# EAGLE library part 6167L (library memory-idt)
MEMORY

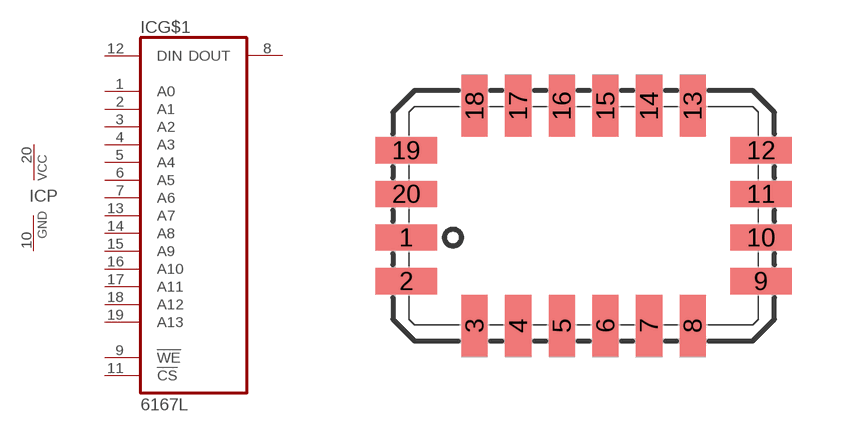
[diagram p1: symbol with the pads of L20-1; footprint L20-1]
Designator prefix IC; gates G$1=6167 P=VCCGND

## 6167L (OC_FARNELL: unknown; OC_NEWARK: unknown)  [L20-1]
1  G$1:A0  in
2  G$1:A1  in
3  G$1:A2  in
4  G$1:A3  in
5  G$1:A4  in
6  G$1:A5  in
7  G$1:A6  in
8  G$1:DOUT  out
9  G$1:!WE  in
10  P:GND  pwr
11  G$1:!CS  in
12  G$1:DIN  in
13  G$1:A7  in
14  G$1:A8  in
15  G$1:A9  in
16  G$1:A10  in
17  G$1:A11  in
18  G$1:A12  in
19  G$1:A13  in
20  P:VCC  pwr

## Footprint L20-1 (pad centres in mm)
PLASTIC LEADED CHIP CARRIER rectangle
smd 1.8 x 0.76: 1 -4.53,-0.635; 2 -4.53,-1.905; 9 5.8,-1.905; 10 5.8,-0.635; 11 5.8,0.635; 12 5.8,1.905; 19 -4.53,1.905; 20 -4.53,0.635
smd 0.76 x 1.8: 3 -2.54,-3.2; 4 -1.27,-3.2; 5 0,-3.2; 6 1.27,-3.2; 7 2.54,-3.2; 8 3.81,-3.2; 13 3.81,3.2; 14 2.54,3.2; 15 1.27,3.2; 16 0,3.2; 17 -1.27,3.2; 18 -2.54,3.2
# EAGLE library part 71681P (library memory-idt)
MEMORY

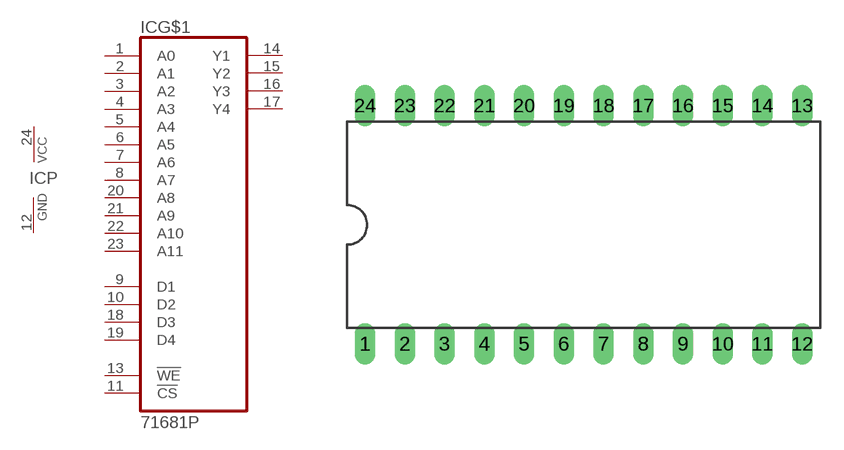
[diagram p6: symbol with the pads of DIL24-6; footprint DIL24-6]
Designator prefix IC; gates G$1=71681 P=VCCGND

## 71681P (OC_FARNELL: unknown; OC_NEWARK: unknown)  [DIL24-6]
1  G$1:A0  in
2  G$1:A1  in
3  G$1:A2  in
4  G$1:A3  in
5  G$1:A4  in
6  G$1:A5  in
7  G$1:A6  in
8  G$1:A7  in
9  G$1:D1  in
10  G$1:D2  in
11  G$1:!CS  in
12  P:GND  pwr
13  G$1:!WE  in
14  G$1:Y1  out
15  G$1:Y2  out
16  G$1:Y3  out
17  G$1:Y4  out
18  G$1:D3  in
19  G$1:D4  in
20  G$1:A8  in
21  G$1:A9  in
22  G$1:A10  in
23  G$1:A11  in
24  P:VCC  pwr

## Footprint DIL24-6 (pad centres in mm)
Dual In Line Package 0.6 inch
drill 0.813 long: 1 -13.97,-7.62; 2 -11.43,-7.62; 3 -8.89,-7.62; 4 -6.35,-7.62; 5 -3.81,-7.62; 6 -1.27,-7.62; 7 1.27,-7.62; 8 3.81,-7.62; 9 6.35,-7.62; 10 8.89,-7.62; 11 11.43,-7.62; 12 13.97,-7.62; 13 13.97,7.62; 14 11.43,7.62; 15 8.89,7.62; 16 6.35,7.62; 17 3.81,7.62; 18 1.27,7.62; 19 -1.27,7.62; 20 -3.81,7.62; 21 -6.35,7.62; 22 -8.89,7.62; 23 -11.43,7.62; 24 -13.97,7.62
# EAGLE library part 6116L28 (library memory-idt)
MEMORY

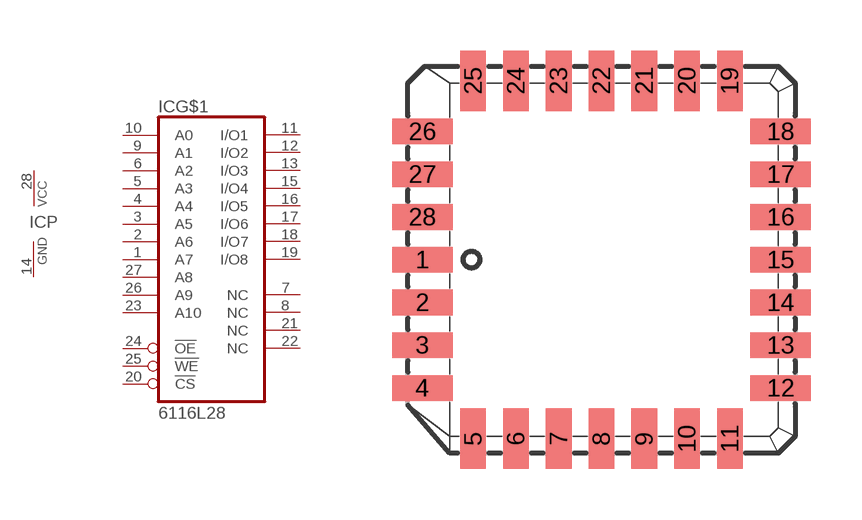
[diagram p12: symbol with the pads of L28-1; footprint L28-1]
Designator prefix IC; gates G$1=6116L28 P=VCCGND

## 6116L28 (OC_FARNELL: unknown; OC_NEWARK: unknown)  [L28-1]
1  G$1:A7  in
2  G$1:A6  in
3  G$1:A5  in
4  G$1:A4  in
5  G$1:A3  in
6  G$1:A2  in
7  G$1:NC  nc
8  G$1:NC  nc
9  G$1:A1  in
10  G$1:A0  in
11  G$1:I/O1
12  G$1:I/O2
13  G$1:I/O3
14  P:GND  pwr
15  G$1:I/O4
16  G$1:I/O5
17  G$1:I/O6
18  G$1:I/O7
19  G$1:I/O8
20  G$1:!CS  in
21  G$1:NC  nc
22  G$1:NC  nc
23  G$1:A10  in
24  G$1:!OE  in
25  G$1:!WE  in
26  G$1:A9  in
27  G$1:A8  in
28  P:VCC  pwr

## Footprint L28-1 (pad centres in mm)
PLASTIC LEADED CHIP CARRIER square
smd 1.8 x 0.76: 1 -5.32,0; 2 -5.32,-1.27; 3 -5.32,-2.54; 4 -5.32,-3.81; 12 5.32,-3.81; 13 5.32,-2.54; 14 5.32,-1.27; 15 5.32,0; 16 5.32,1.27; 17 5.32,2.54; 18 5.32,3.81; 26 -5.32,3.81; 27 -5.32,2.54; 28 -5.32,1.27
smd 0.76 x 1.8: 5 -3.81,-5.32; 6 -2.54,-5.32; 7 -1.27,-5.32; 8 0,-5.32; 9 1.27,-5.32; 10 2.54,-5.32; 11 3.81,-5.32; 19 3.81,5.32; 20 2.54,5.32; 21 1.27,5.32; 22 0,5.32; 23 -1.27,5.32; 24 -2.54,5.32; 25 -3.81,5.32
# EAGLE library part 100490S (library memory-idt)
MEMORY

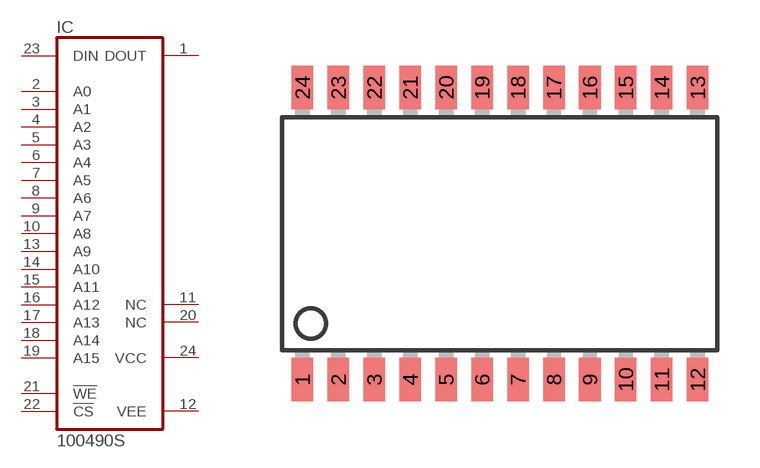
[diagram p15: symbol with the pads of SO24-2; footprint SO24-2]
Designator prefix IC

## 100490S (OC_FARNELL: unknown; OC_NEWARK: unknown)  [SO24-2]
1  DOUT  out
2  A0  in
3  A1  in
4  A2  in
5  A3  in
6  A4  in
7  A5  in
8  A6  in
9  A7  in
10  A8  in
11  NC  nc
12  VEE  pwr
13  A9  in
14  A10  in
15  A11  in
16  A12  in
17  A13  in
18  A14  in
19  A15  in
20  NC  nc
21  !WE  in
22  !CS  in
23  DIN  in
24  VCC  pwr

## Footprint SO24-2 (pad centres in mm)
Small Outline Package
smd 0.762 x 1.524: 1 -6.985,-5.156; 2 -5.715,-5.156; 3 -4.445,-5.156; 4 -3.175,-5.156; 5 -1.905,-5.156; 6 -0.635,-5.156; 7 0.635,-5.156; 8 1.905,-5.156; 9 3.175,-5.156; 10 4.445,-5.156; 11 5.715,-5.156; 12 6.985,-5.156; 13 6.985,5.156; 14 5.715,5.156; 15 4.445,5.156; 16 3.175,5.156; 17 1.905,5.156; 18 0.635,5.156; 19 -0.635,5.156; 20 -1.905,5.156; 21 -3.175,5.156; 22 -4.445,5.156; 23 -5.715,5.156; 24 -6.985,5.156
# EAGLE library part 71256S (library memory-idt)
MEMORY

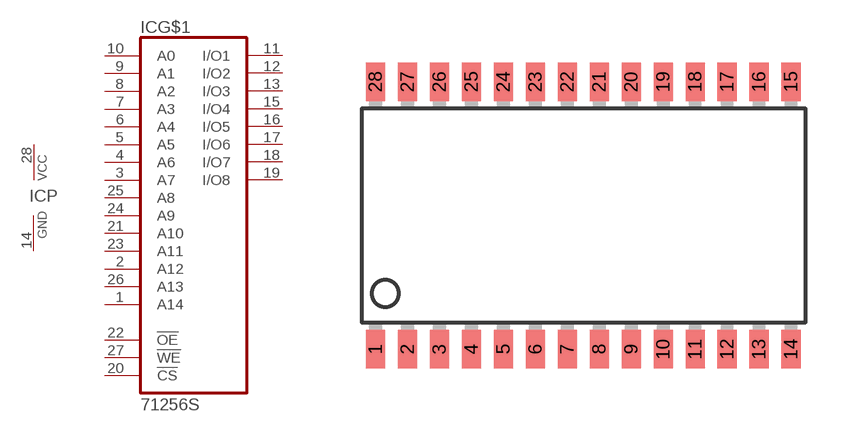
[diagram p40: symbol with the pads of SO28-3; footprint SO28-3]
Designator prefix IC; gates G$1=71256 P=VCCGND

## 71256S (MPN: IDT71256SA20YG; OC_FARNELL: 1218010; OC_NEWARK: 34M6449)  [SO28-3]
1  G$1:A14  in
2  G$1:A12  in
3  G$1:A7  in
4  G$1:A6  in
5  G$1:A5  in
6  G$1:A4  in
7  G$1:A3  in
8  G$1:A2  in
9  G$1:A1  in
10  G$1:A0  in
11  G$1:I/O1
12  G$1:I/O2
13  G$1:I/O3
14  P:GND  pwr
15  G$1:I/O4
16  G$1:I/O5
17  G$1:I/O6
18  G$1:I/O7
19  G$1:I/O8
20  G$1:!CS  in
21  G$1:A10  in
22  G$1:!OE  in
23  G$1:A11  in
24  G$1:A9  in
25  G$1:A8  in
26  G$1:A13  in
27  G$1:!WE  in
28  P:VCC  pwr

## Footprint SO28-3 (pad centres in mm)
Small Outline Package
smd 0.762 x 1.524: 1 -8.255,-5.315; 2 -6.985,-5.315; 3 -5.715,-5.315; 4 -4.445,-5.315; 5 -3.175,-5.315; 6 -1.905,-5.315; 7 -0.635,-5.315; 8 0.635,-5.315; 9 1.905,-5.315; 10 3.175,-5.315; 11 4.445,-5.315; 12 5.715,-5.315; 13 6.985,-5.315; 14 8.255,-5.315; 15 8.255,5.315; 16 6.985,5.315; 17 5.715,5.315; 18 4.445,5.315; 19 3.175,5.315; 20 1.905,5.315; 21 0.635,5.315; 22 -0.635,5.315; 23 -1.905,5.315; 24 -3.175,5.315; 25 -4.445,5.315; 26 -5.715,5.315; 27 -6.985,5.315; 28 -8.255,5.315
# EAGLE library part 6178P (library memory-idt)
MEMORY

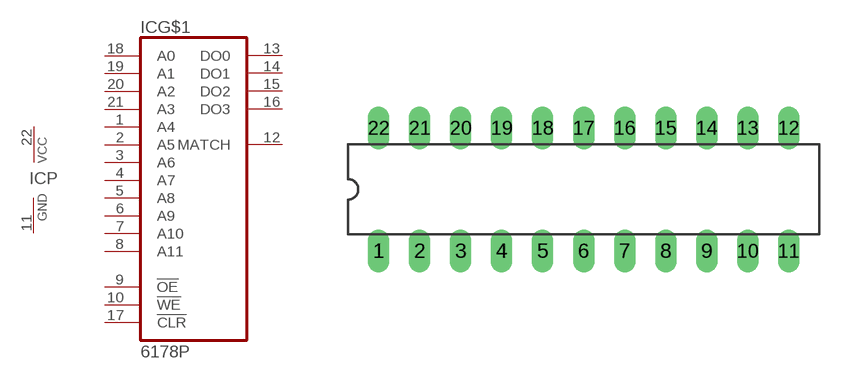
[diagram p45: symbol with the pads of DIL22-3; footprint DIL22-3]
Designator prefix IC; gates G$1=6178 P=VCCGND

## 6178P (OC_FARNELL: unknown; OC_NEWARK: unknown)  [DIL22-3]
1  G$1:A4  in
2  G$1:A5  in
3  G$1:A6  in
4  G$1:A7  in
5  G$1:A8  in
6  G$1:A9  in
7  G$1:A10  in
8  G$1:A11  in
9  G$1:!OE  in
10  G$1:!WE  in
11  P:GND  pwr
12  G$1:MATCH  out
13  G$1:DO0
14  G$1:DO1
15  G$1:DO2
16  G$1:DO3
17  G$1:!CLR  in
18  G$1:A0  in
19  G$1:A1  in
20  G$1:A2  in
21  G$1:A3  in
22  P:VCC  pwr

## Footprint DIL22-3 (pad centres in mm)
Dual In Line Package 0.3 inch
drill 0.813 long: 1 -12.7,-3.81; 2 -10.16,-3.81; 3 -7.62,-3.81; 4 -5.08,-3.81; 5 -2.54,-3.81; 6 0,-3.81; 7 2.54,-3.81; 8 5.08,-3.81; 9 7.62,-3.81; 10 10.16,-3.81; 11 12.7,-3.81; 12 12.7,3.81; 13 10.16,3.81; 14 7.62,3.81; 15 5.08,3.81; 16 2.54,3.81; 17 0,3.81; 18 -2.54,3.81; 19 -5.08,3.81; 20 -7.62,3.81; 21 -10.16,3.81; 22 -12.7,3.81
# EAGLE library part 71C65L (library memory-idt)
MEMORY

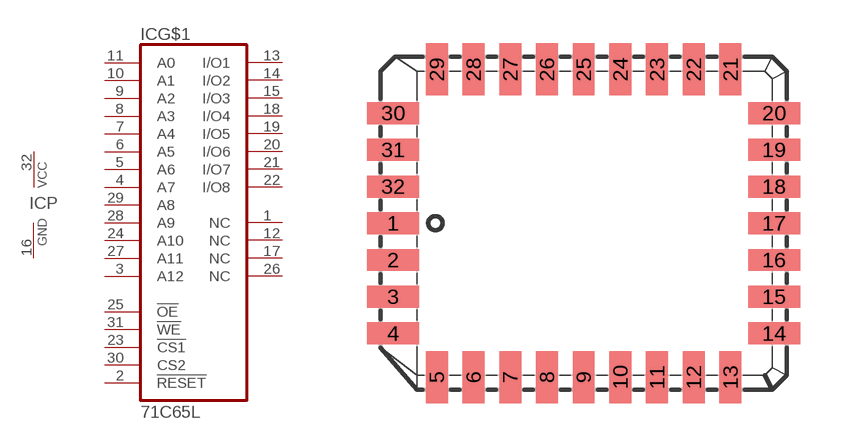
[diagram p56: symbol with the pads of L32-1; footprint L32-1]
Designator prefix IC; gates G$1=71C65L P=VCCGND

## 71C65L (OC_FARNELL: unknown; OC_NEWARK: unknown)  [L32-1]
1  G$1:NC  nc
2  G$1:!RESET  in
3  G$1:A12  in
4  G$1:A7  in
5  G$1:A6  in
6  G$1:A5  in
7  G$1:A4  in
8  G$1:A3  in
9  G$1:A2  in
10  G$1:A1  in
11  G$1:A0  in
12  G$1:NC  nc
13  G$1:I/O1
14  G$1:I/O2
15  G$1:I/O3
16  P:GND  pwr
17  G$1:NC  nc
18  G$1:I/O4
19  G$1:I/O5
20  G$1:I/O6
21  G$1:I/O7
22  G$1:I/O8
23  G$1:!CS1  in
24  G$1:A10  in
25  G$1:!OE  in
26  G$1:NC  nc
27  G$1:A11  in
28  G$1:A9  in
29  G$1:A8  in
30  G$1:CS2  in
31  G$1:!WE  in
32  P:VCC  pwr

## Footprint L32-1 (pad centres in mm)
PLASTIC LEADED CHIP CARRIER rectangle
smd 1.8 x 0.76: 1 -6.59,0; 2 -6.59,-1.27; 3 -6.59,-2.54; 4 -6.59,-3.81; 14 6.59,-3.81; 15 6.59,-2.54; 16 6.59,-1.27; 17 6.59,0; 18 6.59,1.27; 19 6.59,2.54; 20 6.59,3.81; 30 -6.59,3.81; 31 -6.59,2.54; 32 -6.59,1.27
smd 0.76 x 1.8: 5 -5.08,-5.32; 6 -3.81,-5.32; 7 -2.54,-5.32; 8 -1.27,-5.32; 9 0,-5.32; 10 1.27,-5.32; 11 2.54,-5.32; 12 3.81,-5.32; 13 5.08,-5.32; 21 5.08,5.32; 22 3.81,5.32; 23 2.54,5.32; 24 1.27,5.32; 25 0,5.32; 26 -1.27,5.32; 27 -2.54,5.32; 28 -3.81,5.32; 29 -5.08,5.32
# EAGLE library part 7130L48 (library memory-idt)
MEMORY

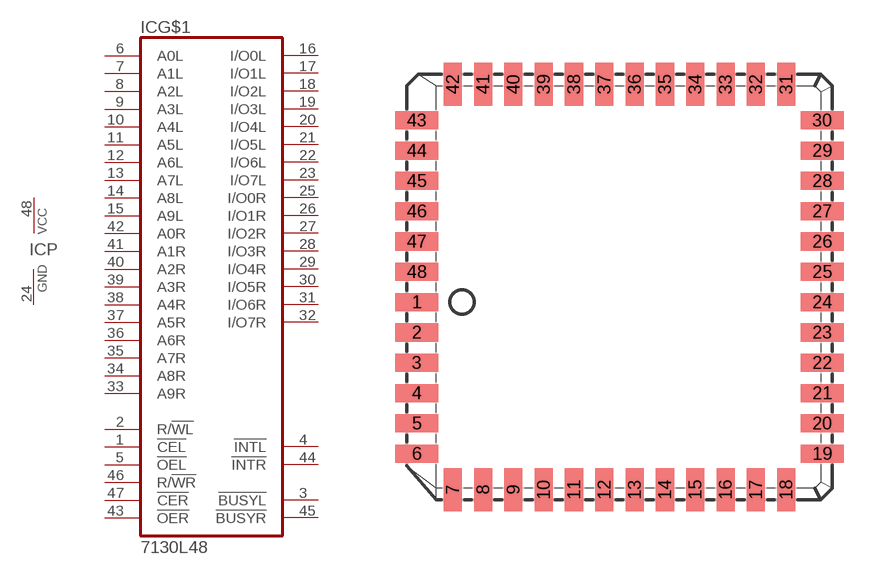
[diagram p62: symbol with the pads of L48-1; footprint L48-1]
Designator prefix IC; gates G$1=7130 P=VCCGND

## 7130L48 (OC_FARNELL: unknown; OC_NEWARK: unknown)  [L48-1]
1  G$1:!CEL  in
2  G$1:R/!WL  in
3  G$1:!BUSYL
4  G$1:!INTL  out
5  G$1:!OEL  in
6  G$1:A0L  in
7  G$1:A1L  in
8  G$1:A2L  in
9  G$1:A3L  in
10  G$1:A4L  in
11  G$1:A5L  in
12  G$1:A6L  in
13  G$1:A7L  in
14  G$1:A8L  in
15  G$1:A9L  in
16  G$1:I/O0L
17  G$1:I/O1L
18  G$1:I/O2L
19  G$1:I/O3L
20  G$1:I/O4L
21  G$1:I/O5L
22  G$1:I/O6L
23  G$1:I/O7L
24  P:GND  pwr
25  G$1:I/O0R
26  G$1:I/O1R
27  G$1:I/O2R
28  G$1:I/O3R
29  G$1:I/O4R
30  G$1:I/O5R
31  G$1:I/O6R
32  G$1:I/O7R
33  G$1:A9R  in
34  G$1:A8R  in
35  G$1:A7R  in
36  G$1:A6R  in
37  G$1:A5R  in
38  G$1:A4R  in
39  G$1:A3R  in
40  G$1:A2R  in
41  G$1:A1R  in
42  G$1:A0R  in
43  G$1:!OER  in
44  G$1:!INTR  out
45  G$1:!BUSYR
46  G$1:R/!WR  in
47  G$1:!CER  in
48  P:VCC  pwr

## Footprint L48-1 (pad centres in mm)
PLASTIC LEADED CHIP CARRIER square
smd 1.8 x 0.76: 1 -7.86,0; 2 -7.86,-1.27; 3 -7.86,-2.54; 4 -7.86,-3.81; 5 -7.86,-5.08; 6 -7.86,-6.35; 19 9.13,-6.35; 20 9.13,-5.08; 21 9.13,-3.81; 22 9.13,-2.54; 23 9.13,-1.27; 24 9.13,0; 25 9.13,1.27; 26 9.13,2.54; 27 9.13,3.81; 28 9.13,5.08; 29 9.13,6.35; 30 9.13,7.62; 43 -7.86,7.62; 44 -7.86,6.35; 45 -7.86,5.08; 46 -7.86,3.81; 47 -7.86,2.54; 48 -7.86,1.27
smd 0.76 x 1.8: 7 -6.35,-7.86; 8 -5.08,-7.86; 9 -3.81,-7.86; 10 -2.54,-7.86; 11 -1.27,-7.86; 12 0,-7.86; 13 1.27,-7.86; 14 2.54,-7.86; 15 3.81,-7.86; 16 5.08,-7.86; 17 6.35,-7.86; 18 7.62,-7.86; 31 7.62,9.13; 32 6.35,9.13; 33 5.08,9.13; 34 3.81,9.13; 35 2.54,9.13; 36 1.27,9.13; 37 0,9.13; 38 -1.27,9.13; 39 -2.54,9.13; 40 -3.81,9.13; 41 -5.08,9.13; 42 -6.35,9.13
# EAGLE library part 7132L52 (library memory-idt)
MEMORY

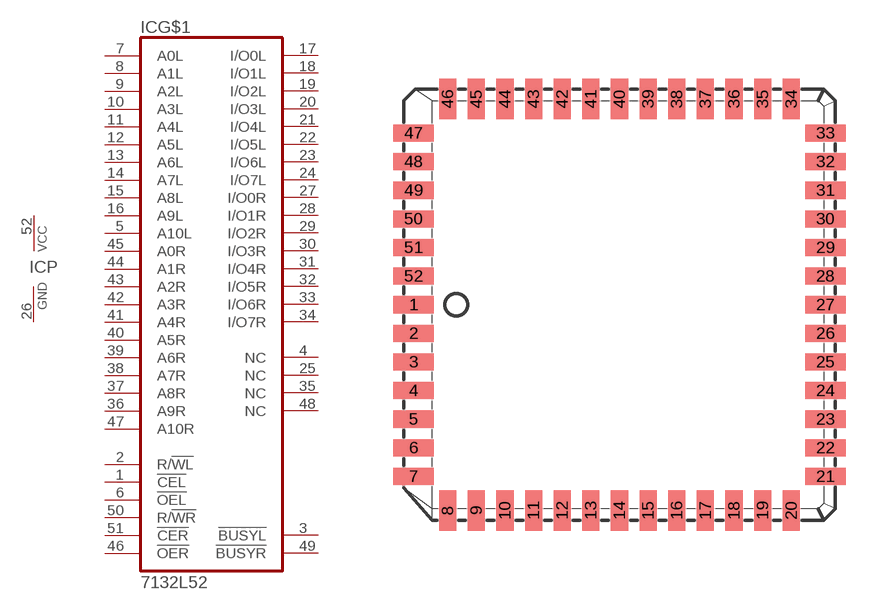
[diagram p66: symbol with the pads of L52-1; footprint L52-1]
Designator prefix IC; gates G$1=7132L P=VCCGND

## 7132L52 (MPN: IDT7132LA20JG; OC_FARNELL: 1688283; OC_NEWARK: 52R2132)  [L52-1]
1  G$1:!CEL  in
2  G$1:R/!WL  in
3  G$1:!BUSYL
4  G$1:NC  nc
5  G$1:A10L  in
6  G$1:!OEL  in
7  G$1:A0L  in
8  G$1:A1L  in
9  G$1:A2L  in
10  G$1:A3L  in
11  G$1:A4L  in
12  G$1:A5L  in
13  G$1:A6L  in
14  G$1:A7L  in
15  G$1:A8L  in
16  G$1:A9L  in
17  G$1:I/O0L
18  G$1:I/O1L
19  G$1:I/O2L
20  G$1:I/O3L
21  G$1:I/O4L
22  G$1:I/O5L
23  G$1:I/O6L
24  G$1:I/O7L
25  G$1:NC  nc
26  P:GND  pwr
27  G$1:I/O0R
28  G$1:I/O1R
29  G$1:I/O2R
30  G$1:I/O3R
31  G$1:I/O4R
32  G$1:I/O5R
33  G$1:I/O6R
34  G$1:I/O7R
35  G$1:NC  nc
36  G$1:A9R  in
37  G$1:A8R  in
38  G$1:A7R  in
39  G$1:A6R  in
40  G$1:A5R  in
41  G$1:A4R  in
42  G$1:A3R  in
43  G$1:A2R  in
44  G$1:A1R  in
45  G$1:A0R  in
46  G$1:!OER  in
47  G$1:A10R  in
48  G$1:NC  nc
49  G$1:!BUSYR
50  G$1:R/!WR  in
51  G$1:!CER  in
52  P:VCC  pwr

## Footprint L52-1 (pad centres in mm)
PLASTIC LEADED CHIP CARRIER square
smd 1.8 x 0.76: 1 -9.13,0; 2 -9.13,-1.27; 3 -9.13,-2.54; 4 -9.13,-3.81; 5 -9.13,-5.08; 6 -9.13,-6.35; 7 -9.13,-7.62; 21 9.13,-7.62; 22 9.13,-6.35; 23 9.13,-5.08; 24 9.13,-3.81; 25 9.13,-2.54; 26 9.13,-1.27; 27 9.13,0; 28 9.13,1.27; 29 9.13,2.54; 30 9.13,3.81; 31 9.13,5.08; 32 9.13,6.35; 33 9.13,7.62; 47 -9.13,7.62; 48 -9.13,6.35; 49 -9.13,5.08; 50 -9.13,3.81; 51 -9.13,2.54; 52 -9.13,1.27
smd 0.76 x 1.8: 8 -7.62,-9.13; 9 -6.35,-9.13; 10 -5.08,-9.13; 11 -3.81,-9.13; 12 -2.54,-9.13; 13 -1.27,-9.13; 14 0,-9.13; 15 1.27,-9.13; 16 2.54,-9.13; 17 3.81,-9.13; 18 5.08,-9.13; 19 6.35,-9.13; 20 7.62,-9.13; 34 7.62,9.13; 35 6.35,9.13; 36 5.08,9.13; 37 3.81,9.13; 38 2.54,9.13; 39 1.27,9.13; 40 0,9.13; 41 -1.27,9.13; 42 -2.54,9.13; 43 -3.81,9.13; 44 -5.08,9.13; 45 -6.35,9.13; 46 -7.62,9.13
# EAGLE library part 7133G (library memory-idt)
MEMORY

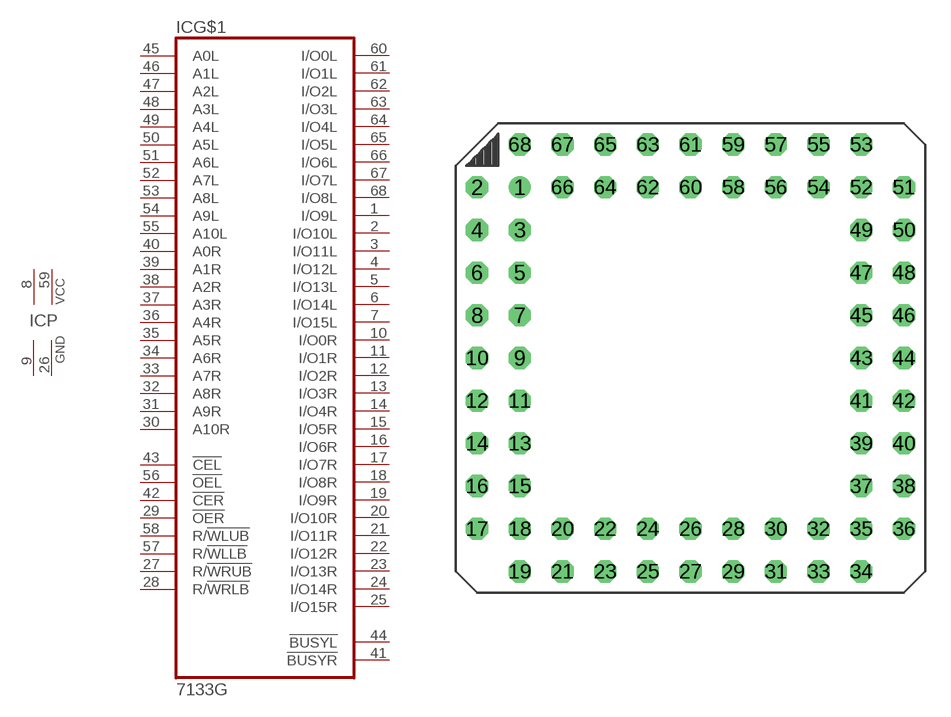
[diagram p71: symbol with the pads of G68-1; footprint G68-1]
Designator prefix IC; gates G$1=7133 P=2VCC2GND

## 7133G (OC_FARNELL: unknown; OC_NEWARK: unknown)  [G68-1]
1  G$1:I/O9L
2  G$1:I/O10L
3  G$1:I/O11L
4  G$1:I/O12L
5  G$1:I/O13L
6  G$1:I/O14L
7  G$1:I/O15L
8  P:VCC  pwr
9  P:GND  pwr
10  G$1:I/O0R
11  G$1:I/O1R
12  G$1:I/O2R
13  G$1:I/O3R
14  G$1:I/O4R
15  G$1:I/O5R
16  G$1:I/O6R
17  G$1:I/O7R
18  G$1:I/O8R
19  G$1:I/O9R
20  G$1:I/O10R
21  G$1:I/O11R
22  G$1:I/O12R
23  G$1:I/O13R
24  G$1:I/O14R
25  G$1:I/O15R
26  P:GND  pwr
27  G$1:R/!WRUB  in
28  G$1:R/!WRLB  in
29  G$1:!OER  in
30  G$1:A10R  in
31  G$1:A9R  in
32  G$1:A8R  in
33  G$1:A7R  in
34  G$1:A6R  in
35  G$1:A5R  in
36  G$1:A4R  in
37  G$1:A3R  in
38  G$1:A2R  in
39  G$1:A1R  in
40  G$1:A0R  in
41  G$1:!BUSYR  out
42  G$1:!CER  in
43  G$1:!CEL  in
44  G$1:!BUSYL  out
45  G$1:A0L  in
46  G$1:A1L  in
47  G$1:A2L  in
48  G$1:A3L  in
49  G$1:A4L  in
50  G$1:A5L  in
51  G$1:A6L  in
52  G$1:A7L  in
53  G$1:A8L  in
54  G$1:A9L  in
55  G$1:A10L  in
56  G$1:!OEL  in
57  G$1:R/!WLLB  in
58  G$1:R/!WLUB  in
59  P:VCC  pwr
60  G$1:I/O0L
61  G$1:I/O1L
62  G$1:I/O2L
63  G$1:I/O3L
64  G$1:I/O4L
65  G$1:I/O5L
66  G$1:I/O6L
67  G$1:I/O7L
68  G$1:I/O8L

## Footprint G68-1 (pad centres in mm)
Grid Array
drill 0.813 round: 1 -10.16,10.16
drill 0.813 octagon: 2 -12.7,10.16; 3 -10.16,7.62; 4 -12.7,7.62; 5 -10.16,5.08; 6 -12.7,5.08; 7 -10.16,2.54; 8 -12.7,2.54; 9 -10.16,0; 10 -12.7,0; 11 -10.16,-2.54; 12 -12.7,-2.54; 13 -10.16,-5.08; 14 -12.7,-5.08; 15 -10.16,-7.62; 16 -12.7,-7.62; 17 -12.7,-10.16; 18 -10.16,-10.16; 19 -10.16,-12.7; 20 -7.62,-10.16; 21 -7.62,-12.7; 22 -5.08,-10.16; 23 -5.08,-12.7; 24 -2.54,-10.16; 25 -2.54,-12.7; 26 0,-10.16; 27 0,-12.7; 28 2.54,-10.16; 29 2.54,-12.7; 30 5.08,-10.16; 31 5.08,-12.7; 32 7.62,-10.16; 33 7.62,-12.7; 34 10.16,-12.7; 35 10.16,-10.16; 36 12.7,-10.16; 37 10.16,-7.62; 38 12.7,-7.62; 39 10.16,-5.08; 40 12.7,-5.08; 41 10.16,-2.54; 42 12.7,-2.54; 43 10.16,0; 44 12.7,0; 45 10.16,2.54; 46 12.7,2.54; 47 10.16,5.08; 48 12.7,5.08; 49 10.16,7.62; 50 12.7,7.62; 51 12.7,10.16; 52 10.16,10.16; 53 10.16,12.7; 54 7.62,10.16; 55 7.62,12.7; 56 5.08,10.16; 57 5.08,12.7; 58 2.54,10.16; 59 2.54,12.7; 60 0,10.16; 61 0,12.7; 62 -2.54,10.16; 63 -2.54,12.7; 64 -5.08,10.16; 65 -5.08,12.7; 66 -7.62,10.16; 67 -7.62,12.7; 68 -10.16,12.7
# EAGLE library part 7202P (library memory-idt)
MEMORY

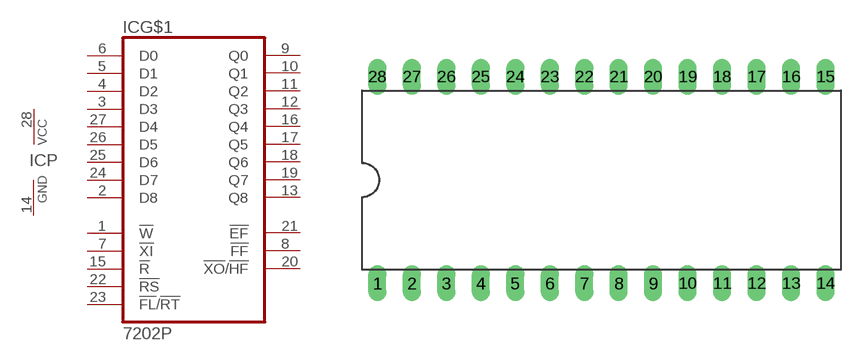
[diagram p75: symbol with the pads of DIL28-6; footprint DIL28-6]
Designator prefix IC; gates G$1=7202 P=VCCGND

## 7202P (OC_FARNELL: unknown; OC_NEWARK: unknown)  [DIL28-6]
1  G$1:!W  in
2  G$1:D8  in
3  G$1:D3  in
4  G$1:D2  in
5  G$1:D1  in
6  G$1:D0  in
7  G$1:!XI  in
8  G$1:!FF  out
9  G$1:Q0  out
10  G$1:Q1  out
11  G$1:Q2  out
12  G$1:Q3  out
13  G$1:Q8  out
14  P:GND  pwr
15  G$1:!R  in
16  G$1:Q4  out
17  G$1:Q5  out
18  G$1:Q6  out
19  G$1:Q7  out
20  G$1:!XO!/!HF  out
21  G$1:!EF  out
22  G$1:!RS  in
23  G$1:!FL!/!RT  in
24  G$1:D7  in
25  G$1:D6  in
26  G$1:D5  in
27  G$1:D4  in
28  P:VCC  pwr

## Footprint DIL28-6 (pad centres in mm)
Dual In Line Package 0.6 inch
drill 0.813 long: 1 -16.51,-7.62; 2 -13.97,-7.62; 3 -11.43,-7.62; 4 -8.89,-7.62; 5 -6.35,-7.62; 6 -3.81,-7.62; 7 -1.27,-7.62; 8 1.27,-7.62; 9 3.81,-7.62; 10 6.35,-7.62; 11 8.89,-7.62; 12 11.43,-7.62; 13 13.97,-7.62; 14 16.51,-7.62; 15 16.51,7.62; 16 13.97,7.62; 17 11.43,7.62; 18 8.89,7.62; 19 6.35,7.62; 20 3.81,7.62; 21 1.27,7.62; 22 -1.27,7.62; 23 -3.81,7.62; 24 -6.35,7.62; 25 -8.89,7.62; 26 -11.43,7.62; 27 -13.97,7.62; 28 -16.51,7.62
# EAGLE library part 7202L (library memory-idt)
MEMORY

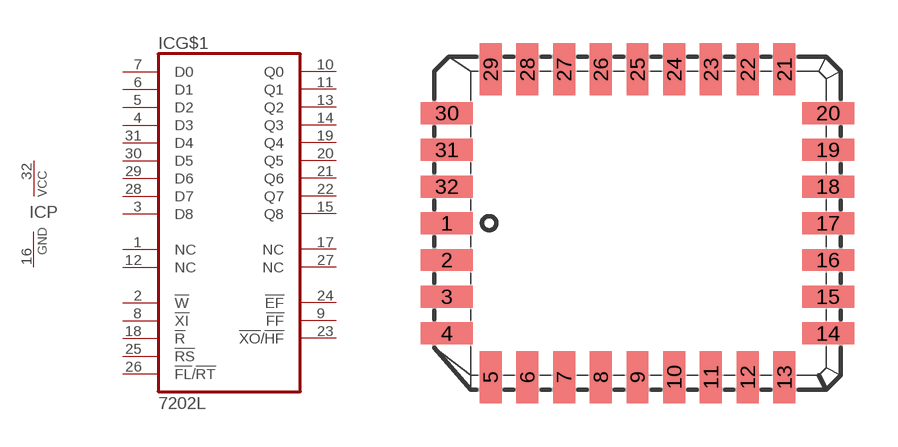
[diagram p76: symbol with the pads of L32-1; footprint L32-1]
Designator prefix IC; gates G$1=7202L P=VCCGND

## 7202L (MPN: IDT7202LA35JG; OC_FARNELL: 1218006; OC_NEWARK: 24M2901)  [L32-1]
1  G$1:NC  nc
2  G$1:!W  in
3  G$1:D8  in
4  G$1:D3  in
5  G$1:D2  in
6  G$1:D1  in
7  G$1:D0  in
8  G$1:!XI  in
9  G$1:!FF  out
10  G$1:Q0  out
11  G$1:Q1  out
12  G$1:NC  nc
13  G$1:Q2  out
14  G$1:Q3  out
15  G$1:Q8  out
16  P:GND  pwr
17  G$1:NC  nc
18  G$1:!R  in
19  G$1:Q4  out
20  G$1:Q5  out
21  G$1:Q6  out
22  G$1:Q7  out
23  G$1:!XO!/!HF  out
24  G$1:!EF  out
25  G$1:!RS  in
26  G$1:!FL!/!RT  in
27  G$1:NC  nc
28  G$1:D7  in
29  G$1:D6  in
30  G$1:D5  in
31  G$1:D4  in
32  P:VCC  pwr

## Footprint L32-1 (pad centres in mm)
PLASTIC LEADED CHIP CARRIER rectangle
smd 1.8 x 0.76: 1 -6.59,0; 2 -6.59,-1.27; 3 -6.59,-2.54; 4 -6.59,-3.81; 14 6.59,-3.81; 15 6.59,-2.54; 16 6.59,-1.27; 17 6.59,0; 18 6.59,1.27; 19 6.59,2.54; 20 6.59,3.81; 30 -6.59,3.81; 31 -6.59,2.54; 32 -6.59,1.27
smd 0.76 x 1.8: 5 -5.08,-5.32; 6 -3.81,-5.32; 7 -2.54,-5.32; 8 -1.27,-5.32; 9 0,-5.32; 10 1.27,-5.32; 11 2.54,-5.32; 12 3.81,-5.32; 13 5.08,-5.32; 21 5.08,5.32; 22 3.81,5.32; 23 2.54,5.32; 24 1.27,5.32; 25 0,5.32; 26 -1.27,5.32; 27 -2.54,5.32; 28 -3.81,5.32; 29 -5.08,5.32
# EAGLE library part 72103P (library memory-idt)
MEMORY

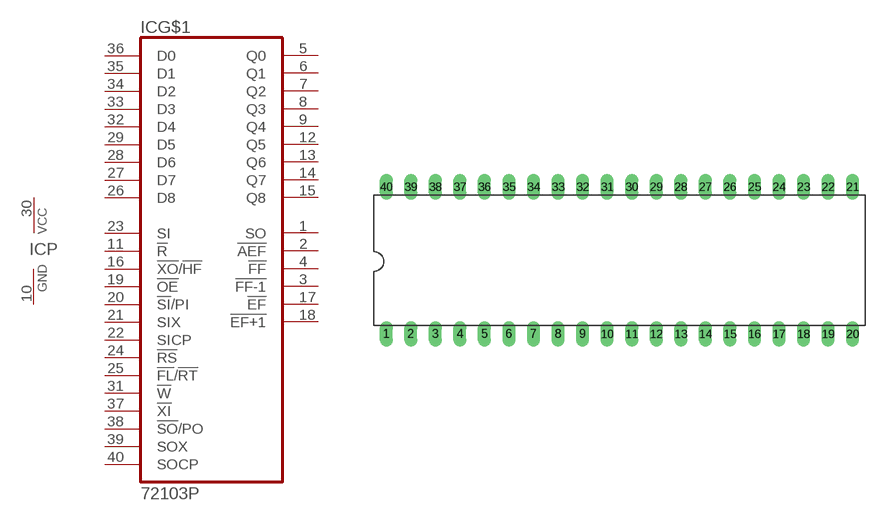
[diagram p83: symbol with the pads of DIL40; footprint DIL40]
Designator prefix IC; gates G$1=72103 P=VCCGND

## 72103P (OC_FARNELL: unknown; OC_NEWARK: unknown)  [DIL40]
1  G$1:SO  out
2  G$1:!AEF  out
3  G$1:!FF-1  out
4  G$1:!FF  out
5  G$1:Q0  out
6  G$1:Q1  out
7  G$1:Q2  out
8  G$1:Q3  out
9  G$1:Q4  out
10  P:GND  pwr
11  G$1:!R  in
12  G$1:Q5  out
13  G$1:Q6  out
14  G$1:Q7  out
15  G$1:Q8  out
16  G$1:!XO!/!HF  in
17  G$1:!EF  out
18  G$1:!EF+1  out
19  G$1:!OE  in
20  G$1:!SI!/PI  in
21  G$1:SIX  in
22  G$1:SICP  in
23  G$1:SI  in
24  G$1:!RS  in
25  G$1:!FL!/!RT  in
26  G$1:D8  in
27  G$1:D7  in
28  G$1:D6  in
29  G$1:D5  in
30  P:VCC  pwr
31  G$1:!W  in
32  G$1:D4  in
33  G$1:D3  in
34  G$1:D2  in
35  G$1:D1  in
36  G$1:D0  in
37  G$1:!XI  in
38  G$1:!SO!/PO  in
39  G$1:SOX  in
40  G$1:SOCP  in

## Footprint DIL40 (pad centres in mm)
Dual In Line Package
drill 0.813 long: 1 -24.13,-7.62; 2 -21.59,-7.62; 3 -19.05,-7.62; 4 -16.51,-7.62; 5 -13.97,-7.62; 6 -11.43,-7.62; 7 -8.89,-7.62; 8 -6.35,-7.62; 9 -3.81,-7.62; 10 -1.27,-7.62; 11 1.27,-7.62; 12 3.81,-7.62; 13 6.35,-7.62; 14 8.89,-7.62; 15 11.43,-7.62; 16 13.97,-7.62; 17 16.51,-7.62; 18 19.05,-7.62; 19 21.59,-7.62; 20 24.13,-7.62; 21 24.13,7.62; 22 21.59,7.62; 23 19.05,7.62; 24 16.51,7.62; 25 13.97,7.62; 26 11.43,7.62; 27 8.89,7.62; 28 6.35,7.62; 29 3.81,7.62; 30 1.27,7.62; 31 -1.27,7.62; 32 -3.81,7.62; 33 -6.35,7.62; 34 -8.89,7.62; 35 -11.43,7.62; 36 -13.97,7.62; 37 -16.51,7.62; 38 -19.05,7.62; 39 -21.59,7.62; 40 -24.13,7.62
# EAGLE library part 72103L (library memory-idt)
MEMORY

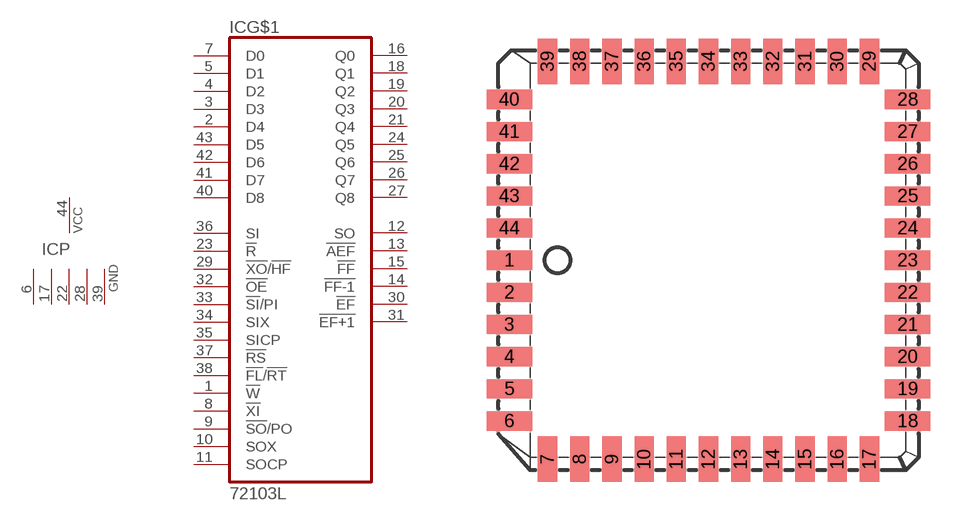
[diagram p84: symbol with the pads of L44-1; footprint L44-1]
Designator prefix IC; gates G$1=72103 P=1VCC5GND

## 72103L (OC_FARNELL: unknown; OC_NEWARK: unknown)  [L44-1]
1  G$1:!W  in
2  G$1:D4  in
3  G$1:D3  in
4  G$1:D2  in
5  G$1:D1  in
6  P:GND  pwr
7  G$1:D0  in
8  G$1:!XI  in
9  G$1:!SO!/PO  in
10  G$1:SOX  in
11  G$1:SOCP  in
12  G$1:SO  out
13  G$1:!AEF  out
14  G$1:!FF-1  out
15  G$1:!FF  out
16  G$1:Q0  out
17  P:GND  pwr
18  G$1:Q1  out
19  G$1:Q2  out
20  G$1:Q3  out
21  G$1:Q4  out
22  P:GND  pwr
23  G$1:!R  in
24  G$1:Q5  out
25  G$1:Q6  out
26  G$1:Q7  out
27  G$1:Q8  out
28  P:GND  pwr
29  G$1:!XO!/!HF  in
30  G$1:!EF  out
31  G$1:!EF+1  out
32  G$1:!OE  in
33  G$1:!SI!/PI  in
34  G$1:SIX  in
35  G$1:SICP  in
36  G$1:SI  in
37  G$1:!RS  in
38  G$1:!FL!/!RT  in
39  P:GND  pwr
40  G$1:D8  in
41  G$1:D7  in
42  G$1:D6  in
43  G$1:D5  in
44  P:VCC  pwr

## Footprint L44-1 (pad centres in mm)
PLASTIC LEADED CHIP CARRIER square
smd 1.8 x 0.76: 1 -7.86,0; 2 -7.86,-1.27; 3 -7.86,-2.54; 4 -7.86,-3.81; 5 -7.86,-5.08; 6 -7.86,-6.35; 18 7.86,-6.35; 19 7.86,-5.08; 20 7.86,-3.81; 21 7.86,-2.54; 22 7.86,-1.27; 23 7.86,0; 24 7.86,1.27; 25 7.86,2.54; 26 7.86,3.81; 27 7.86,5.08; 28 7.86,6.35; 40 -7.86,6.35; 41 -7.86,5.08; 42 -7.86,3.81; 43 -7.86,2.54; 44 -7.86,1.27
smd 0.76 x 1.8: 7 -6.35,-7.86; 8 -5.08,-7.86; 9 -3.81,-7.86; 10 -2.54,-7.86; 11 -1.27,-7.86; 12 0,-7.86; 13 1.27,-7.86; 14 2.54,-7.86; 15 3.81,-7.86; 16 5.08,-7.86; 17 6.35,-7.86; 29 6.35,7.86; 30 5.08,7.86; 31 3.81,7.86; 32 2.54,7.86; 33 1.27,7.86; 34 0,7.86; 35 -1.27,7.86; 36 -2.54,7.86; 37 -3.81,7.86; 38 -5.08,7.86; 39 -6.35,7.86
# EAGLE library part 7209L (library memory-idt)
MEMORY

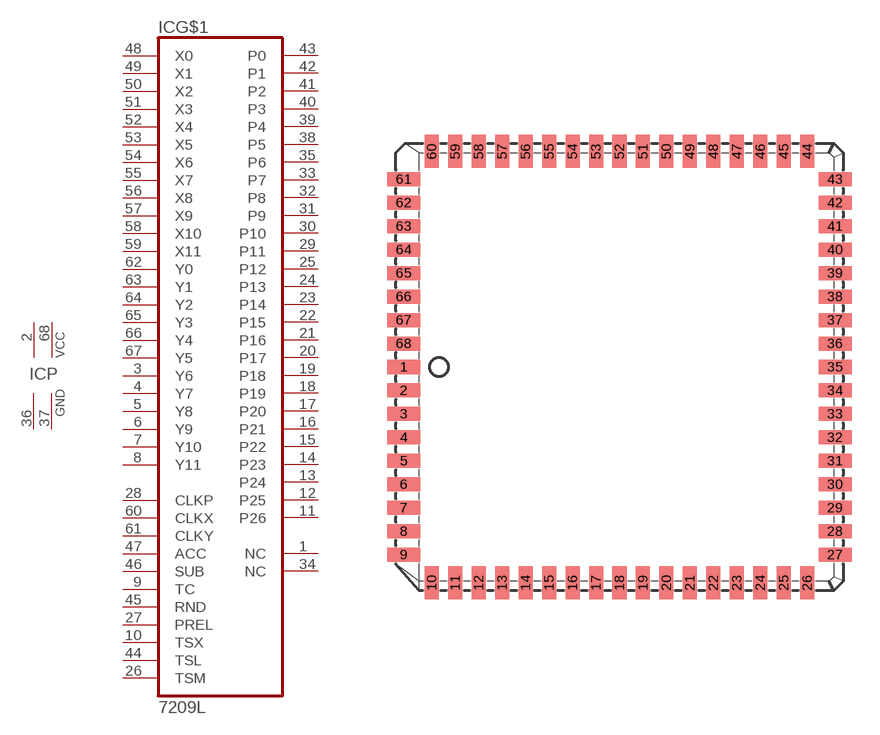
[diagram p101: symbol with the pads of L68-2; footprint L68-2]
Designator prefix IC; gates G$1=7209L P=2VCC2GND

## 7209L (OC_FARNELL: unknown; OC_NEWARK: unknown)  [L68-2]
1  G$1:NC  nc
2  P:VCC  pwr
3  G$1:Y6  in
4  G$1:Y7  in
5  G$1:Y8  in
6  G$1:Y9  in
7  G$1:Y10  in
8  G$1:Y11  in
9  G$1:TC  in
10  G$1:TSX  in
11  G$1:P26  out
12  G$1:P25  out
13  G$1:P24  out
14  G$1:P23  out
15  G$1:P22  out
16  G$1:P21  out
17  G$1:P20  out
18  G$1:P19  out
19  G$1:P18  out
20  G$1:P17  out
21  G$1:P16  out
22  G$1:P15  out
23  G$1:P14  out
24  G$1:P13  out
25  G$1:P12  out
26  G$1:TSM  in
27  G$1:PREL  in
28  G$1:CLKP  in
29  G$1:P11  out
30  G$1:P10  out
31  G$1:P9  out
32  G$1:P8  out
33  G$1:P7  out
34  G$1:NC  nc
35  G$1:P6  out
36  P:GND  pwr
37  P:GND  pwr
38  G$1:P5  out
39  G$1:P4  out
40  G$1:P3  out
41  G$1:P2  out
42  G$1:P1  out
43  G$1:P0  out
44  G$1:TSL  in
45  G$1:RND  in
46  G$1:SUB  in
47  G$1:ACC  in
48  G$1:X0  in
49  G$1:X1  in
50  G$1:X2  in
51  G$1:X3  in
52  G$1:X4  in
53  G$1:X5  in
54  G$1:X6  in
55  G$1:X7  in
56  G$1:X8  in
57  G$1:X9  in
58  G$1:X10  in
59  G$1:X11  in
60  G$1:CLKX  in
61  G$1:CLKY  in
62  G$1:Y0  in
63  G$1:Y1  in
64  G$1:Y2  in
65  G$1:Y3  in
66  G$1:Y4  in
67  G$1:Y5  in
68  P:VCC  pwr

## Footprint L68-2 (pad centres in mm)
PLASTIC LEADED CHIP CARRIER square
smd 1.8 x 0.76: 1 -11.67,0; 2 -11.67,-1.27; 3 -11.67,-2.54; 4 -11.67,-3.81; 5 -11.67,-5.08; 6 -11.67,-6.35; 7 -11.67,-7.62; 8 -11.67,-8.89; 9 -11.67,-10.16; 27 11.67,-10.16; 28 11.67,-8.89; 29 11.67,-7.62; 30 11.67,-6.35; 31 11.67,-5.08; 32 11.67,-3.81; 33 11.67,-2.54; 34 11.67,-1.27; 35 11.67,0; 36 11.67,1.27; 37 11.67,2.54; 38 11.67,3.81; 39 11.67,5.08; 40 11.67,6.35; 41 11.67,7.62; 42 11.67,8.89; 43 11.67,10.16; 61 -11.67,10.16; 62 -11.67,8.89; 63 -11.67,7.62; 64 -11.67,6.35; 65 -11.67,5.08; 66 -11.67,3.81; 67 -11.67,2.54; 68 -11.67,1.27
smd 0.76 x 1.8: 10 -10.16,-11.67; 11 -8.89,-11.67; 12 -7.62,-11.67; 13 -6.35,-11.67; 14 -5.08,-11.67; 15 -3.81,-11.67; 16 -2.54,-11.67; 17 -1.27,-11.67; 18 0,-11.67; 19 1.27,-11.67; 20 2.54,-11.67; 21 3.81,-11.67; 22 5.08,-11.67; 23 6.35,-11.67; 24 7.62,-11.67; 25 8.89,-11.67; 26 10.16,-11.67; 44 10.16,11.67; 45 8.89,11.67; 46 7.62,11.67; 47 6.35,11.67; 48 5.08,11.67; 49 3.81,11.67; 50 2.54,11.67; 51 1.27,11.67; 52 0,11.67; 53 -1.27,11.67; 54 -2.54,11.67; 55 -3.81,11.67; 56 -5.08,11.67; 57 -6.35,11.67; 58 -7.62,11.67; 59 -8.89,11.67; 60 -10.16,11.67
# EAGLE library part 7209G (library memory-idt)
MEMORY

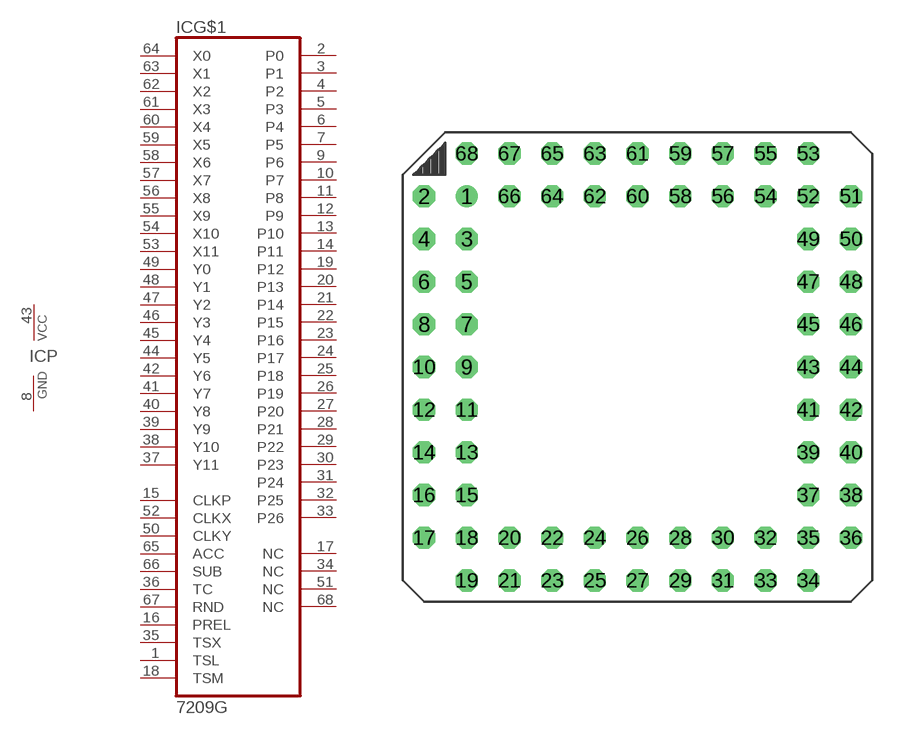
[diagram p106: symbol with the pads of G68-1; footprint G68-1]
Designator prefix IC; gates G$1=7209G P=VCCGND

## 7209G (OC_FARNELL: unknown; OC_NEWARK: unknown)  [G68-1]
1  G$1:TSL  in
2  G$1:P0  out
3  G$1:P1  out
4  G$1:P2  out
5  G$1:P3  out
6  G$1:P4  out
7  G$1:P5  out
8  P:GND  pwr
9  G$1:P6  out
10  G$1:P7  out
11  G$1:P8  out
12  G$1:P9  out
13  G$1:P10  out
14  G$1:P11  out
15  G$1:CLKP  in
16  G$1:PREL  in
17  G$1:NC  nc
18  G$1:TSM  in
19  G$1:P12  out
20  G$1:P13  out
21  G$1:P14  out
22  G$1:P15  out
23  G$1:P16  out
24  G$1:P17  out
25  G$1:P18  out
26  G$1:P19  out
27  G$1:P20  out
28  G$1:P21  out
29  G$1:P22  out
30  G$1:P23  out
31  G$1:P24  out
32  G$1:P25  out
33  G$1:P26  out
34  G$1:NC  nc
35  G$1:TSX  in
36  G$1:TC  in
37  G$1:Y11  in
38  G$1:Y10  in
39  G$1:Y9  in
40  G$1:Y8  in
41  G$1:Y7  in
42  G$1:Y6  in
43  P:VCC  pwr
44  G$1:Y5  in
45  G$1:Y4  in
46  G$1:Y3  in
47  G$1:Y2  in
48  G$1:Y1  in
49  G$1:Y0  in
50  G$1:CLKY  in
51  G$1:NC  nc
52  G$1:CLKX  in
53  G$1:X11  in
54  G$1:X10  in
55  G$1:X9  in
56  G$1:X8  in
57  G$1:X7  in
58  G$1:X6  in
59  G$1:X5  in
60  G$1:X4  in
61  G$1:X3  in
62  G$1:X2  in
63  G$1:X1  in
64  G$1:X0  in
65  G$1:ACC  in
66  G$1:SUB  in
67  G$1:RND  in
68  G$1:NC  nc

## Footprint G68-1 (pad centres in mm)
Grid Array
drill 0.813 round: 1 -10.16,10.16
drill 0.813 octagon: 2 -12.7,10.16; 3 -10.16,7.62; 4 -12.7,7.62; 5 -10.16,5.08; 6 -12.7,5.08; 7 -10.16,2.54; 8 -12.7,2.54; 9 -10.16,0; 10 -12.7,0; 11 -10.16,-2.54; 12 -12.7,-2.54; 13 -10.16,-5.08; 14 -12.7,-5.08; 15 -10.16,-7.62; 16 -12.7,-7.62; 17 -12.7,-10.16; 18 -10.16,-10.16; 19 -10.16,-12.7; 20 -7.62,-10.16; 21 -7.62,-12.7; 22 -5.08,-10.16; 23 -5.08,-12.7; 24 -2.54,-10.16; 25 -2.54,-12.7; 26 0,-10.16; 27 0,-12.7; 28 2.54,-10.16; 29 2.54,-12.7; 30 5.08,-10.16; 31 5.08,-12.7; 32 7.62,-10.16; 33 7.62,-12.7; 34 10.16,-12.7; 35 10.16,-10.16; 36 12.7,-10.16; 37 10.16,-7.62; 38 12.7,-7.62; 39 10.16,-5.08; 40 12.7,-5.08; 41 10.16,-2.54; 42 12.7,-2.54; 43 10.16,0; 44 12.7,0; 45 10.16,2.54; 46 12.7,2.54; 47 10.16,5.08; 48 12.7,5.08; 49 10.16,7.62; 50 12.7,7.62; 51 12.7,10.16; 52 10.16,10.16; 53 10.16,12.7; 54 7.62,10.16; 55 7.62,12.7; 56 5.08,10.16; 57 5.08,12.7; 58 2.54,10.16; 59 2.54,12.7; 60 0,10.16; 61 0,12.7; 62 -2.54,10.16; 63 -2.54,12.7; 64 -5.08,10.16; 65 -5.08,12.7; 66 -7.62,10.16; 67 -7.62,12.7; 68 -10.16,12.7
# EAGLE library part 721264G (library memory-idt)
MEMORY

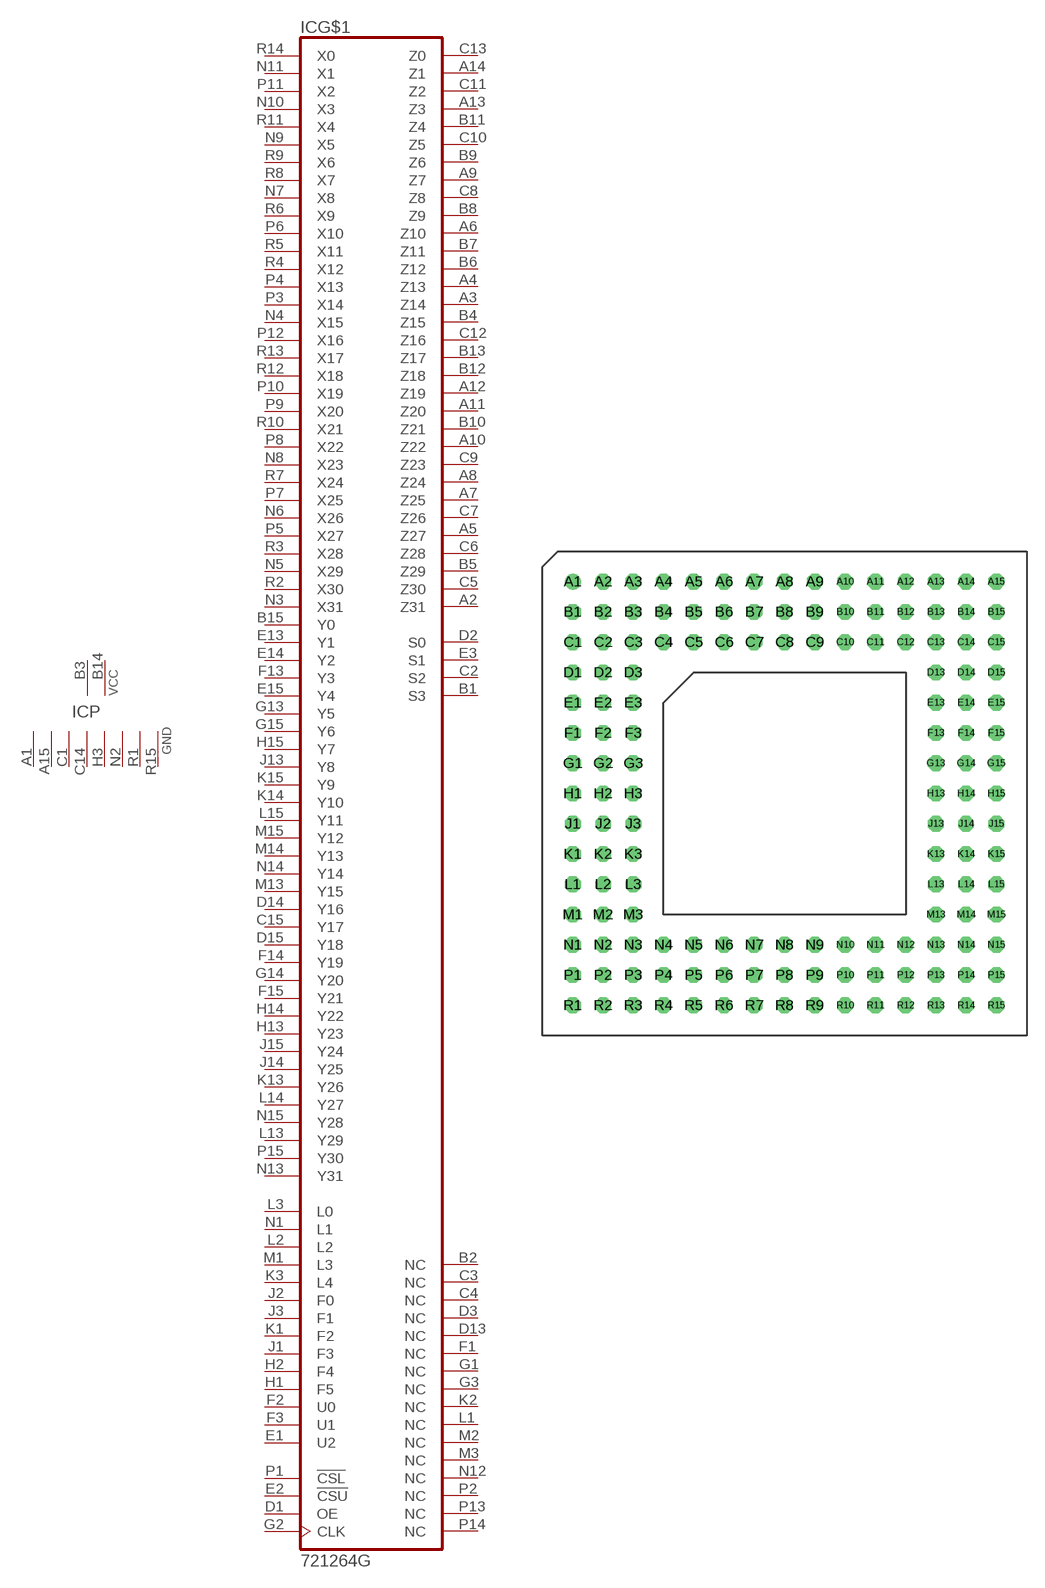
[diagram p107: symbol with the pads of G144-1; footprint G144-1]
Designator prefix IC; gates G$1=721264 P=2VCC8GND

## 721264G (OC_FARNELL: unknown; OC_NEWARK: unknown)  [G144-1]
A1  P:GND  pwr
A2  G$1:Z31  out
A3  G$1:Z14  out
A4  G$1:Z13  out
A5  G$1:Z27  out
A6  G$1:Z10  out
A7  G$1:Z25  out
A8  G$1:Z24  out
A9  G$1:Z7  out
A10  G$1:Z22  out
A11  G$1:Z20  out
A12  G$1:Z19  out
A13  G$1:Z3  out
A14  G$1:Z1  out
A15  P:GND  pwr
B1  G$1:S3  out
B2  G$1:NC  nc
B3  P:VCC  pwr
B4  G$1:Z15  out
B5  G$1:Z29  out
B6  G$1:Z12  out
B7  G$1:Z11  out
B8  G$1:Z9  out
B9  G$1:Z6  out
B10  G$1:Z21  out
B11  G$1:Z4  out
B12  G$1:Z18  out
B13  G$1:Z17  out
B14  P:VCC  pwr
B15  G$1:Y0  in
C1  P:GND  pwr
C2  G$1:S2  out
C3  G$1:NC  nc
C4  G$1:NC  nc
C5  G$1:Z30  out
C6  G$1:Z28  out
C7  G$1:Z26  out
C8  G$1:Z8  out
C9  G$1:Z23  out
C10  G$1:Z5  out
C11  G$1:Z2  out
C12  G$1:Z16  out
C13  G$1:Z0  out
C14  P:GND  pwr
C15  G$1:Y17  in
D1  G$1:OE  in
D2  G$1:S0  out
D3  G$1:NC  nc
D13  G$1:NC  nc
D14  G$1:Y16  in
D15  G$1:Y18  in
E1  G$1:U2  in
E2  G$1:!CSU  in
E3  G$1:S1  out
E13  G$1:Y1  in
E14  G$1:Y2  in
E15  G$1:Y4  in
F1  G$1:NC  nc
F2  G$1:U0  in
F3  G$1:U1  in
F13  G$1:Y3  in
F14  G$1:Y19  in
F15  G$1:Y21  in
G1  G$1:NC  nc
G2  G$1:CLK  in
G3  G$1:NC  nc
G13  G$1:Y5  in
G14  G$1:Y20  in
G15  G$1:Y6  in
H1  G$1:F5  in
H2  G$1:F4  in
H3  P:GND  pwr
H13  G$1:Y23  in
H14  G$1:Y22  in
H15  G$1:Y7  in
J1  G$1:F3  in
J2  G$1:F0  in
J3  G$1:F1  in
J13  G$1:Y8  in
J14  G$1:Y25  in
J15  G$1:Y24  in
K1  G$1:F2  in
K2  G$1:NC  nc
K3  G$1:L4  in
K13  G$1:Y26  in
K14  G$1:Y10  in
K15  G$1:Y9  in
L1  G$1:NC  nc
L2  G$1:L2  in
L3  G$1:L0  in
L13  G$1:Y29  in
L14  G$1:Y27  in
L15  G$1:Y11  in
M1  G$1:L3  in
M2  G$1:NC  nc
M3  G$1:NC  nc
M13  G$1:Y15  in
M14  G$1:Y13  in
M15  G$1:Y12  in
N1  G$1:L1  in
N2  P:GND  pwr
N3  G$1:X31  in
N4  G$1:X15  in
N5  G$1:X29  in
N6  G$1:X26  in
N7  G$1:X8  in
N8  G$1:X23  in
N9  G$1:X5  in
N10  G$1:X3  in
N11  G$1:X1  in
N12  G$1:NC  nc
N13  G$1:Y31  in
N14  G$1:Y14  in
N15  G$1:Y28  in
P1  G$1:!CSL  in
P2  G$1:NC  nc
P3  G$1:X14  in
P4  G$1:X13  in
P5  G$1:X27  in
P6  G$1:X10  in
P7  G$1:X25  in
P8  G$1:X22  in
P9  G$1:X20  in
P10  G$1:X19  in
P11  G$1:X2  in
P12  G$1:X16  in
P13  G$1:NC  nc
P14  G$1:NC  nc
P15  G$1:Y30  in
R1  P:GND  pwr
R2  G$1:X30  in
R3  G$1:X28  in
R4  G$1:X12  in
R5  G$1:X11  in
R6  G$1:X9  in
R7  G$1:X24  in
R8  G$1:X7  in
R9  G$1:X6  in
R10  G$1:X21  in
R11  G$1:X4  in
R12  G$1:X18  in
R13  G$1:X17  in
R14  G$1:X0  in
R15  P:GND  pwr

## Footprint G144-1 (pad centres in mm)
Grid Array
drill 0.813 round: A1 -17.78,17.78
drill 0.813 octagon: A2 -15.24,17.78; A3 -12.7,17.78; A4 -10.16,17.78; A5 -7.62,17.78; A6 -5.08,17.78; A7 -2.54,17.78; A8 0,17.78; A9 2.54,17.78; A10 5.08,17.78; A11 7.62,17.78; A12 10.16,17.78; A13 12.7,17.78; A14 15.24,17.78; A15 17.78,17.78; B1 -17.78,15.24; B2 -15.24,15.24; B3 -12.7,15.24; B4 -10.16,15.24; B5 -7.62,15.24; B6 -5.08,15.24; B7 -2.54,15.24; B8 0,15.24; B9 2.54,15.24; B10 5.08,15.24; B11 7.62,15.24; B12 10.16,15.24; B13 12.7,15.24; B14 15.24,15.24; B15 17.78,15.24; C1 -17.78,12.7; C2 -15.24,12.7; C3 -12.7,12.7; C4 -10.16,12.7; C5 -7.62,12.7; C6 -5.08,12.7; C7 -2.54,12.7; C8 0,12.7; C9 2.54,12.7; C10 5.08,12.7; C11 7.62,12.7; C12 10.16,12.7; C13 12.7,12.7; C14 15.24,12.7; C15 17.78,12.7; D1 -17.78,10.16; D2 -15.24,10.16; D3 -12.7,10.16; D13 12.7,10.16; D14 15.24,10.16; D15 17.78,10.16; E1 -17.78,7.62; E2 -15.24,7.62; E3 -12.7,7.62; E13 12.7,7.62; E14 15.24,7.62; E15 17.78,7.62; F1 -17.78,5.08; F2 -15.24,5.08; F3 -12.7,5.08; F13 12.7,5.08; F14 15.24,5.08; F15 17.78,5.08; G1 -17.78,2.54; G2 -15.24,2.54; G3 -12.7,2.54; G13 12.7,2.54; G14 15.24,2.54; G15 17.78,2.54; H1 -17.78,0; H2 -15.24,0; H3 -12.7,0; H13 12.7,0; H14 15.24,0; H15 17.78,0; J1 -17.78,-2.54; J2 -15.24,-2.54; J3 -12.7,-2.54; J13 12.7,-2.54; J14 15.24,-2.54; J15 17.78,-2.54; K1 -17.78,-5.08; K2 -15.24,-5.08; K3 -12.7,-5.08; K13 12.7,-5.08; K14 15.24,-5.08; K15 17.78,-5.08; L1 -17.78,-7.62; L2 -15.24,-7.62; L3 -12.7,-7.62; L13 12.7,-7.62; L14 15.24,-7.62; L15 17.78,-7.62; M1 -17.78,-10.16; M2 -15.24,-10.16; M3 -12.7,-10.16; M13 12.7,-10.16; M14 15.24,-10.16; M15 17.78,-10.16; N1 -17.78,-12.7; N2 -15.24,-12.7; N3 -12.7,-12.7; N4 -10.16,-12.7; N5 -7.62,-12.7; N6 -5.08,-12.7; N7 -2.54,-12.7; N8 0,-12.7; N9 2.54,-12.7; N10 5.08,-12.7; N11 7.62,-12.7; N12 10.16,-12.7; N13 12.7,-12.7; N14 15.24,-12.7; N15 17.78,-12.7; P1 -17.78,-15.24; P2 -15.24,-15.24; P3 -12.7,-15.24; P4 -10.16,-15.24; P5 -7.62,-15.24; P6 -5.08,-15.24; P7 -2.54,-15.24; P8 0,-15.24; P9 2.54,-15.24; P10 5.08,-15.24; P11 7.62,-15.24; P12 10.16,-15.24; P13 12.7,-15.24; P14 15.24,-15.24; P15 17.78,-15.24; R1 -17.78,-17.78; R2 -15.24,-17.78; R3 -12.7,-17.78; R4 -10.16,-17.78; R5 -7.62,-17.78; R6 -5.08,-17.78; R7 -2.54,-17.78; R8 0,-17.78; R9 2.54,-17.78; R10 5.08,-17.78; R11 7.62,-17.78; R12 10.16,-17.78; R13 12.7,-17.78; R14 15.24,-17.78; R15 17.78,-17.78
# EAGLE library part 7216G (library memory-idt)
MEMORY

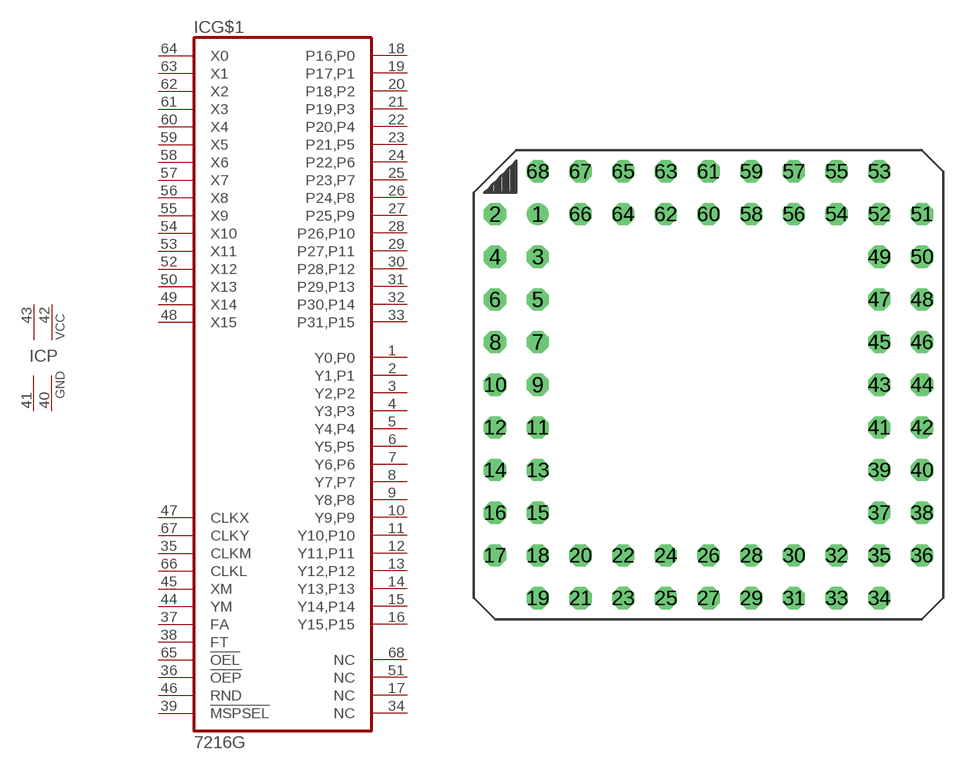
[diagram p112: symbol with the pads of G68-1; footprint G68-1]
Designator prefix IC; gates G$1=7216-68G P=2VCC2GND

## 7216G (OC_FARNELL: unknown; OC_NEWARK: unknown)  [G68-1]
1  G$1:Y0,P0
2  G$1:Y1,P1
3  G$1:Y2,P2
4  G$1:Y3,P3
5  G$1:Y4,P4
6  G$1:Y5,P5
7  G$1:Y6,P6
8  G$1:Y7,P7
9  G$1:Y8,P8
10  G$1:Y9,P9
11  G$1:Y10,P10
12  G$1:Y11,P11
13  G$1:Y12,P12
14  G$1:Y13,P13
15  G$1:Y14,P14
16  G$1:Y15,P15
17  G$1:NC  nc
18  G$1:P16,P0  out
19  G$1:P17,P1  out
20  G$1:P18,P2  out
21  G$1:P19,P3  out
22  G$1:P20,P4  out
23  G$1:P21,P5  out
24  G$1:P22,P6  out
25  G$1:P23,P7  out
26  G$1:P24,P8  out
27  G$1:P25,P9  out
28  G$1:P26,P10  out
29  G$1:P27,P11  out
30  G$1:P28,P12  out
31  G$1:P29,P13  out
32  G$1:P30,P14  out
33  G$1:P31,P15  out
34  G$1:NC  nc
35  G$1:CLKM  in
36  G$1:!OEP  in
37  G$1:FA  in
38  G$1:FT  in
39  G$1:!MSPSEL  in
40  P:GND  pwr
41  P:GND  pwr
42  P:VCC  pwr
43  P:VCC  pwr
44  G$1:YM  in
45  G$1:XM  in
46  G$1:RND  in
47  G$1:CLKX  in
48  G$1:X15  in
49  G$1:X14  in
50  G$1:X13  in
51  G$1:NC  nc
52  G$1:X12  in
53  G$1:X11  in
54  G$1:X10  in
55  G$1:X9  in
56  G$1:X8  in
57  G$1:X7  in
58  G$1:X6  in
59  G$1:X5  in
60  G$1:X4  in
61  G$1:X3  in
62  G$1:X2  in
63  G$1:X1  in
64  G$1:X0  in
65  G$1:!OEL  in
66  G$1:CLKL  in
67  G$1:CLKY  in
68  G$1:NC  nc

## Footprint G68-1 (pad centres in mm)
Grid Array
drill 0.813 round: 1 -10.16,10.16
drill 0.813 octagon: 2 -12.7,10.16; 3 -10.16,7.62; 4 -12.7,7.62; 5 -10.16,5.08; 6 -12.7,5.08; 7 -10.16,2.54; 8 -12.7,2.54; 9 -10.16,0; 10 -12.7,0; 11 -10.16,-2.54; 12 -12.7,-2.54; 13 -10.16,-5.08; 14 -12.7,-5.08; 15 -10.16,-7.62; 16 -12.7,-7.62; 17 -12.7,-10.16; 18 -10.16,-10.16; 19 -10.16,-12.7; 20 -7.62,-10.16; 21 -7.62,-12.7; 22 -5.08,-10.16; 23 -5.08,-12.7; 24 -2.54,-10.16; 25 -2.54,-12.7; 26 0,-10.16; 27 0,-12.7; 28 2.54,-10.16; 29 2.54,-12.7; 30 5.08,-10.16; 31 5.08,-12.7; 32 7.62,-10.16; 33 7.62,-12.7; 34 10.16,-12.7; 35 10.16,-10.16; 36 12.7,-10.16; 37 10.16,-7.62; 38 12.7,-7.62; 39 10.16,-5.08; 40 12.7,-5.08; 41 10.16,-2.54; 42 12.7,-2.54; 43 10.16,0; 44 12.7,0; 45 10.16,2.54; 46 12.7,2.54; 47 10.16,5.08; 48 12.7,5.08; 49 10.16,7.62; 50 12.7,7.62; 51 12.7,10.16; 52 10.16,10.16; 53 10.16,12.7; 54 7.62,10.16; 55 7.62,12.7; 56 5.08,10.16; 57 5.08,12.7; 58 2.54,10.16; 59 2.54,12.7; 60 0,10.16; 61 0,12.7; 62 -2.54,10.16; 63 -2.54,12.7; 64 -5.08,10.16; 65 -5.08,12.7; 66 -7.62,10.16; 67 -7.62,12.7; 68 -10.16,12.7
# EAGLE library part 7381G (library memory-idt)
MEMORY

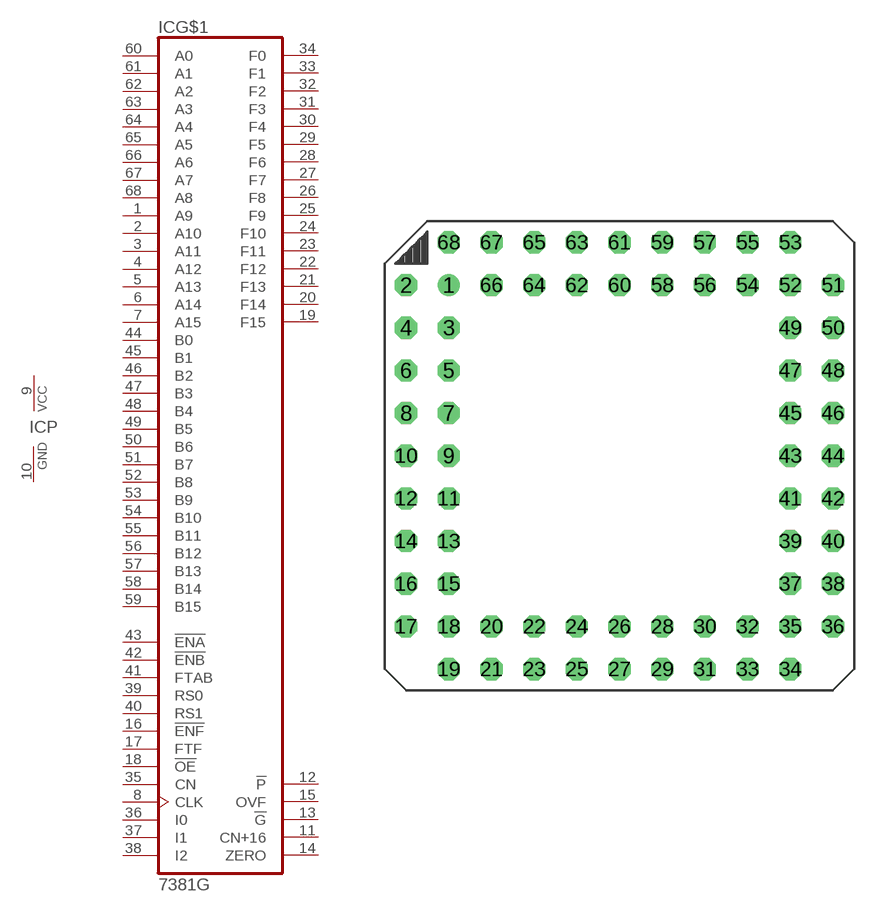
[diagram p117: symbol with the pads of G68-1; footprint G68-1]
Designator prefix IC; gates G$1=7381 P=VCCGND

## 7381G (OC_FARNELL: unknown; OC_NEWARK: unknown)  [G68-1]
1  G$1:A9  in
2  G$1:A10  in
3  G$1:A11  in
4  G$1:A12  in
5  G$1:A13  in
6  G$1:A14  in
7  G$1:A15  in
8  G$1:CLK  in
9  P:VCC  pwr
10  P:GND  pwr
11  G$1:CN+16  out
12  G$1:!P  out
13  G$1:!G  out
14  G$1:ZERO  out
15  G$1:OVF  out
16  G$1:!ENF  in
17  G$1:FTF  in
18  G$1:!OE  in
19  G$1:F15  out
20  G$1:F14  out
21  G$1:F13  out
22  G$1:F12  out
23  G$1:F11  out
24  G$1:F10  out
25  G$1:F9  out
26  G$1:F8  out
27  G$1:F7  out
28  G$1:F6  out
29  G$1:F5  out
30  G$1:F4  out
31  G$1:F3  out
32  G$1:F2  out
33  G$1:F1  out
34  G$1:F0  out
35  G$1:CN  in
36  G$1:I0  in
37  G$1:I1  in
38  G$1:I2  in
39  G$1:RS0  in
40  G$1:RS1  in
41  G$1:FTAB  in
42  G$1:!ENB  in
43  G$1:!ENA  in
44  G$1:B0  in
45  G$1:B1  in
46  G$1:B2  in
47  G$1:B3  in
48  G$1:B4  in
49  G$1:B5  in
50  G$1:B6  in
51  G$1:B7  in
52  G$1:B8  in
53  G$1:B9  in
54  G$1:B10  in
55  G$1:B11  in
56  G$1:B12  in
57  G$1:B13  in
58  G$1:B14  in
59  G$1:B15  in
60  G$1:A0  in
61  G$1:A1  in
62  G$1:A2  in
63  G$1:A3  in
64  G$1:A4  in
65  G$1:A5  in
66  G$1:A6  in
67  G$1:A7  in
68  G$1:A8  in

## Footprint G68-1 (pad centres in mm)
Grid Array
drill 0.813 round: 1 -10.16,10.16
drill 0.813 octagon: 2 -12.7,10.16; 3 -10.16,7.62; 4 -12.7,7.62; 5 -10.16,5.08; 6 -12.7,5.08; 7 -10.16,2.54; 8 -12.7,2.54; 9 -10.16,0; 10 -12.7,0; 11 -10.16,-2.54; 12 -12.7,-2.54; 13 -10.16,-5.08; 14 -12.7,-5.08; 15 -10.16,-7.62; 16 -12.7,-7.62; 17 -12.7,-10.16; 18 -10.16,-10.16; 19 -10.16,-12.7; 20 -7.62,-10.16; 21 -7.62,-12.7; 22 -5.08,-10.16; 23 -5.08,-12.7; 24 -2.54,-10.16; 25 -2.54,-12.7; 26 0,-10.16; 27 0,-12.7; 28 2.54,-10.16; 29 2.54,-12.7; 30 5.08,-10.16; 31 5.08,-12.7; 32 7.62,-10.16; 33 7.62,-12.7; 34 10.16,-12.7; 35 10.16,-10.16; 36 12.7,-10.16; 37 10.16,-7.62; 38 12.7,-7.62; 39 10.16,-5.08; 40 12.7,-5.08; 41 10.16,-2.54; 42 12.7,-2.54; 43 10.16,0; 44 12.7,0; 45 10.16,2.54; 46 12.7,2.54; 47 10.16,5.08; 48 12.7,5.08; 49 10.16,7.62; 50 12.7,7.62; 51 12.7,10.16; 52 10.16,10.16; 53 10.16,12.7; 54 7.62,10.16; 55 7.62,12.7; 56 5.08,10.16; 57 5.08,12.7; 58 2.54,10.16; 59 2.54,12.7; 60 0,10.16; 61 0,12.7; 62 -2.54,10.16; 63 -2.54,12.7; 64 -5.08,10.16; 65 -5.08,12.7; 66 -7.62,10.16; 67 -7.62,12.7; 68 -10.16,12.7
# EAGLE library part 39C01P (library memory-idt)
MEMORY

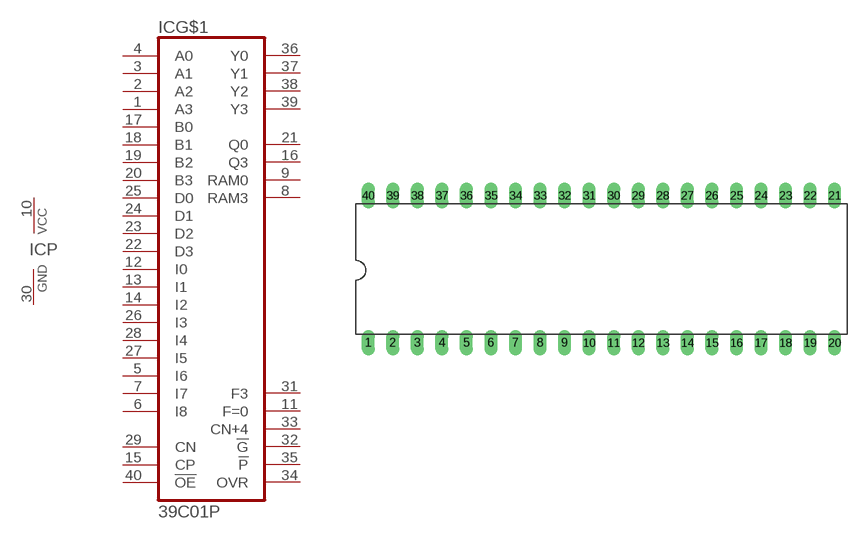
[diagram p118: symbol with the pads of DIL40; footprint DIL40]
Designator prefix IC; gates G$1=39C01 P=VCCGND

## 39C01P (OC_FARNELL: unknown; OC_NEWARK: unknown)  [DIL40]
1  G$1:A3  in
2  G$1:A2  in
3  G$1:A1  in
4  G$1:A0  in
5  G$1:I6  in
6  G$1:I8  in
7  G$1:I7  in
8  G$1:RAM3
9  G$1:RAM0
10  P:VCC  pwr
11  G$1:F=0  out
12  G$1:I0  in
13  G$1:I1  in
14  G$1:I2  in
15  G$1:CP  in
16  G$1:Q3
17  G$1:B0  in
18  G$1:B1  in
19  G$1:B2  in
20  G$1:B3  in
21  G$1:Q0
22  G$1:D3  in
23  G$1:D2  in
24  G$1:D1  in
25  G$1:D0  in
26  G$1:I3  in
27  G$1:I5  in
28  G$1:I4  in
29  G$1:CN  in
30  P:GND  pwr
31  G$1:F3  out
32  G$1:!G  out
33  G$1:CN+4  out
34  G$1:OVR  out
35  G$1:!P  out
36  G$1:Y0  out
37  G$1:Y1  out
38  G$1:Y2  out
39  G$1:Y3  out
40  G$1:!OE  in

## Footprint DIL40 (pad centres in mm)
Dual In Line Package
drill 0.813 long: 1 -24.13,-7.62; 2 -21.59,-7.62; 3 -19.05,-7.62; 4 -16.51,-7.62; 5 -13.97,-7.62; 6 -11.43,-7.62; 7 -8.89,-7.62; 8 -6.35,-7.62; 9 -3.81,-7.62; 10 -1.27,-7.62; 11 1.27,-7.62; 12 3.81,-7.62; 13 6.35,-7.62; 14 8.89,-7.62; 15 11.43,-7.62; 16 13.97,-7.62; 17 16.51,-7.62; 18 19.05,-7.62; 19 21.59,-7.62; 20 24.13,-7.62; 21 24.13,7.62; 22 21.59,7.62; 23 19.05,7.62; 24 16.51,7.62; 25 13.97,7.62; 26 11.43,7.62; 27 8.89,7.62; 28 6.35,7.62; 29 3.81,7.62; 30 1.27,7.62; 31 -1.27,7.62; 32 -3.81,7.62; 33 -6.35,7.62; 34 -8.89,7.62; 35 -11.43,7.62; 36 -13.97,7.62; 37 -16.51,7.62; 38 -19.05,7.62; 39 -21.59,7.62; 40 -24.13,7.62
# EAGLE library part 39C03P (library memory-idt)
MEMORY

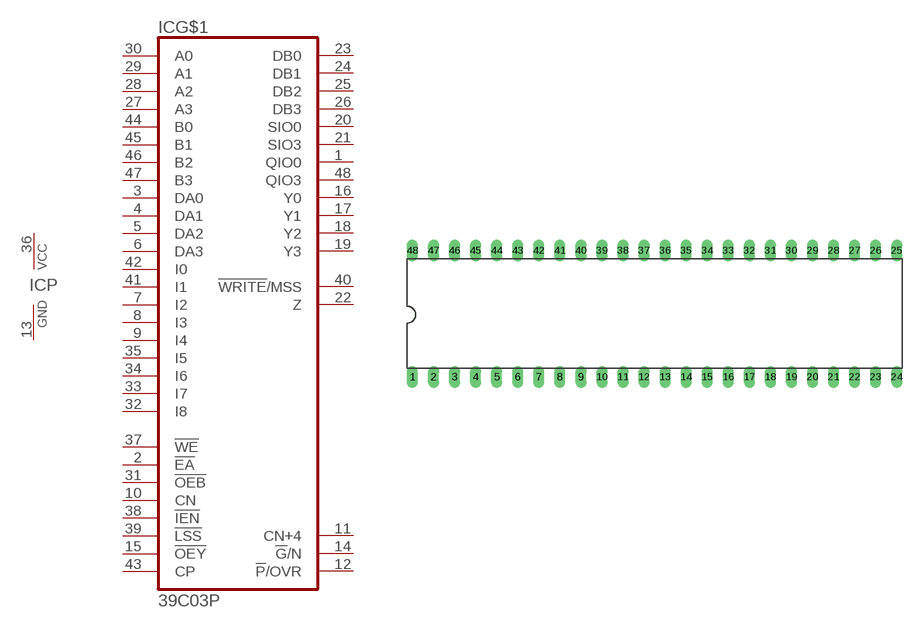
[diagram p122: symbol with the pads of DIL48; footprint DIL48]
Designator prefix IC; gates G$1=39C03 P=VCCGND

## 39C03P (OC_FARNELL: unknown; OC_NEWARK: unknown)  [DIL48]
1  G$1:QIO0
2  G$1:!EA  in
3  G$1:DA0  in
4  G$1:DA1  in
5  G$1:DA2  in
6  G$1:DA3  in
7  G$1:I2  in
8  G$1:I3  in
9  G$1:I4  in
10  G$1:CN  in
11  G$1:CN+4  out
12  G$1:!P!/OVR  out
13  P:GND  pwr
14  G$1:!G!/N  out
15  G$1:!OEY  in
16  G$1:Y0
17  G$1:Y1
18  G$1:Y2
19  G$1:Y3
20  G$1:SIO0
21  G$1:SIO3
22  G$1:Z
23  G$1:DB0
24  G$1:DB1
25  G$1:DB2
26  G$1:DB3
27  G$1:A3  in
28  G$1:A2  in
29  G$1:A1  in
30  G$1:A0  in
31  G$1:!OEB  in
32  G$1:I8  in
33  G$1:I7  in
34  G$1:I6  in
35  G$1:I5  in
36  P:VCC  pwr
37  G$1:!WE  in
38  G$1:!IEN  in
39  G$1:!LSS  in
40  G$1:!WRITE!/MSS
41  G$1:I1  in
42  G$1:I0  in
43  G$1:CP  in
44  G$1:B0  in
45  G$1:B1  in
46  G$1:B2  in
47  G$1:B3  in
48  G$1:QIO3

## Footprint DIL48 (pad centres in mm)
Dual In Line Package
drill 0.813 long: 1 -29.21,-7.62; 2 -26.67,-7.62; 3 -24.13,-7.62; 4 -21.59,-7.62; 5 -19.05,-7.62; 6 -16.51,-7.62; 7 -13.97,-7.62; 8 -11.43,-7.62; 9 -8.89,-7.62; 10 -6.35,-7.62; 11 -3.81,-7.62; 12 -1.27,-7.62; 13 1.27,-7.62; 14 3.81,-7.62; 15 6.35,-7.62; 16 8.89,-7.62; 17 11.43,-7.62; 18 13.97,-7.62; 19 16.51,-7.62; 20 19.05,-7.62; 21 21.59,-7.62; 22 24.13,-7.62; 23 26.67,-7.62; 24 29.21,-7.62; 25 29.21,7.62; 26 26.67,7.62; 27 24.13,7.62; 28 21.59,7.62; 29 19.05,7.62; 30 16.51,7.62; 31 13.97,7.62; 32 11.43,7.62; 33 8.89,7.62; 34 6.35,7.62; 35 3.81,7.62; 36 1.27,7.62; 37 -1.27,7.62; 38 -3.81,7.62; 39 -6.35,7.62; 40 -8.89,7.62; 41 -11.43,7.62; 42 -13.97,7.62; 43 -16.51,7.62; 44 -19.05,7.62; 45 -21.59,7.62; 46 -24.13,7.62; 47 -26.67,7.62; 48 -29.21,7.62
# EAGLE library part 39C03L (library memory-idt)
MEMORY

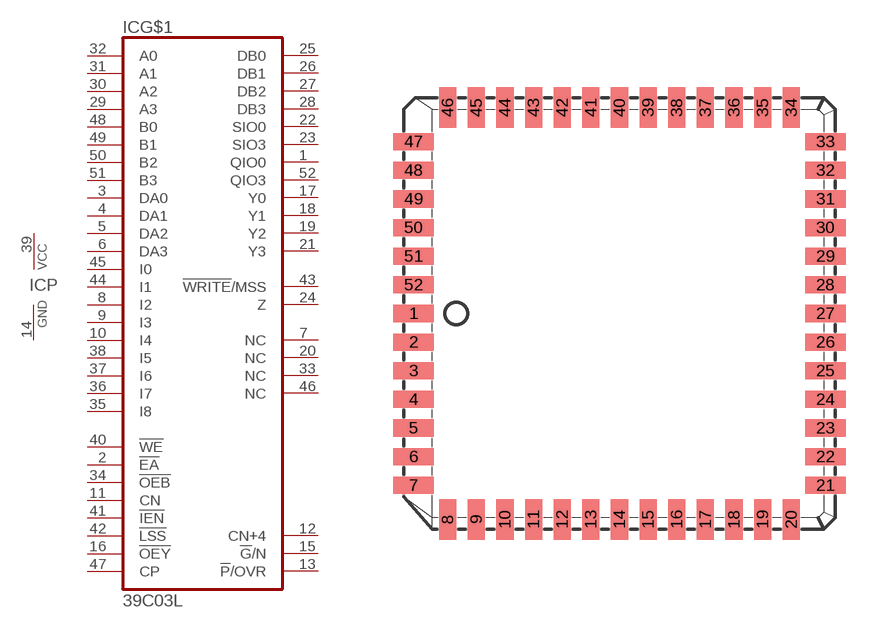
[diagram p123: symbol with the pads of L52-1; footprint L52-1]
Designator prefix IC; gates G$1=39C03L P=VCCGND

## 39C03L (OC_FARNELL: unknown; OC_NEWARK: unknown)  [L52-1]
1  G$1:QIO0
2  G$1:!EA  in
3  G$1:DA0  in
4  G$1:DA1  in
5  G$1:DA2  in
6  G$1:DA3  in
7  G$1:NC  nc
8  G$1:I2  in
9  G$1:I3  in
10  G$1:I4  in
11  G$1:CN  in
12  G$1:CN+4  out
13  G$1:!P!/OVR  out
14  P:GND  pwr
15  G$1:!G!/N  out
16  G$1:!OEY  in
17  G$1:Y0
18  G$1:Y1
19  G$1:Y2
20  G$1:NC  nc
21  G$1:Y3
22  G$1:SIO0
23  G$1:SIO3
24  G$1:Z
25  G$1:DB0
26  G$1:DB1
27  G$1:DB2
28  G$1:DB3
29  G$1:A3  in
30  G$1:A2  in
31  G$1:A1  in
32  G$1:A0  in
33  G$1:NC  nc
34  G$1:!OEB  in
35  G$1:I8  in
36  G$1:I7  in
37  G$1:I6  in
38  G$1:I5  in
39  P:VCC  pwr
40  G$1:!WE  in
41  G$1:!IEN  in
42  G$1:!LSS  in
43  G$1:!WRITE!/MSS
44  G$1:I1  in
45  G$1:I0  in
46  G$1:NC  nc
47  G$1:CP  in
48  G$1:B0  in
49  G$1:B1  in
50  G$1:B2  in
51  G$1:B3  in
52  G$1:QIO3

## Footprint L52-1 (pad centres in mm)
PLASTIC LEADED CHIP CARRIER square
smd 1.8 x 0.76: 1 -9.13,0; 2 -9.13,-1.27; 3 -9.13,-2.54; 4 -9.13,-3.81; 5 -9.13,-5.08; 6 -9.13,-6.35; 7 -9.13,-7.62; 21 9.13,-7.62; 22 9.13,-6.35; 23 9.13,-5.08; 24 9.13,-3.81; 25 9.13,-2.54; 26 9.13,-1.27; 27 9.13,0; 28 9.13,1.27; 29 9.13,2.54; 30 9.13,3.81; 31 9.13,5.08; 32 9.13,6.35; 33 9.13,7.62; 47 -9.13,7.62; 48 -9.13,6.35; 49 -9.13,5.08; 50 -9.13,3.81; 51 -9.13,2.54; 52 -9.13,1.27
smd 0.76 x 1.8: 8 -7.62,-9.13; 9 -6.35,-9.13; 10 -5.08,-9.13; 11 -3.81,-9.13; 12 -2.54,-9.13; 13 -1.27,-9.13; 14 0,-9.13; 15 1.27,-9.13; 16 2.54,-9.13; 17 3.81,-9.13; 18 5.08,-9.13; 19 6.35,-9.13; 20 7.62,-9.13; 34 7.62,9.13; 35 6.35,9.13; 36 5.08,9.13; 37 3.81,9.13; 38 2.54,9.13; 39 1.27,9.13; 40 0,9.13; 41 -1.27,9.13; 42 -2.54,9.13; 43 -3.81,9.13; 44 -5.08,9.13; 45 -6.35,9.13; 46 -7.62,9.13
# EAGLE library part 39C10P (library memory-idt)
MEMORY

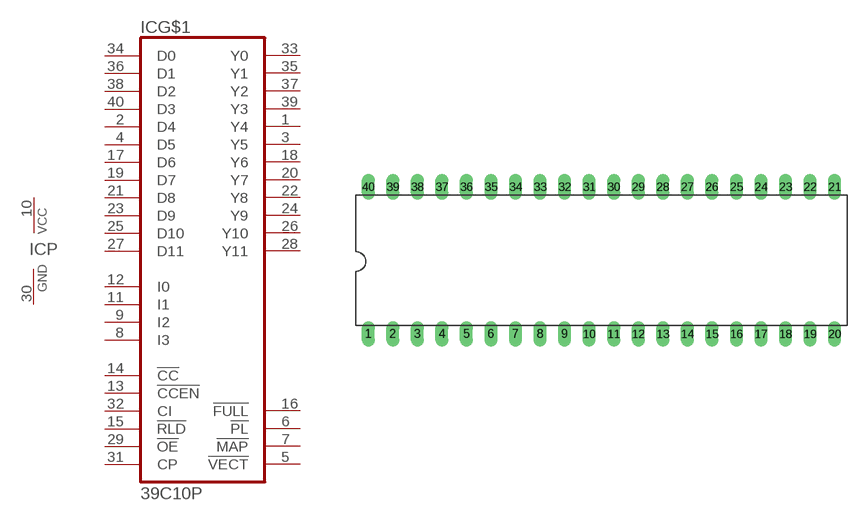
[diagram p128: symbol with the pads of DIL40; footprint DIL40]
Designator prefix IC; gates G$1=39C10P P=VCCGND

## 39C10P (OC_FARNELL: unknown; OC_NEWARK: unknown)  [DIL40]
1  G$1:Y4  out
2  G$1:D4  in
3  G$1:Y5  out
4  G$1:D5  in
5  G$1:!VECT  out
6  G$1:!PL  out
7  G$1:!MAP  out
8  G$1:I3  in
9  G$1:I2  in
10  P:VCC  pwr
11  G$1:I1  in
12  G$1:I0  in
13  G$1:!CCEN  in
14  G$1:!CC  in
15  G$1:!RLD  in
16  G$1:!FULL  out
17  G$1:D6  in
18  G$1:Y6  out
19  G$1:D7  in
20  G$1:Y7  out
21  G$1:D8  in
22  G$1:Y8  out
23  G$1:D9  in
24  G$1:Y9  out
25  G$1:D10  in
26  G$1:Y10  out
27  G$1:D11  in
28  G$1:Y11  out
29  G$1:!OE  in
30  P:GND  pwr
31  G$1:CP  in
32  G$1:CI  in
33  G$1:Y0  out
34  G$1:D0  in
35  G$1:Y1  out
36  G$1:D1  in
37  G$1:Y2  out
38  G$1:D2  in
39  G$1:Y3  out
40  G$1:D3  in

## Footprint DIL40 (pad centres in mm)
Dual In Line Package
drill 0.813 long: 1 -24.13,-7.62; 2 -21.59,-7.62; 3 -19.05,-7.62; 4 -16.51,-7.62; 5 -13.97,-7.62; 6 -11.43,-7.62; 7 -8.89,-7.62; 8 -6.35,-7.62; 9 -3.81,-7.62; 10 -1.27,-7.62; 11 1.27,-7.62; 12 3.81,-7.62; 13 6.35,-7.62; 14 8.89,-7.62; 15 11.43,-7.62; 16 13.97,-7.62; 17 16.51,-7.62; 18 19.05,-7.62; 19 21.59,-7.62; 20 24.13,-7.62; 21 24.13,7.62; 22 21.59,7.62; 23 19.05,7.62; 24 16.51,7.62; 25 13.97,7.62; 26 11.43,7.62; 27 8.89,7.62; 28 6.35,7.62; 29 3.81,7.62; 30 1.27,7.62; 31 -1.27,7.62; 32 -3.81,7.62; 33 -6.35,7.62; 34 -8.89,7.62; 35 -11.43,7.62; 36 -13.97,7.62; 37 -16.51,7.62; 38 -19.05,7.62; 39 -21.59,7.62; 40 -24.13,7.62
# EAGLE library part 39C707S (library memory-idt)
MEMORY

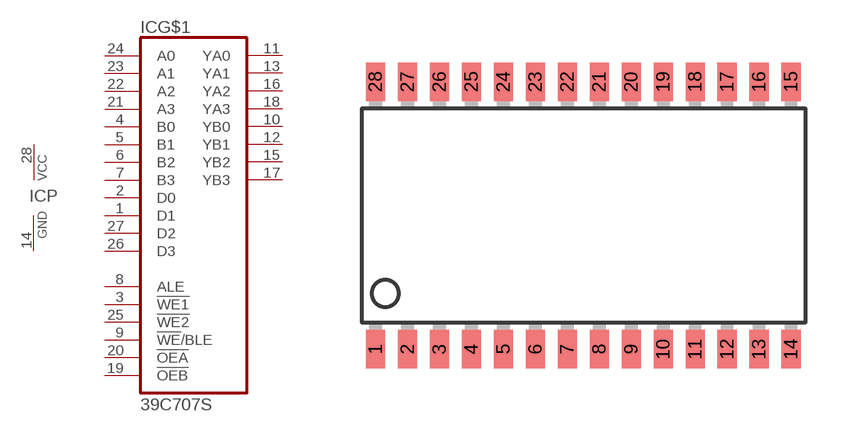
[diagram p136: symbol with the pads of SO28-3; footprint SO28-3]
Designator prefix IC; gates G$1=39C707 P=VCCGND

## 39C707S (OC_FARNELL: unknown; OC_NEWARK: unknown)  [SO28-3]
1  G$1:D1  in
2  G$1:D0  in
3  G$1:!WE1  in
4  G$1:B0  in
5  G$1:B1  in
6  G$1:B2  in
7  G$1:B3  in
8  G$1:ALE  in
9  G$1:!WE!/BLE  in
10  G$1:YB0  out
11  G$1:YA0  out
12  G$1:YB1  out
13  G$1:YA1  out
14  P:GND  pwr
15  G$1:YB2  out
16  G$1:YA2  out
17  G$1:YB3  out
18  G$1:YA3  out
19  G$1:!OEB  in
20  G$1:!OEA  in
21  G$1:A3  in
22  G$1:A2  in
23  G$1:A1  in
24  G$1:A0  in
25  G$1:!WE2  in
26  G$1:D3  in
27  G$1:D2  in
28  P:VCC  pwr

## Footprint SO28-3 (pad centres in mm)
Small Outline Package
smd 0.762 x 1.524: 1 -8.255,-5.315; 2 -6.985,-5.315; 3 -5.715,-5.315; 4 -4.445,-5.315; 5 -3.175,-5.315; 6 -1.905,-5.315; 7 -0.635,-5.315; 8 0.635,-5.315; 9 1.905,-5.315; 10 3.175,-5.315; 11 4.445,-5.315; 12 5.715,-5.315; 13 6.985,-5.315; 14 8.255,-5.315; 15 8.255,5.315; 16 6.985,5.315; 17 5.715,5.315; 18 4.445,5.315; 19 3.175,5.315; 20 1.905,5.315; 21 0.635,5.315; 22 -0.635,5.315; 23 -1.905,5.315; 24 -3.175,5.315; 25 -4.445,5.315; 26 -5.715,5.315; 27 -6.985,5.315; 28 -8.255,5.315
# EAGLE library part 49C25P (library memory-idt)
MEMORY

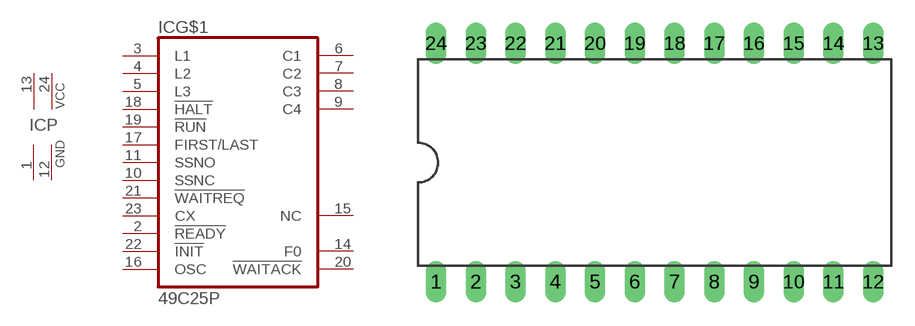
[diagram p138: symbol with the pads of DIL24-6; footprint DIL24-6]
Designator prefix IC; gates G$1=49C25 P=2VCC2GND

## 49C25P (OC_FARNELL: unknown; OC_NEWARK: unknown)  [DIL24-6]
1  P:GND  pwr
2  G$1:!READY  in
3  G$1:L1  in
4  G$1:L2  in
5  G$1:L3  in
6  G$1:C1  out
7  G$1:C2  out
8  G$1:C3  out
9  G$1:C4  out
10  G$1:SSNC  in
11  G$1:SSNO  in
12  P:GND  pwr
13  P:VCC  pwr
14  G$1:F0  out
15  G$1:NC  nc
16  G$1:OSC  in
17  G$1:FIRST/LAST  in
18  G$1:!HALT  in
19  G$1:!RUN  in
20  G$1:!WAITACK  out
21  G$1:!WAITREQ  in
22  G$1:!INIT  in
23  G$1:CX  in
24  P:VCC  pwr

## Footprint DIL24-6 (pad centres in mm)
Dual In Line Package 0.6 inch
drill 0.813 long: 1 -13.97,-7.62; 2 -11.43,-7.62; 3 -8.89,-7.62; 4 -6.35,-7.62; 5 -3.81,-7.62; 6 -1.27,-7.62; 7 1.27,-7.62; 8 3.81,-7.62; 9 6.35,-7.62; 10 8.89,-7.62; 11 11.43,-7.62; 12 13.97,-7.62; 13 13.97,7.62; 14 11.43,7.62; 15 8.89,7.62; 16 6.35,7.62; 17 3.81,7.62; 18 1.27,7.62; 19 -1.27,7.62; 20 -3.81,7.62; 21 -6.35,7.62; 22 -8.89,7.62; 23 -11.43,7.62; 24 -13.97,7.62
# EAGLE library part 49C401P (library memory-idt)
MEMORY

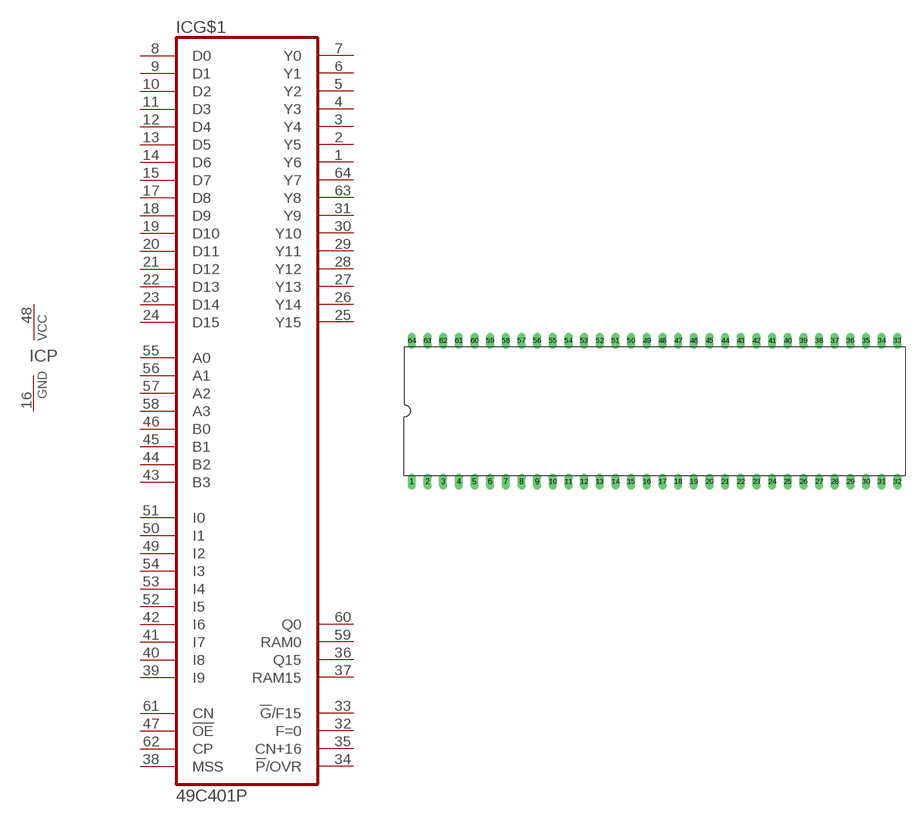
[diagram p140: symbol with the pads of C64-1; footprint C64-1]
Designator prefix IC; gates G$1=49C401 P=VCCGND

## 49C401P (OC_FARNELL: unknown; OC_NEWARK: unknown)  [C64-1]
1  G$1:Y6  out
2  G$1:Y5  out
3  G$1:Y4  out
4  G$1:Y3  out
5  G$1:Y2  out
6  G$1:Y1  out
7  G$1:Y0  out
8  G$1:D0  in
9  G$1:D1  in
10  G$1:D2  in
11  G$1:D3  in
12  G$1:D4  in
13  G$1:D5  in
14  G$1:D6  in
15  G$1:D7  in
16  P:GND  pwr
17  G$1:D8  in
18  G$1:D9  in
19  G$1:D10  in
20  G$1:D11  in
21  G$1:D12  in
22  G$1:D13  in
23  G$1:D14  in
24  G$1:D15  in
25  G$1:Y15  out
26  G$1:Y14  out
27  G$1:Y13  out
28  G$1:Y12  out
29  G$1:Y11  out
30  G$1:Y10  out
31  G$1:Y9  out
32  G$1:F=0  out
33  G$1:!G!/F15  out
34  G$1:!P!/OVR  out
35  G$1:CN+16  out
36  G$1:Q15
37  G$1:RAM15
38  G$1:MSS  in
39  G$1:I9  in
40  G$1:I8  in
41  G$1:I7  in
42  G$1:I6  in
43  G$1:B3  in
44  G$1:B2  in
45  G$1:B1  in
46  G$1:B0  in
47  G$1:!OE  in
48  P:VCC  pwr
49  G$1:I2  in
50  G$1:I1  in
51  G$1:I0  in
52  G$1:I5  in
53  G$1:I4  in
54  G$1:I3  in
55  G$1:A0  in
56  G$1:A1  in
57  G$1:A2  in
58  G$1:A3  in
59  G$1:RAM0
60  G$1:Q0
61  G$1:CN  in
62  G$1:CP  in
63  G$1:Y8  out
64  G$1:Y7  out

## Footprint C64-1 (pad centres in mm)
Dual In Line
drill 0.813 long: 1 -39.37,-11.43; 2 -36.83,-11.43; 3 -34.29,-11.43; 4 -31.75,-11.43; 5 -29.21,-11.43; 6 -26.67,-11.43; 7 -24.13,-11.43; 8 -21.59,-11.43; 9 -19.05,-11.43; 10 -16.51,-11.43; 11 -13.97,-11.43; 12 -11.43,-11.43; 13 -8.89,-11.43; 14 -6.35,-11.43; 15 -3.81,-11.43; 16 -1.27,-11.43; 17 1.27,-11.43; 18 3.81,-11.43; 19 6.35,-11.43; 20 8.89,-11.43; 21 11.43,-11.43; 22 13.97,-11.43; 23 16.51,-11.43; 24 19.05,-11.43; 25 21.59,-11.43; 26 24.13,-11.43; 27 26.67,-11.43; 28 29.21,-11.43; 29 31.75,-11.43; 30 34.29,-11.43; 31 36.83,-11.43; 32 39.37,-11.43; 33 39.37,11.43; 34 36.83,11.43; 35 34.29,11.43; 36 31.75,11.43; 37 29.21,11.43; 38 26.67,11.43; 39 24.13,11.43; 40 21.59,11.43; 41 19.05,11.43; 42 16.51,11.43; 43 13.97,11.43; 44 11.43,11.43; 45 8.89,11.43; 46 6.35,11.43; 47 3.81,11.43; 48 1.27,11.43; 49 -1.27,11.43; 50 -3.81,11.43; 51 -6.35,11.43; 52 -8.89,11.43; 53 -11.43,11.43; 54 -13.97,11.43; 55 -16.51,11.43; 56 -19.05,11.43; 57 -21.59,11.43; 58 -24.13,11.43; 59 -26.67,11.43; 60 -29.21,11.43; 61 -31.75,11.43; 62 -34.29,11.43; 63 -36.83,11.43; 64 -39.37,11.43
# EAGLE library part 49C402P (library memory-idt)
MEMORY

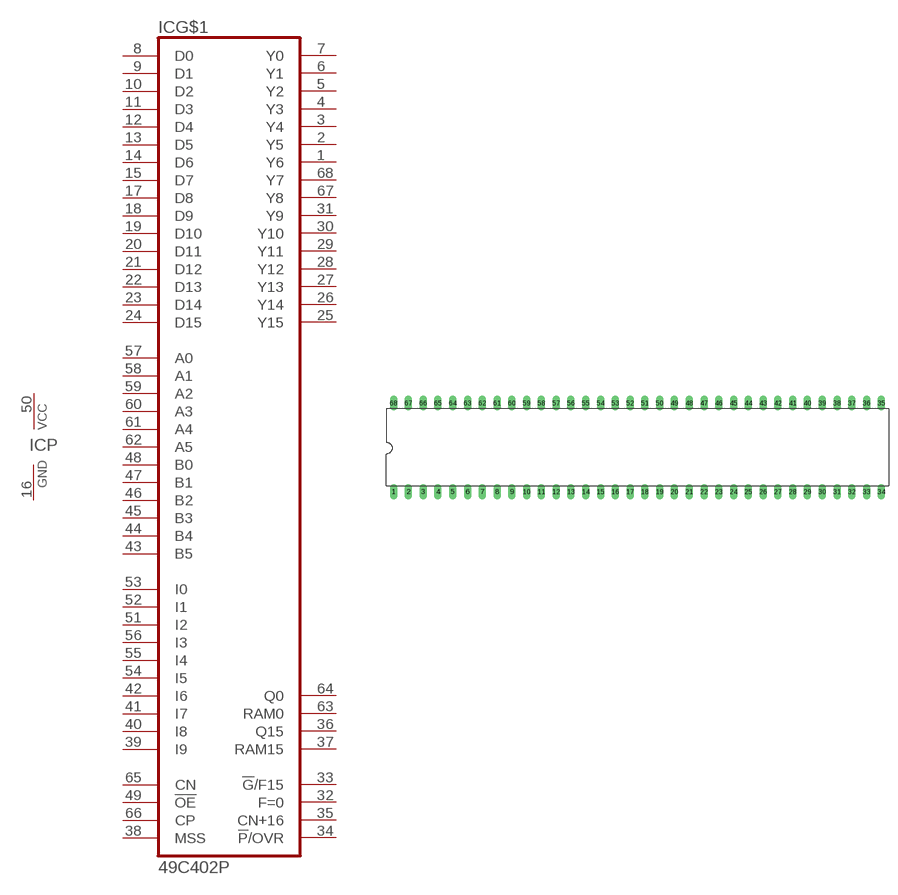
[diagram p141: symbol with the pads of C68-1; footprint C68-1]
Designator prefix IC; gates G$1=49C402 P=VCCGND

## 49C402P (OC_FARNELL: unknown; OC_NEWARK: unknown)  [C68-1]
1  G$1:Y6  out
2  G$1:Y5  out
3  G$1:Y4  out
4  G$1:Y3  out
5  G$1:Y2  out
6  G$1:Y1  out
7  G$1:Y0  out
8  G$1:D0  in
9  G$1:D1  in
10  G$1:D2  in
11  G$1:D3  in
12  G$1:D4  in
13  G$1:D5  in
14  G$1:D6  in
15  G$1:D7  in
16  P:GND  pwr
17  G$1:D8  in
18  G$1:D9  in
19  G$1:D10  in
20  G$1:D11  in
21  G$1:D12  in
22  G$1:D13  in
23  G$1:D14  in
24  G$1:D15  in
25  G$1:Y15  out
26  G$1:Y14  out
27  G$1:Y13  out
28  G$1:Y12  out
29  G$1:Y11  out
30  G$1:Y10  out
31  G$1:Y9  out
32  G$1:F=0  out
33  G$1:!G!/F15  out
34  G$1:!P!/OVR  out
35  G$1:CN+16  out
36  G$1:Q15
37  G$1:RAM15
38  G$1:MSS  in
39  G$1:I9  in
40  G$1:I8  in
41  G$1:I7  in
42  G$1:I6  in
43  G$1:B5  in
44  G$1:B4  in
45  G$1:B3  in
46  G$1:B2  in
47  G$1:B1  in
48  G$1:B0  in
49  G$1:!OE  in
50  P:VCC  pwr
51  G$1:I2  in
52  G$1:I1  in
53  G$1:I0  in
54  G$1:I5  in
55  G$1:I4  in
56  G$1:I3  in
57  G$1:A0  in
58  G$1:A1  in
59  G$1:A2  in
60  G$1:A3  in
61  G$1:A4  in
62  G$1:A5  in
63  G$1:RAM0
64  G$1:Q0
65  G$1:CN  in
66  G$1:CP  in
67  G$1:Y8  out
68  G$1:Y7  out

## Footprint C68-1 (pad centres in mm)
Dual In Line
drill 0.813 long: 1 -41.91,-7.62; 2 -39.37,-7.62; 3 -36.83,-7.62; 4 -34.29,-7.62; 5 -31.75,-7.62; 6 -29.21,-7.62; 7 -26.67,-7.62; 8 -24.13,-7.62; 9 -21.59,-7.62; 10 -19.05,-7.62; 11 -16.51,-7.62; 12 -13.97,-7.62; 13 -11.43,-7.62; 14 -8.89,-7.62; 15 -6.35,-7.62; 16 -3.81,-7.62; 17 -1.27,-7.62; 18 1.27,-7.62; 19 3.81,-7.62; 20 6.35,-7.62; 21 8.89,-7.62; 22 11.43,-7.62; 23 13.97,-7.62; 24 16.51,-7.62; 25 19.05,-7.62; 26 21.59,-7.62; 27 24.13,-7.62; 28 26.67,-7.62; 29 29.21,-7.62; 30 31.75,-7.62; 31 34.29,-7.62; 32 36.83,-7.62; 33 39.37,-7.62; 34 41.91,-7.62; 35 41.91,7.62; 36 39.37,7.62; 37 36.83,7.62; 38 34.29,7.62; 39 31.75,7.62; 40 29.21,7.62; 41 26.67,7.62; 42 24.13,7.62; 43 21.59,7.62; 44 19.05,7.62; 45 16.51,7.62; 46 13.97,7.62; 47 11.43,7.62; 48 8.89,7.62; 49 6.35,7.62; 50 3.81,7.62; 51 1.27,7.62; 52 -1.27,7.62; 53 -3.81,7.62; 54 -6.35,7.62; 55 -8.89,7.62; 56 -11.43,7.62; 57 -13.97,7.62; 58 -16.51,7.62; 59 -19.05,7.62; 60 -21.59,7.62; 61 -24.13,7.62; 62 -26.67,7.62; 63 -29.21,7.62; 64 -31.75,7.62; 65 -34.29,7.62; 66 -36.83,7.62; 67 -39.37,7.62; 68 -41.91,7.62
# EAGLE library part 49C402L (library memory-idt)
MEMORY

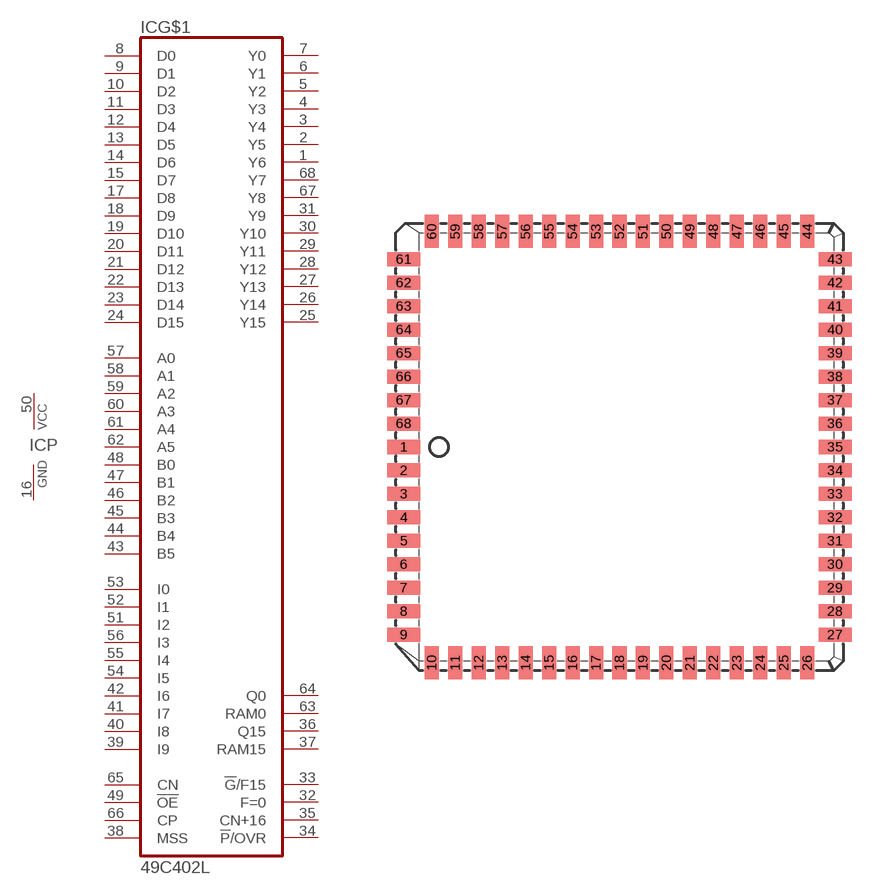
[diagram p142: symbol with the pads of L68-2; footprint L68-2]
Designator prefix IC; gates G$1=49C402 P=VCCGND

## 49C402L (OC_FARNELL: unknown; OC_NEWARK: unknown)  [L68-2]
1  G$1:Y6  out
2  G$1:Y5  out
3  G$1:Y4  out
4  G$1:Y3  out
5  G$1:Y2  out
6  G$1:Y1  out
7  G$1:Y0  out
8  G$1:D0  in
9  G$1:D1  in
10  G$1:D2  in
11  G$1:D3  in
12  G$1:D4  in
13  G$1:D5  in
14  G$1:D6  in
15  G$1:D7  in
16  P:GND  pwr
17  G$1:D8  in
18  G$1:D9  in
19  G$1:D10  in
20  G$1:D11  in
21  G$1:D12  in
22  G$1:D13  in
23  G$1:D14  in
24  G$1:D15  in
25  G$1:Y15  out
26  G$1:Y14  out
27  G$1:Y13  out
28  G$1:Y12  out
29  G$1:Y11  out
30  G$1:Y10  out
31  G$1:Y9  out
32  G$1:F=0  out
33  G$1:!G!/F15  out
34  G$1:!P!/OVR  out
35  G$1:CN+16  out
36  G$1:Q15
37  G$1:RAM15
38  G$1:MSS  in
39  G$1:I9  in
40  G$1:I8  in
41  G$1:I7  in
42  G$1:I6  in
43  G$1:B5  in
44  G$1:B4  in
45  G$1:B3  in
46  G$1:B2  in
47  G$1:B1  in
48  G$1:B0  in
49  G$1:!OE  in
50  P:VCC  pwr
51  G$1:I2  in
52  G$1:I1  in
53  G$1:I0  in
54  G$1:I5  in
55  G$1:I4  in
56  G$1:I3  in
57  G$1:A0  in
58  G$1:A1  in
59  G$1:A2  in
60  G$1:A3  in
61  G$1:A4  in
62  G$1:A5  in
63  G$1:RAM0
64  G$1:Q0
65  G$1:CN  in
66  G$1:CP  in
67  G$1:Y8  out
68  G$1:Y7  out

## Footprint L68-2 (pad centres in mm)
PLASTIC LEADED CHIP CARRIER square
smd 1.8 x 0.76: 1 -11.67,0; 2 -11.67,-1.27; 3 -11.67,-2.54; 4 -11.67,-3.81; 5 -11.67,-5.08; 6 -11.67,-6.35; 7 -11.67,-7.62; 8 -11.67,-8.89; 9 -11.67,-10.16; 27 11.67,-10.16; 28 11.67,-8.89; 29 11.67,-7.62; 30 11.67,-6.35; 31 11.67,-5.08; 32 11.67,-3.81; 33 11.67,-2.54; 34 11.67,-1.27; 35 11.67,0; 36 11.67,1.27; 37 11.67,2.54; 38 11.67,3.81; 39 11.67,5.08; 40 11.67,6.35; 41 11.67,7.62; 42 11.67,8.89; 43 11.67,10.16; 61 -11.67,10.16; 62 -11.67,8.89; 63 -11.67,7.62; 64 -11.67,6.35; 65 -11.67,5.08; 66 -11.67,3.81; 67 -11.67,2.54; 68 -11.67,1.27
smd 0.76 x 1.8: 10 -10.16,-11.67; 11 -8.89,-11.67; 12 -7.62,-11.67; 13 -6.35,-11.67; 14 -5.08,-11.67; 15 -3.81,-11.67; 16 -2.54,-11.67; 17 -1.27,-11.67; 18 0,-11.67; 19 1.27,-11.67; 20 2.54,-11.67; 21 3.81,-11.67; 22 5.08,-11.67; 23 6.35,-11.67; 24 7.62,-11.67; 25 8.89,-11.67; 26 10.16,-11.67; 44 10.16,11.67; 45 8.89,11.67; 46 7.62,11.67; 47 6.35,11.67; 48 5.08,11.67; 49 3.81,11.67; 50 2.54,11.67; 51 1.27,11.67; 52 0,11.67; 53 -1.27,11.67; 54 -2.54,11.67; 55 -3.81,11.67; 56 -5.08,11.67; 57 -6.35,11.67; 58 -7.62,11.67; 59 -8.89,11.67; 60 -10.16,11.67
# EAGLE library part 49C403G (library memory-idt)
MEMORY

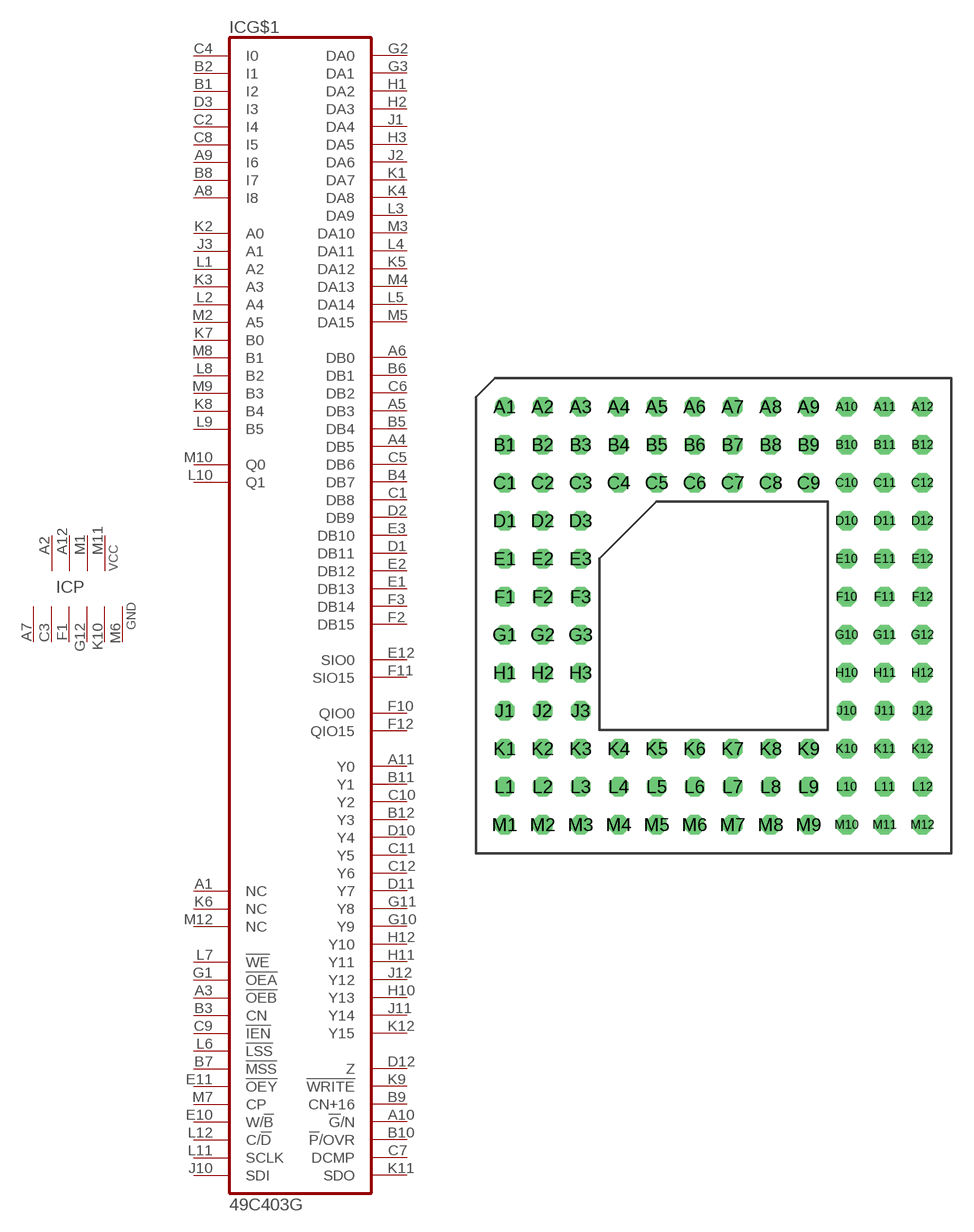
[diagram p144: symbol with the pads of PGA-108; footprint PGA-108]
Designator prefix IC; gates P=4VCC6GND G$1=49C403

## 49C403G (OC_FARNELL: unknown; OC_NEWARK: unknown)  [PGA-108]
A1  G$1:NC  nc
A2  P:VCC  pwr
A3  G$1:!OEB  in
A4  G$1:DB5
A5  G$1:DB3
A6  G$1:DB0
A7  P:GND  pwr
A8  G$1:I8  in
A9  G$1:I6  in
A10  G$1:!G!/N  out
A11  G$1:Y0
A12  P:VCC  pwr
B1  G$1:I2  in
B2  G$1:I1  in
B3  G$1:CN  in
B4  G$1:DB7
B5  G$1:DB4
B6  G$1:DB1
B7  G$1:!MSS  in
B8  G$1:I7  in
B9  G$1:CN+16  out
B10  G$1:!P!/OVR  out
B11  G$1:Y1
B12  G$1:Y3
C1  G$1:DB8
C2  G$1:I4  in
C3  P:GND  pwr
C4  G$1:I0  in
C5  G$1:DB6
C6  G$1:DB2
C7  G$1:DCMP  out
C8  G$1:I5  in
C9  G$1:!IEN  in
C10  G$1:Y2
C11  G$1:Y5
C12  G$1:Y6
D1  G$1:DB11
D2  G$1:DB9
D3  G$1:I3  in
D10  G$1:Y4
D11  G$1:Y7
D12  G$1:Z
E1  G$1:DB13
E2  G$1:DB12
E3  G$1:DB10
E10  G$1:W/!B  in
E11  G$1:!OEY  in
E12  G$1:SIO0
F1  P:GND  pwr
F2  G$1:DB15
F3  G$1:DB14
F10  G$1:QIO0
F11  G$1:SIO15
F12  G$1:QIO15
G1  G$1:!OEA  in
G2  G$1:DA0
G3  G$1:DA1
G10  G$1:Y9
G11  G$1:Y8
G12  P:GND  pwr
H1  G$1:DA2
H2  G$1:DA3
H3  G$1:DA5
H10  G$1:Y13
H11  G$1:Y11
H12  G$1:Y10
J1  G$1:DA4
J2  G$1:DA6
J3  G$1:A1  in
J10  G$1:SDI  in
J11  G$1:Y14
J12  G$1:Y12
K1  G$1:DA7
K2  G$1:A0  in
K3  G$1:A3  in
K4  G$1:DA8
K5  G$1:DA12
K6  G$1:NC  nc
K7  G$1:B0  in
K8  G$1:B4  in
K9  G$1:!WRITE  out
K10  P:GND  pwr
K11  G$1:SDO  out
K12  G$1:Y15
L1  G$1:A2  in
L2  G$1:A4  in
L3  G$1:DA9
L4  G$1:DA11
L5  G$1:DA14
L6  G$1:!LSS  in
L7  G$1:!WE  in
L8  G$1:B2  in
L9  G$1:B5  in
L10  G$1:Q1  in
L11  G$1:SCLK  in
L12  G$1:C/!D  in
M1  P:VCC  pwr
M2  G$1:A5  in
M3  G$1:DA10
M4  G$1:DA13
M5  G$1:DA15
M6  P:GND  pwr
M7  G$1:CP  in
M8  G$1:B1  in
M9  G$1:B3  in
M10  G$1:Q0  in
M11  P:VCC  pwr
M12  G$1:NC  nc

## Footprint PGA-108 (pad centres in mm)
Pin Grid Array
drill 0.813 round: A1 -13.97,13.97
drill 0.813 octagon: A2 -11.43,13.97; A3 -8.89,13.97; A4 -6.35,13.97; A5 -3.81,13.97; A6 -1.27,13.97; A7 1.27,13.97; A8 3.81,13.97; A9 6.35,13.97; A10 8.89,13.97; A11 11.43,13.97; A12 13.97,13.97; B1 -13.97,11.43; B2 -11.43,11.43; B3 -8.89,11.43; B4 -6.35,11.43; B5 -3.81,11.43; B6 -1.27,11.43; B7 1.27,11.43; B8 3.81,11.43; B9 6.35,11.43; B10 8.89,11.43; B11 11.43,11.43; B12 13.97,11.43; C1 -13.97,8.89; C2 -11.43,8.89; C3 -8.89,8.89; C4 -6.35,8.89; C5 -3.81,8.89; C6 -1.27,8.89; C7 1.27,8.89; C8 3.81,8.89; C9 6.35,8.89; C10 8.89,8.89; C11 11.43,8.89; C12 13.97,8.89; D1 -13.97,6.35; D2 -11.43,6.35; D3 -8.89,6.35; D10 8.89,6.35; D11 11.43,6.35; D12 13.97,6.35; E1 -13.97,3.81; E2 -11.43,3.81; E3 -8.89,3.81; E10 8.89,3.81; E11 11.43,3.81; E12 13.97,3.81; F1 -13.97,1.27; F2 -11.43,1.27; F3 -8.89,1.27; F10 8.89,1.27; F11 11.43,1.27; F12 13.97,1.27; G1 -13.97,-1.27; G2 -11.43,-1.27; G3 -8.89,-1.27; G10 8.89,-1.27; G11 11.43,-1.27; G12 13.97,-1.27; H1 -13.97,-3.81; H2 -11.43,-3.81; H3 -8.89,-3.81; H10 8.89,-3.81; H11 11.43,-3.81; H12 13.97,-3.81; J1 -13.97,-6.35; J2 -11.43,-6.35; J3 -8.89,-6.35; J10 8.89,-6.35; J11 11.43,-6.35; J12 13.97,-6.35; K1 -13.97,-8.89; K2 -11.43,-8.89; K3 -8.89,-8.89; K4 -6.35,-8.89; K5 -3.81,-8.89; K6 -1.27,-8.89; K7 1.27,-8.89; K8 3.81,-8.89; K9 6.35,-8.89; K10 8.89,-8.89; K11 11.43,-8.89; K12 13.97,-8.89; L1 -13.97,-11.43; L2 -11.43,-11.43; L3 -8.89,-11.43; L4 -6.35,-11.43; L5 -3.81,-11.43; L6 -1.27,-11.43; L7 1.27,-11.43; L8 3.81,-11.43; L9 6.35,-11.43; L10 8.89,-11.43; L11 11.43,-11.43; L12 13.97,-11.43; M1 -13.97,-13.97; M2 -11.43,-13.97; M3 -8.89,-13.97; M4 -6.35,-13.97; M5 -3.81,-13.97; M6 -1.27,-13.97; M7 1.27,-13.97; M8 3.81,-13.97; M9 6.35,-13.97; M10 8.89,-13.97; M11 11.43,-13.97; M12 13.97,-13.97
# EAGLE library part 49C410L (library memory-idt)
MEMORY

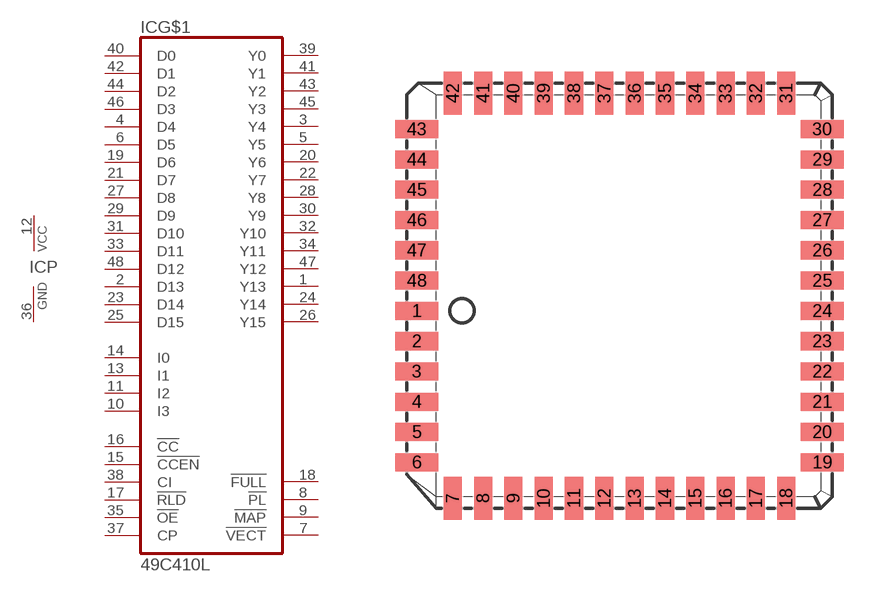
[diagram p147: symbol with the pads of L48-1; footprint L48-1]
Designator prefix IC; gates G$1=49C410 P=VCCGND

## 49C410L (OC_FARNELL: unknown; OC_NEWARK: unknown)  [L48-1]
1  G$1:Y13  out
2  G$1:D13  in
3  G$1:Y4  out
4  G$1:D4  in
5  G$1:Y5  out
6  G$1:D5  in
7  G$1:!VECT  out
8  G$1:!PL  out
9  G$1:!MAP  out
10  G$1:I3  in
11  G$1:I2  in
12  P:VCC  pwr
13  G$1:I1  in
14  G$1:I0  in
15  G$1:!CCEN  in
16  G$1:!CC  in
17  G$1:!RLD  in
18  G$1:!FULL  out
19  G$1:D6  in
20  G$1:Y6  out
21  G$1:D7  in
22  G$1:Y7  out
23  G$1:D14  in
24  G$1:Y14  out
25  G$1:D15  in
26  G$1:Y15  out
27  G$1:D8  in
28  G$1:Y8  out
29  G$1:D9  in
30  G$1:Y9  out
31  G$1:D10  in
32  G$1:Y10  out
33  G$1:D11  in
34  G$1:Y11  out
35  G$1:!OE  in
36  P:GND  pwr
37  G$1:CP  in
38  G$1:CI  in
39  G$1:Y0  out
40  G$1:D0  in
41  G$1:Y1  out
42  G$1:D1  in
43  G$1:Y2  out
44  G$1:D2  in
45  G$1:Y3  out
46  G$1:D3  in
47  G$1:Y12  out
48  G$1:D12  in

## Footprint L48-1 (pad centres in mm)
PLASTIC LEADED CHIP CARRIER square
smd 1.8 x 0.76: 1 -7.86,0; 2 -7.86,-1.27; 3 -7.86,-2.54; 4 -7.86,-3.81; 5 -7.86,-5.08; 6 -7.86,-6.35; 19 9.13,-6.35; 20 9.13,-5.08; 21 9.13,-3.81; 22 9.13,-2.54; 23 9.13,-1.27; 24 9.13,0; 25 9.13,1.27; 26 9.13,2.54; 27 9.13,3.81; 28 9.13,5.08; 29 9.13,6.35; 30 9.13,7.62; 43 -7.86,7.62; 44 -7.86,6.35; 45 -7.86,5.08; 46 -7.86,3.81; 47 -7.86,2.54; 48 -7.86,1.27
smd 0.76 x 1.8: 7 -6.35,-7.86; 8 -5.08,-7.86; 9 -3.81,-7.86; 10 -2.54,-7.86; 11 -1.27,-7.86; 12 0,-7.86; 13 1.27,-7.86; 14 2.54,-7.86; 15 3.81,-7.86; 16 5.08,-7.86; 17 6.35,-7.86; 18 7.62,-7.86; 31 7.62,9.13; 32 6.35,9.13; 33 5.08,9.13; 34 3.81,9.13; 35 2.54,9.13; 36 1.27,9.13; 37 0,9.13; 38 -1.27,9.13; 39 -2.54,9.13; 40 -3.81,9.13; 41 -5.08,9.13; 42 -6.35,9.13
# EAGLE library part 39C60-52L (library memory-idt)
MEMORY

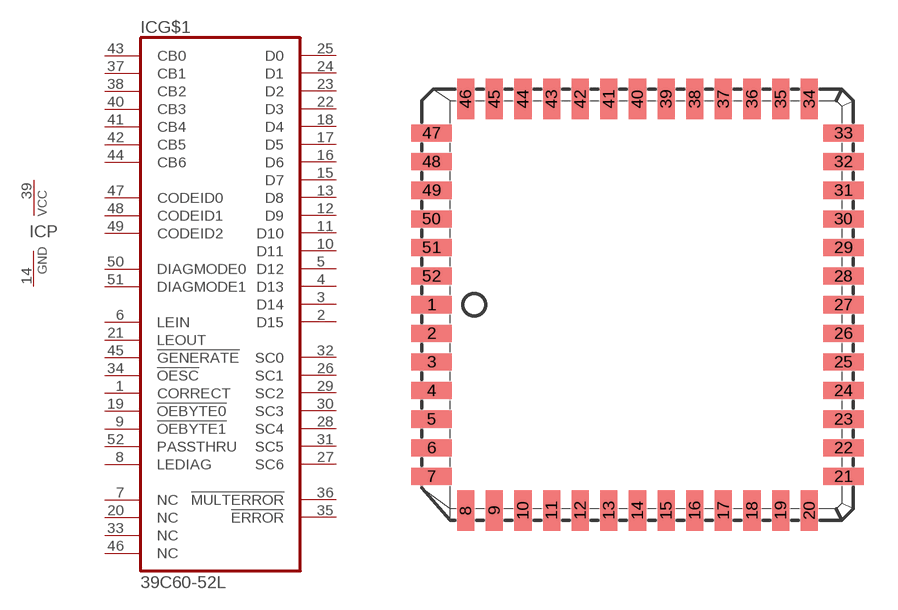
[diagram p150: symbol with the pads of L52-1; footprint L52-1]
Designator prefix IC; gates G$1=39C60-52 P=VCCGND

## 39C60-52L (OC_FARNELL: unknown; OC_NEWARK: unknown)  [L52-1]
1  G$1:CORRECT  in
2  G$1:D15
3  G$1:D14
4  G$1:D13
5  G$1:D12
6  G$1:LEIN  in
7  G$1:NC  nc
8  G$1:LEDIAG  in
9  G$1:!OEBYTE1  in
10  G$1:D11
11  G$1:D10
12  G$1:D9
13  G$1:D8
14  P:GND  pwr
15  G$1:D7
16  G$1:D6
17  G$1:D5
18  G$1:D4
19  G$1:!OEBYTE0  in
20  G$1:NC  nc
21  G$1:LEOUT  in
22  G$1:D3
23  G$1:D2
24  G$1:D1
25  G$1:D0
26  G$1:SC1  out
27  G$1:SC6  out
28  G$1:SC4  out
29  G$1:SC2  out
30  G$1:SC3  out
31  G$1:SC5  out
32  G$1:SC0  out
33  G$1:NC  nc
34  G$1:!OESC  in
35  G$1:!ERROR  out
36  G$1:!MULTERROR  out
37  G$1:CB1  in
38  G$1:CB2  in
39  P:VCC  pwr
40  G$1:CB3  in
41  G$1:CB4  in
42  G$1:CB5  in
43  G$1:CB0  in
44  G$1:CB6  in
45  G$1:!GENERATE  in
46  G$1:NC  nc
47  G$1:CODEID0  in
48  G$1:CODEID1  in
49  G$1:CODEID2  in
50  G$1:DIAGMODE0  in
51  G$1:DIAGMODE1  in
52  G$1:PASSTHRU  in

## Footprint L52-1 (pad centres in mm)
PLASTIC LEADED CHIP CARRIER square
smd 1.8 x 0.76: 1 -9.13,0; 2 -9.13,-1.27; 3 -9.13,-2.54; 4 -9.13,-3.81; 5 -9.13,-5.08; 6 -9.13,-6.35; 7 -9.13,-7.62; 21 9.13,-7.62; 22 9.13,-6.35; 23 9.13,-5.08; 24 9.13,-3.81; 25 9.13,-2.54; 26 9.13,-1.27; 27 9.13,0; 28 9.13,1.27; 29 9.13,2.54; 30 9.13,3.81; 31 9.13,5.08; 32 9.13,6.35; 33 9.13,7.62; 47 -9.13,7.62; 48 -9.13,6.35; 49 -9.13,5.08; 50 -9.13,3.81; 51 -9.13,2.54; 52 -9.13,1.27
smd 0.76 x 1.8: 8 -7.62,-9.13; 9 -6.35,-9.13; 10 -5.08,-9.13; 11 -3.81,-9.13; 12 -2.54,-9.13; 13 -1.27,-9.13; 14 0,-9.13; 15 1.27,-9.13; 16 2.54,-9.13; 17 3.81,-9.13; 18 5.08,-9.13; 19 6.35,-9.13; 20 7.62,-9.13; 34 7.62,9.13; 35 6.35,9.13; 36 5.08,9.13; 37 3.81,9.13; 38 2.54,9.13; 39 1.27,9.13; 40 0,9.13; 41 -1.27,9.13; 42 -2.54,9.13; 43 -3.81,9.13; 44 -5.08,9.13; 45 -6.35,9.13; 46 -7.62,9.13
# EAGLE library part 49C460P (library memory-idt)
MEMORY

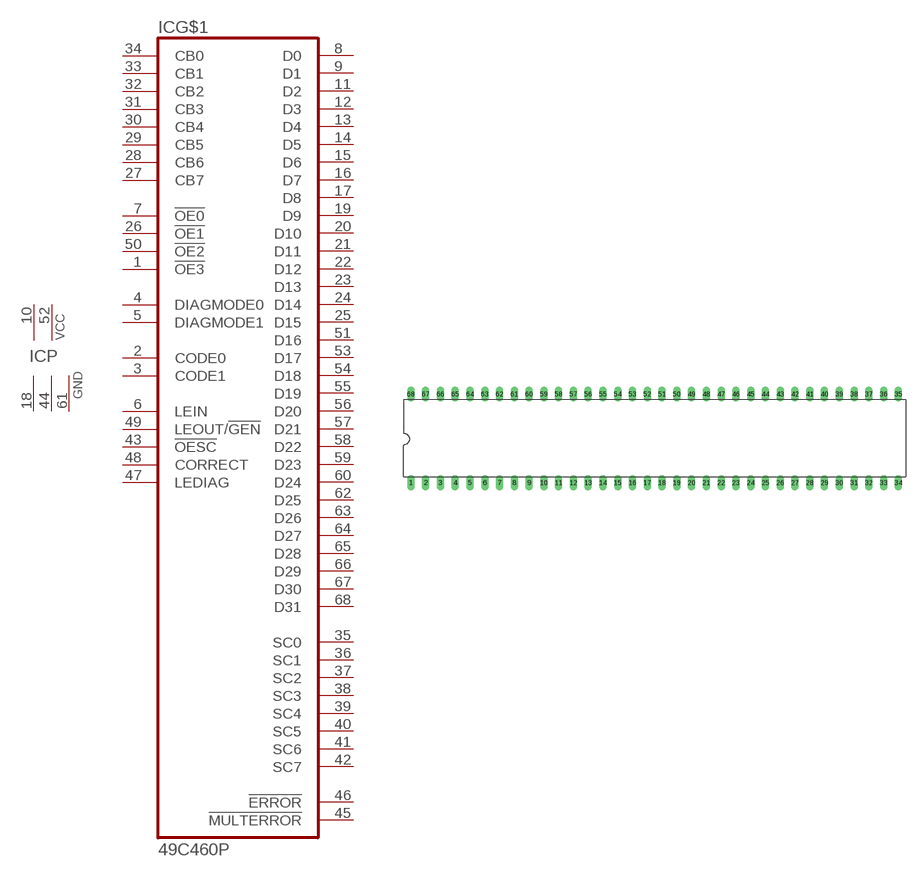
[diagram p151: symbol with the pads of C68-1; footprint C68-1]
Designator prefix IC; gates G$1=49C460 P=2VCC3GND

## 49C460P (OC_FARNELL: unknown; OC_NEWARK: unknown)  [C68-1]
1  G$1:!OE3  in
2  G$1:CODE0  in
3  G$1:CODE1  in
4  G$1:DIAGMODE0  in
5  G$1:DIAGMODE1  in
6  G$1:LEIN  in
7  G$1:!OE0  in
8  G$1:D0
9  G$1:D1
10  P:VCC  pwr
11  G$1:D2
12  G$1:D3
13  G$1:D4
14  G$1:D5
15  G$1:D6
16  G$1:D7
17  G$1:D8
18  P:GND  pwr
19  G$1:D9
20  G$1:D10
21  G$1:D11
22  G$1:D12
23  G$1:D13
24  G$1:D14
25  G$1:D15
26  G$1:!OE1  in
27  G$1:CB7  in
28  G$1:CB6  in
29  G$1:CB5  in
30  G$1:CB4  in
31  G$1:CB3  in
32  G$1:CB2  in
33  G$1:CB1  in
34  G$1:CB0  in
35  G$1:SC0  out
36  G$1:SC1  out
37  G$1:SC2  out
38  G$1:SC3  out
39  G$1:SC4  out
40  G$1:SC5  out
41  G$1:SC6  out
42  G$1:SC7  out
43  G$1:!OESC  in
44  P:GND  pwr
45  G$1:!MULTERROR  out
46  G$1:!ERROR  out
47  G$1:LEDIAG  in
48  G$1:CORRECT  in
49  G$1:LEOUT/!GEN  in
50  G$1:!OE2  in
51  G$1:D16
52  P:VCC  pwr
53  G$1:D17
54  G$1:D18
55  G$1:D19
56  G$1:D20
57  G$1:D21
58  G$1:D22
59  G$1:D23
60  G$1:D24
61  P:GND  pwr
62  G$1:D25
63  G$1:D26
64  G$1:D27
65  G$1:D28
66  G$1:D29
67  G$1:D30
68  G$1:D31

## Footprint C68-1 (pad centres in mm)
Dual In Line
drill 0.813 long: 1 -41.91,-7.62; 2 -39.37,-7.62; 3 -36.83,-7.62; 4 -34.29,-7.62; 5 -31.75,-7.62; 6 -29.21,-7.62; 7 -26.67,-7.62; 8 -24.13,-7.62; 9 -21.59,-7.62; 10 -19.05,-7.62; 11 -16.51,-7.62; 12 -13.97,-7.62; 13 -11.43,-7.62; 14 -8.89,-7.62; 15 -6.35,-7.62; 16 -3.81,-7.62; 17 -1.27,-7.62; 18 1.27,-7.62; 19 3.81,-7.62; 20 6.35,-7.62; 21 8.89,-7.62; 22 11.43,-7.62; 23 13.97,-7.62; 24 16.51,-7.62; 25 19.05,-7.62; 26 21.59,-7.62; 27 24.13,-7.62; 28 26.67,-7.62; 29 29.21,-7.62; 30 31.75,-7.62; 31 34.29,-7.62; 32 36.83,-7.62; 33 39.37,-7.62; 34 41.91,-7.62; 35 41.91,7.62; 36 39.37,7.62; 37 36.83,7.62; 38 34.29,7.62; 39 31.75,7.62; 40 29.21,7.62; 41 26.67,7.62; 42 24.13,7.62; 43 21.59,7.62; 44 19.05,7.62; 45 16.51,7.62; 46 13.97,7.62; 47 11.43,7.62; 48 8.89,7.62; 49 6.35,7.62; 50 3.81,7.62; 51 1.27,7.62; 52 -1.27,7.62; 53 -3.81,7.62; 54 -6.35,7.62; 55 -8.89,7.62; 56 -11.43,7.62; 57 -13.97,7.62; 58 -16.51,7.62; 59 -19.05,7.62; 60 -21.59,7.62; 61 -24.13,7.62; 62 -26.67,7.62; 63 -29.21,7.62; 64 -31.75,7.62; 65 -34.29,7.62; 66 -36.83,7.62; 67 -39.37,7.62; 68 -41.91,7.62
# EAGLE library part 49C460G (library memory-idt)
MEMORY

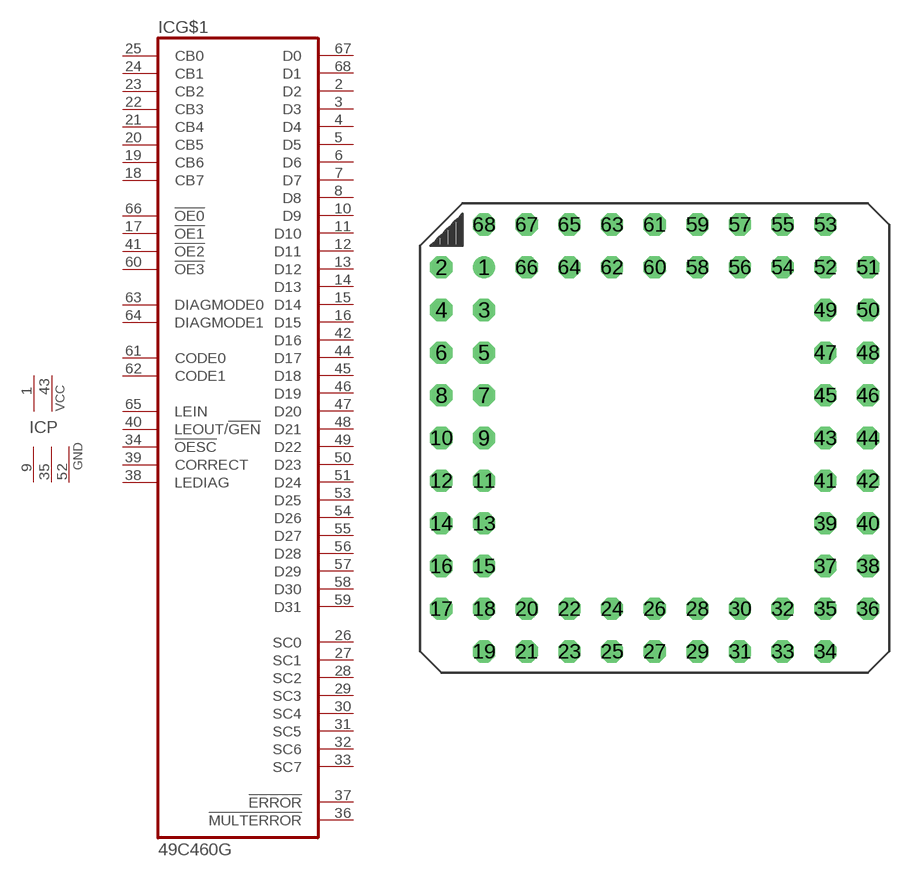
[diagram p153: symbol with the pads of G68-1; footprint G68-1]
Designator prefix IC; gates G$1=49C460 P=2VCC3GND

## 49C460G (OC_FARNELL: unknown; OC_NEWARK: unknown)  [G68-1]
1  P:VCC  pwr
2  G$1:D2
3  G$1:D3
4  G$1:D4
5  G$1:D5
6  G$1:D6
7  G$1:D7
8  G$1:D8
9  P:GND  pwr
10  G$1:D9
11  G$1:D10
12  G$1:D11
13  G$1:D12
14  G$1:D13
15  G$1:D14
16  G$1:D15
17  G$1:!OE1  in
18  G$1:CB7  in
19  G$1:CB6  in
20  G$1:CB5  in
21  G$1:CB4  in
22  G$1:CB3  in
23  G$1:CB2  in
24  G$1:CB1  in
25  G$1:CB0  in
26  G$1:SC0  out
27  G$1:SC1  out
28  G$1:SC2  out
29  G$1:SC3  out
30  G$1:SC4  out
31  G$1:SC5  out
32  G$1:SC6  out
33  G$1:SC7  out
34  G$1:!OESC  in
35  P:GND  pwr
36  G$1:!MULTERROR  out
37  G$1:!ERROR  out
38  G$1:LEDIAG  in
39  G$1:CORRECT  in
40  G$1:LEOUT/!GEN  in
41  G$1:!OE2  in
42  G$1:D16
43  P:VCC  pwr
44  G$1:D17
45  G$1:D18
46  G$1:D19
47  G$1:D20
48  G$1:D21
49  G$1:D22
50  G$1:D23
51  G$1:D24
52  P:GND  pwr
53  G$1:D25
54  G$1:D26
55  G$1:D27
56  G$1:D28
57  G$1:D29
58  G$1:D30
59  G$1:D31
60  G$1:!OE3  in
61  G$1:CODE0  in
62  G$1:CODE1  in
63  G$1:DIAGMODE0  in
64  G$1:DIAGMODE1  in
65  G$1:LEIN  in
66  G$1:!OE0  in
67  G$1:D0
68  G$1:D1

## Footprint G68-1 (pad centres in mm)
Grid Array
drill 0.813 round: 1 -10.16,10.16
drill 0.813 octagon: 2 -12.7,10.16; 3 -10.16,7.62; 4 -12.7,7.62; 5 -10.16,5.08; 6 -12.7,5.08; 7 -10.16,2.54; 8 -12.7,2.54; 9 -10.16,0; 10 -12.7,0; 11 -10.16,-2.54; 12 -12.7,-2.54; 13 -10.16,-5.08; 14 -12.7,-5.08; 15 -10.16,-7.62; 16 -12.7,-7.62; 17 -12.7,-10.16; 18 -10.16,-10.16; 19 -10.16,-12.7; 20 -7.62,-10.16; 21 -7.62,-12.7; 22 -5.08,-10.16; 23 -5.08,-12.7; 24 -2.54,-10.16; 25 -2.54,-12.7; 26 0,-10.16; 27 0,-12.7; 28 2.54,-10.16; 29 2.54,-12.7; 30 5.08,-10.16; 31 5.08,-12.7; 32 7.62,-10.16; 33 7.62,-12.7; 34 10.16,-12.7; 35 10.16,-10.16; 36 12.7,-10.16; 37 10.16,-7.62; 38 12.7,-7.62; 39 10.16,-5.08; 40 12.7,-5.08; 41 10.16,-2.54; 42 12.7,-2.54; 43 10.16,0; 44 12.7,0; 45 10.16,2.54; 46 12.7,2.54; 47 10.16,5.08; 48 12.7,5.08; 49 10.16,7.62; 50 12.7,7.62; 51 12.7,10.16; 52 10.16,10.16; 53 10.16,12.7; 54 7.62,10.16; 55 7.62,12.7; 56 5.08,10.16; 57 5.08,12.7; 58 2.54,10.16; 59 2.54,12.7; 60 0,10.16; 61 0,12.7; 62 -2.54,10.16; 63 -2.54,12.7; 64 -5.08,10.16; 65 -5.08,12.7; 66 -7.62,10.16; 67 -7.62,12.7; 68 -10.16,12.7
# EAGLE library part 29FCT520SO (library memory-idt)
MEMORY

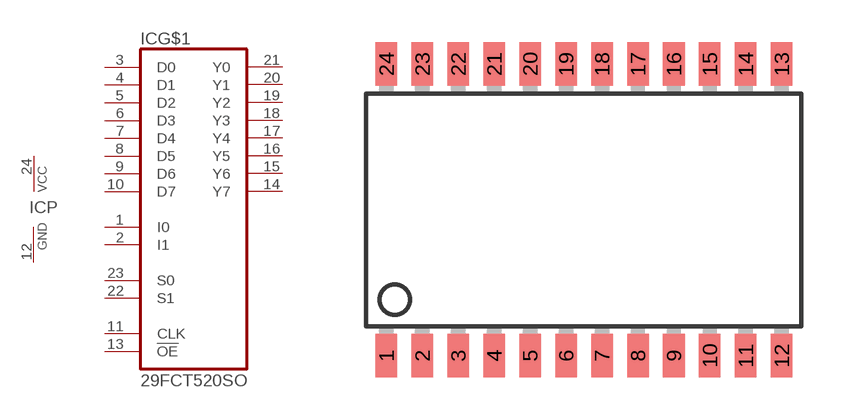
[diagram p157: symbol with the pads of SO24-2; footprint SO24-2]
Designator prefix IC; gates G$1=29FCT520 P=VCCGND

## 29FCT520SO (MPN: CY29FCT520ATSOC; OC_FARNELL: 1407564; OC_NEWARK: 34R7401)  [SO24-2]
1  G$1:I0  in
2  G$1:I1  in
3  G$1:D0  in
4  G$1:D1  in
5  G$1:D2  in
6  G$1:D3  in
7  G$1:D4  in
8  G$1:D5  in
9  G$1:D6  in
10  G$1:D7  in
11  G$1:CLK  in
12  P:GND  pwr
13  G$1:!OE  in
14  G$1:Y7
15  G$1:Y6
16  G$1:Y5
17  G$1:Y4
18  G$1:Y3
19  G$1:Y2
20  G$1:Y1
21  G$1:Y0
22  G$1:S1  in
23  G$1:S0  in
24  P:VCC  pwr

## Footprint SO24-2 (pad centres in mm)
Small Outline Package
smd 0.762 x 1.524: 1 -6.985,-5.156; 2 -5.715,-5.156; 3 -4.445,-5.156; 4 -3.175,-5.156; 5 -1.905,-5.156; 6 -0.635,-5.156; 7 0.635,-5.156; 8 1.905,-5.156; 9 3.175,-5.156; 10 4.445,-5.156; 11 5.715,-5.156; 12 6.985,-5.156; 13 6.985,5.156; 14 5.715,5.156; 15 4.445,5.156; 16 3.175,5.156; 17 1.905,5.156; 18 0.635,5.156; 19 -0.635,5.156; 20 -1.905,5.156; 21 -3.175,5.156; 22 -4.445,5.156; 23 -5.715,5.156; 24 -6.985,5.156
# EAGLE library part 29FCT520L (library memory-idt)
MEMORY

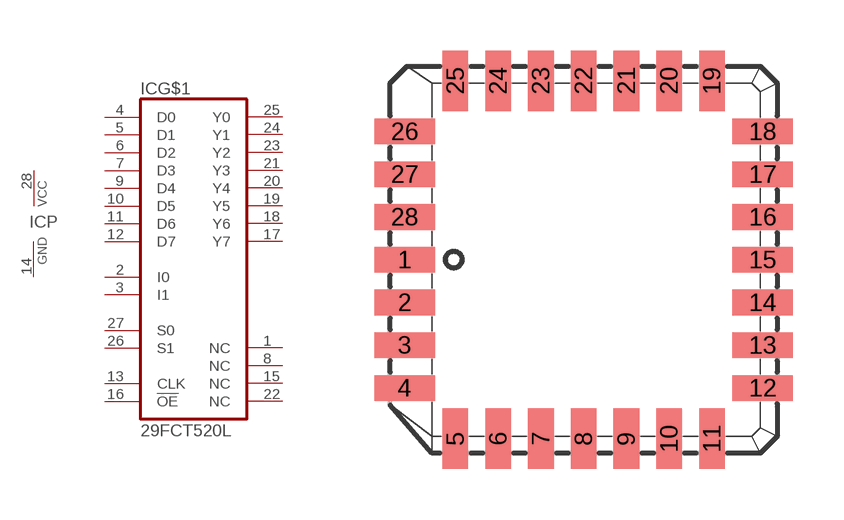
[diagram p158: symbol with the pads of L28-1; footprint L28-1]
Designator prefix IC; gates G$1=520L P=VCCGND

## 29FCT520L (OC_FARNELL: unknown; OC_NEWARK: unknown)  [L28-1]
1  G$1:NC  nc
2  G$1:I0  in
3  G$1:I1  in
4  G$1:D0  in
5  G$1:D1  in
6  G$1:D2  in
7  G$1:D3  in
8  G$1:NC  nc
9  G$1:D4  in
10  G$1:D5  in
11  G$1:D6  in
12  G$1:D7  in
13  G$1:CLK  in
14  P:GND  pwr
15  G$1:NC  nc
16  G$1:!OE  in
17  G$1:Y7
18  G$1:Y6
19  G$1:Y5
20  G$1:Y4
21  G$1:Y3
22  G$1:NC  nc
23  G$1:Y2
24  G$1:Y1
25  G$1:Y0
26  G$1:S1  in
27  G$1:S0  in
28  P:VCC  pwr

## Footprint L28-1 (pad centres in mm)
PLASTIC LEADED CHIP CARRIER square
smd 1.8 x 0.76: 1 -5.32,0; 2 -5.32,-1.27; 3 -5.32,-2.54; 4 -5.32,-3.81; 12 5.32,-3.81; 13 5.32,-2.54; 14 5.32,-1.27; 15 5.32,0; 16 5.32,1.27; 17 5.32,2.54; 18 5.32,3.81; 26 -5.32,3.81; 27 -5.32,2.54; 28 -5.32,1.27
smd 0.76 x 1.8: 5 -3.81,-5.32; 6 -2.54,-5.32; 7 -1.27,-5.32; 8 0,-5.32; 9 1.27,-5.32; 10 2.54,-5.32; 11 3.81,-5.32; 19 3.81,5.32; 20 2.54,5.32; 21 1.27,5.32; 22 0,5.32; 23 -1.27,5.32; 24 -2.54,5.32; 25 -3.81,5.32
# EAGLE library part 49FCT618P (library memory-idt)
MEMORY

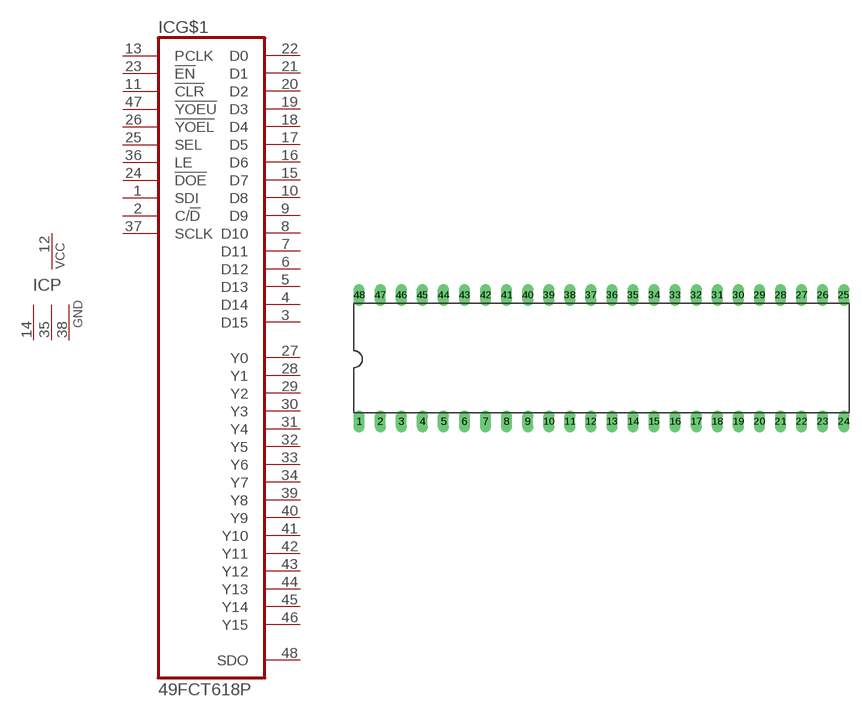
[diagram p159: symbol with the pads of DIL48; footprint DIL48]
Designator prefix IC; gates G$1=618 P=1VCC3GND

## 49FCT618P (OC_FARNELL: unknown; OC_NEWARK: unknown)  [DIL48]
1  G$1:SDI  in
2  G$1:C/!D  in
3  G$1:D15
4  G$1:D14
5  G$1:D13
6  G$1:D12
7  G$1:D11
8  G$1:D10
9  G$1:D9
10  G$1:D8
11  G$1:!CLR  in
12  P:VCC  pwr
13  G$1:PCLK  in
14  P:GND  pwr
15  G$1:D7
16  G$1:D6
17  G$1:D5
18  G$1:D4
19  G$1:D3
20  G$1:D2
21  G$1:D1
22  G$1:D0
23  G$1:!EN  in
24  G$1:!DOE  in
25  G$1:SEL  in
26  G$1:!YOEL  in
27  G$1:Y0
28  G$1:Y1
29  G$1:Y2
30  G$1:Y3
31  G$1:Y4
32  G$1:Y5
33  G$1:Y6
34  G$1:Y7
35  P:GND  pwr
36  G$1:LE  in
37  G$1:SCLK  in
38  P:GND  pwr
39  G$1:Y8
40  G$1:Y9
41  G$1:Y10
42  G$1:Y11
43  G$1:Y12
44  G$1:Y13
45  G$1:Y14
46  G$1:Y15
47  G$1:!YOEU  in
48  G$1:SDO  out

## Footprint DIL48 (pad centres in mm)
Dual In Line Package
drill 0.813 long: 1 -29.21,-7.62; 2 -26.67,-7.62; 3 -24.13,-7.62; 4 -21.59,-7.62; 5 -19.05,-7.62; 6 -16.51,-7.62; 7 -13.97,-7.62; 8 -11.43,-7.62; 9 -8.89,-7.62; 10 -6.35,-7.62; 11 -3.81,-7.62; 12 -1.27,-7.62; 13 1.27,-7.62; 14 3.81,-7.62; 15 6.35,-7.62; 16 8.89,-7.62; 17 11.43,-7.62; 18 13.97,-7.62; 19 16.51,-7.62; 20 19.05,-7.62; 21 21.59,-7.62; 22 24.13,-7.62; 23 26.67,-7.62; 24 29.21,-7.62; 25 29.21,7.62; 26 26.67,7.62; 27 24.13,7.62; 28 21.59,7.62; 29 19.05,7.62; 30 16.51,7.62; 31 13.97,7.62; 32 11.43,7.62; 33 8.89,7.62; 34 6.35,7.62; 35 3.81,7.62; 36 1.27,7.62; 37 -1.27,7.62; 38 -3.81,7.62; 39 -6.35,7.62; 40 -8.89,7.62; 41 -11.43,7.62; 42 -13.97,7.62; 43 -16.51,7.62; 44 -19.05,7.62; 45 -21.59,7.62; 46 -24.13,7.62; 47 -26.67,7.62; 48 -29.21,7.62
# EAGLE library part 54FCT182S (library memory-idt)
MEMORY

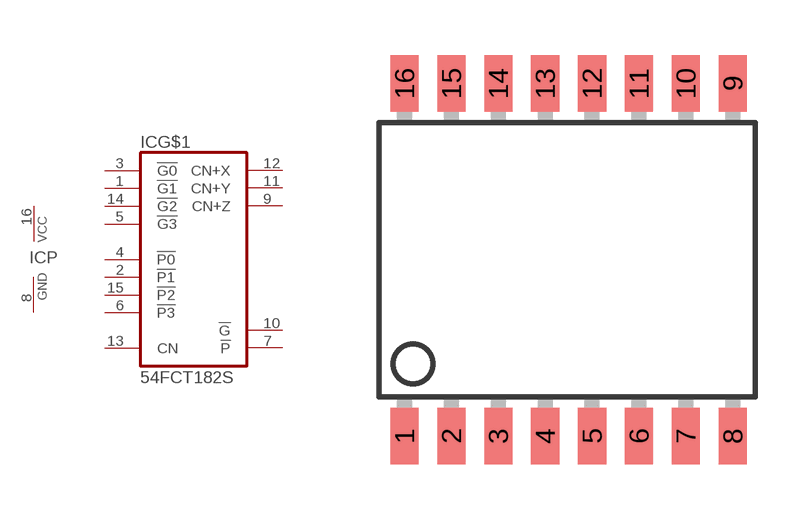
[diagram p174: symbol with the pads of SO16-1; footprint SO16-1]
Designator prefix IC; gates G$1=182 P=VCCGND

## 54FCT182S (OC_FARNELL: unknown; OC_NEWARK: unknown)  [SO16-1]
1  G$1:!G1  in
2  G$1:!P1  in
3  G$1:!G0  in
4  G$1:!P0  in
5  G$1:!G3  in
6  G$1:!P3  in
7  G$1:!P  out
8  P:GND  pwr
9  G$1:CN+Z  out
10  G$1:!G  out
11  G$1:CN+Y  out
12  G$1:CN+X  out
13  G$1:CN  in
14  G$1:!G2  in
15  G$1:!P2  in
16  P:VCC  pwr

## Footprint SO16-1 (pad centres in mm)
Small Outline Package
smd 0.762 x 1.524: 1 -4.445,-4.775; 2 -3.175,-4.775; 3 -1.905,-4.775; 4 -0.635,-4.775; 5 0.635,-4.775; 6 1.905,-4.775; 7 3.175,-4.775; 8 4.445,-4.775; 9 4.445,4.775; 10 3.175,4.775; 11 1.905,4.775; 12 0.635,4.775; 13 -0.635,4.775; 14 -1.905,4.775; 15 -3.175,4.775; 16 -4.445,4.775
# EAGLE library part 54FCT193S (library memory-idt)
MEMORY

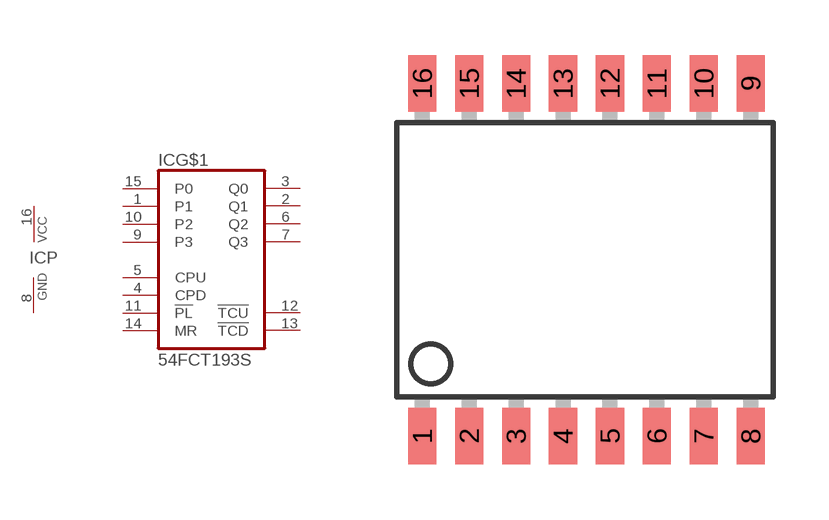
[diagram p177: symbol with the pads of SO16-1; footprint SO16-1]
Designator prefix IC; gates G$1=193 P=VCCGND

## 54FCT193S (OC_FARNELL: unknown; OC_NEWARK: unknown)  [SO16-1]
1  G$1:P1  in
2  G$1:Q1  out
3  G$1:Q0  out
4  G$1:CPD  in
5  G$1:CPU  in
6  G$1:Q2  out
7  G$1:Q3  out
8  P:GND  pwr
9  G$1:P3  in
10  G$1:P2  in
11  G$1:!PL  in
12  G$1:!TCU  out
13  G$1:!TCD  out
14  G$1:MR  in
15  G$1:P0  in
16  P:VCC  pwr

## Footprint SO16-1 (pad centres in mm)
Small Outline Package
smd 0.762 x 1.524: 1 -4.445,-4.775; 2 -3.175,-4.775; 3 -1.905,-4.775; 4 -0.635,-4.775; 5 0.635,-4.775; 6 1.905,-4.775; 7 3.175,-4.775; 8 4.445,-4.775; 9 4.445,4.775; 10 3.175,4.775; 11 1.905,4.775; 12 0.635,4.775; 13 -0.635,4.775; 14 -1.905,4.775; 15 -3.175,4.775; 16 -4.445,4.775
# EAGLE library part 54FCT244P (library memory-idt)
MEMORY

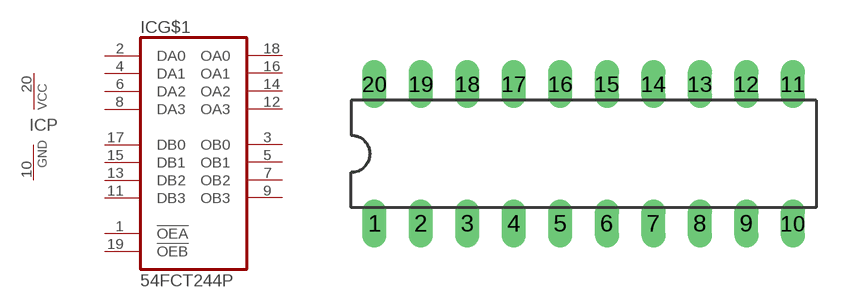
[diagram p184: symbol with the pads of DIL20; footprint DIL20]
Designator prefix IC; gates G$1=244 P=VCCGND

## 54FCT244P (MPN: CY54FCT244TDMB; OC_FARNELL: unknown; OC_NEWARK: 26R3270)  [DIL20]
1  G$1:!OEA  in
2  G$1:DA0  in
3  G$1:OB0  out
4  G$1:DA1  in
5  G$1:OB1  out
6  G$1:DA2  in
7  G$1:OB2  out
8  G$1:DA3  in
9  G$1:OB3  out
10  P:GND  pwr
11  G$1:DB3  in
12  G$1:OA3  out
13  G$1:DB2  in
14  G$1:OA2  out
15  G$1:DB1  in
16  G$1:OA1  out
17  G$1:DB0  in
18  G$1:OA0  out
19  G$1:!OEB  in
20  P:VCC  pwr

## Footprint DIL20 (pad centres in mm)
Dual In Line Package
drill 0.813 long: 1 -11.43,-3.81; 2 -8.89,-3.81; 3 -6.35,-3.81; 4 -3.81,-3.81; 5 -1.27,-3.81; 6 1.27,-3.81; 7 3.81,-3.81; 8 6.35,-3.81; 9 8.89,-3.81; 10 11.43,-3.81; 11 11.43,3.81; 12 8.89,3.81; 13 6.35,3.81; 14 3.81,3.81; 15 1.27,3.81; 16 -1.27,3.81; 17 -3.81,3.81; 18 -6.35,3.81; 19 -8.89,3.81; 20 -11.43,3.81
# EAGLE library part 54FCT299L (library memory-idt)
MEMORY

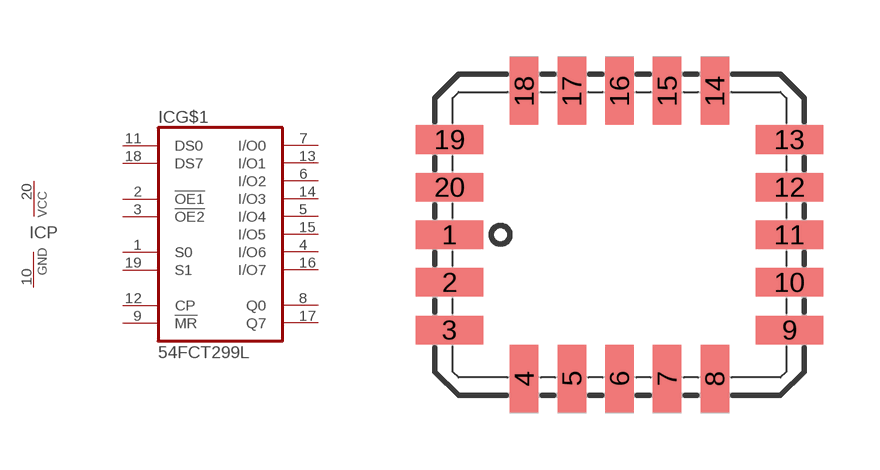
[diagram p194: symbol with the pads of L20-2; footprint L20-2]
Designator prefix IC; gates G$1=299 P=VCCGND

## 54FCT299L (OC_FARNELL: unknown; OC_NEWARK: unknown)  [L20-2]
1  G$1:S0
2  G$1:!OE1
3  G$1:!OE2
4  G$1:I/O6
5  G$1:I/O4
6  G$1:I/O2
7  G$1:I/O0
8  G$1:Q0  out
9  G$1:!MR
10  P:GND  pwr
11  G$1:DS0
12  G$1:CP
13  G$1:I/O1
14  G$1:I/O3
15  G$1:I/O5
16  G$1:I/O7
17  G$1:Q7  out
18  G$1:DS7
19  G$1:S1
20  P:VCC  pwr

## Footprint L20-2 (pad centres in mm)
PLASTIC LEADED CHIP CARRIER rectangle
smd 1.8 x 0.76: 1 -4.53,-0.635; 2 -4.53,-1.905; 3 -4.53,-3.175; 9 4.53,-3.175; 10 4.53,-1.905; 11 4.53,-0.635; 12 4.53,0.635; 13 4.53,1.905; 19 -4.53,1.905; 20 -4.53,0.635
smd 0.76 x 1.8: 4 -2.54,-4.47; 5 -1.27,-4.47; 6 0,-4.47; 7 1.27,-4.47; 8 2.54,-4.47; 14 2.54,3.2; 15 1.27,3.2; 16 0,3.2; 17 -1.27,3.2; 18 -2.54,3.2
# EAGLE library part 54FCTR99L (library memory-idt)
MEMORY

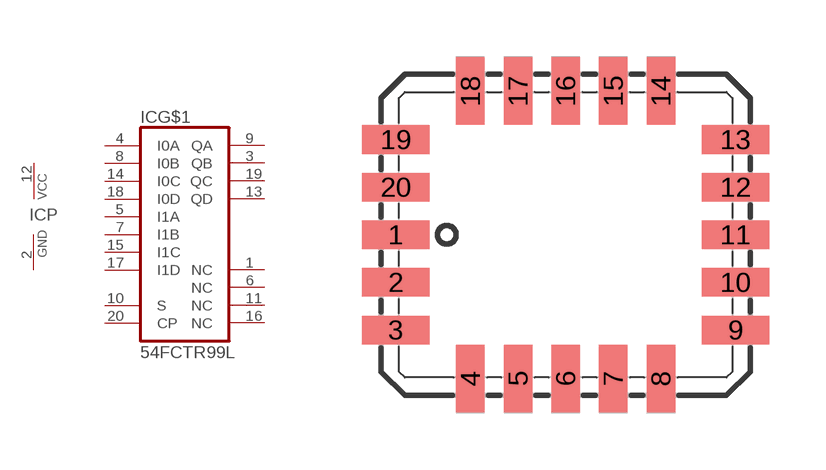
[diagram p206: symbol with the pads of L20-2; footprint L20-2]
Designator prefix IC; gates G$1=399L P=VCCGND

## 54FCTR99L (OC_FARNELL: unknown; OC_NEWARK: unknown)  [L20-2]
1  G$1:NC  nc
2  P:GND  pwr
3  G$1:QB  out
4  G$1:I0A  in
5  G$1:I1A  in
6  G$1:NC  nc
7  G$1:I1B  in
8  G$1:I0B  in
9  G$1:QA  out
10  G$1:S  in
11  G$1:NC  nc
12  P:VCC  pwr
13  G$1:QD  out
14  G$1:I0C  in
15  G$1:I1C  in
16  G$1:NC  nc
17  G$1:I1D  in
18  G$1:I0D  in
19  G$1:QC  out
20  G$1:CP  in

## Footprint L20-2 (pad centres in mm)
PLASTIC LEADED CHIP CARRIER rectangle
smd 1.8 x 0.76: 1 -4.53,-0.635; 2 -4.53,-1.905; 3 -4.53,-3.175; 9 4.53,-3.175; 10 4.53,-1.905; 11 4.53,-0.635; 12 4.53,0.635; 13 4.53,1.905; 19 -4.53,1.905; 20 -4.53,0.635
smd 0.76 x 1.8: 4 -2.54,-4.47; 5 -1.27,-4.47; 6 0,-4.47; 7 1.27,-4.47; 8 2.54,-4.47; 14 2.54,3.2; 15 1.27,3.2; 16 0,3.2; 17 -1.27,3.2; 18 -2.54,3.2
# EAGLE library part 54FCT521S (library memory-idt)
MEMORY

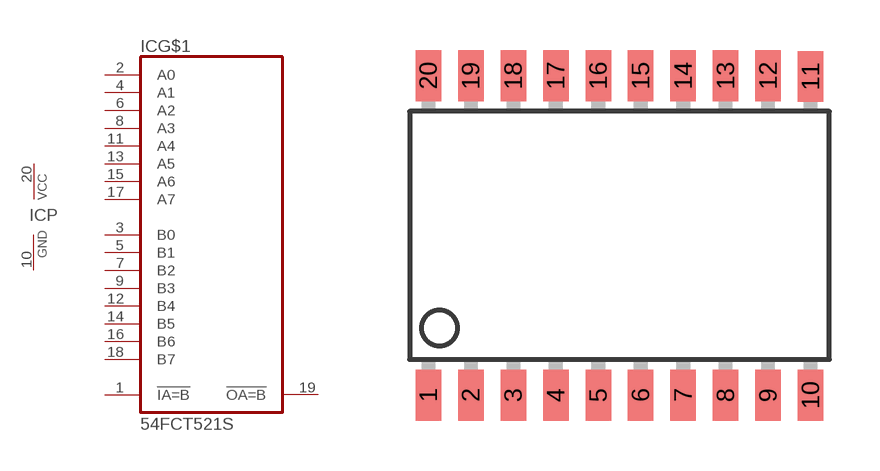
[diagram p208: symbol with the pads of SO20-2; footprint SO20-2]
Designator prefix IC; gates G$1=521 P=VCCGND

## 54FCT521S (OC_FARNELL: unknown; OC_NEWARK: unknown)  [SO20-2]
1  G$1:!IA=B  in
2  G$1:A0  in
3  G$1:B0  in
4  G$1:A1  in
5  G$1:B1  in
6  G$1:A2  in
7  G$1:B2  in
8  G$1:A3  in
9  G$1:B3  in
10  P:GND  pwr
11  G$1:A4  in
12  G$1:B4  in
13  G$1:A5  in
14  G$1:B5  in
15  G$1:A6  in
16  G$1:B6  in
17  G$1:A7  in
18  G$1:B7  in
19  G$1:!OA=B  out
20  P:VCC  pwr

## Footprint SO20-2 (pad centres in mm)
Small Outline Package
smd 0.762 x 1.524: 1 -5.715,-4.775; 2 -4.445,-4.775; 3 -3.175,-4.775; 4 -1.905,-4.775; 5 -0.635,-4.775; 6 0.635,-4.775; 7 1.905,-4.775; 8 3.175,-4.775; 9 4.445,-4.775; 10 5.715,-4.775; 11 5.715,4.75; 12 4.445,4.775; 13 3.175,4.775; 14 1.905,4.775; 15 0.635,4.775; 16 -0.635,4.775; 17 -1.905,4.775; 18 -3.175,4.775; 19 -4.445,4.775; 20 -5.715,4.775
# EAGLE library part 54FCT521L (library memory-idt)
MEMORY

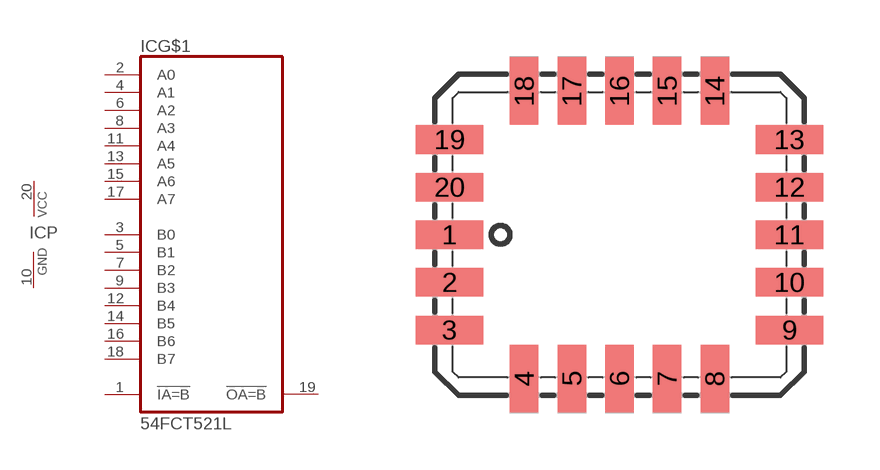
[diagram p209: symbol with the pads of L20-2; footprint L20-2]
Designator prefix IC; gates G$1=521 P=VCCGND

## 54FCT521L (OC_FARNELL: unknown; OC_NEWARK: unknown)  [L20-2]
1  G$1:!IA=B  in
2  G$1:A0  in
3  G$1:B0  in
4  G$1:A1  in
5  G$1:B1  in
6  G$1:A2  in
7  G$1:B2  in
8  G$1:A3  in
9  G$1:B3  in
10  P:GND  pwr
11  G$1:A4  in
12  G$1:B4  in
13  G$1:A5  in
14  G$1:B5  in
15  G$1:A6  in
16  G$1:B6  in
17  G$1:A7  in
18  G$1:B7  in
19  G$1:!OA=B  out
20  P:VCC  pwr

## Footprint L20-2 (pad centres in mm)
PLASTIC LEADED CHIP CARRIER rectangle
smd 1.8 x 0.76: 1 -4.53,-0.635; 2 -4.53,-1.905; 3 -4.53,-3.175; 9 4.53,-3.175; 10 4.53,-1.905; 11 4.53,-0.635; 12 4.53,0.635; 13 4.53,1.905; 19 -4.53,1.905; 20 -4.53,0.635
smd 0.76 x 1.8: 4 -2.54,-4.47; 5 -1.27,-4.47; 6 0,-4.47; 7 1.27,-4.47; 8 2.54,-4.47; 14 2.54,3.2; 15 1.27,3.2; 16 0,3.2; 17 -1.27,3.2; 18 -2.54,3.2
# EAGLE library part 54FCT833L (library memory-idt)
MEMORY

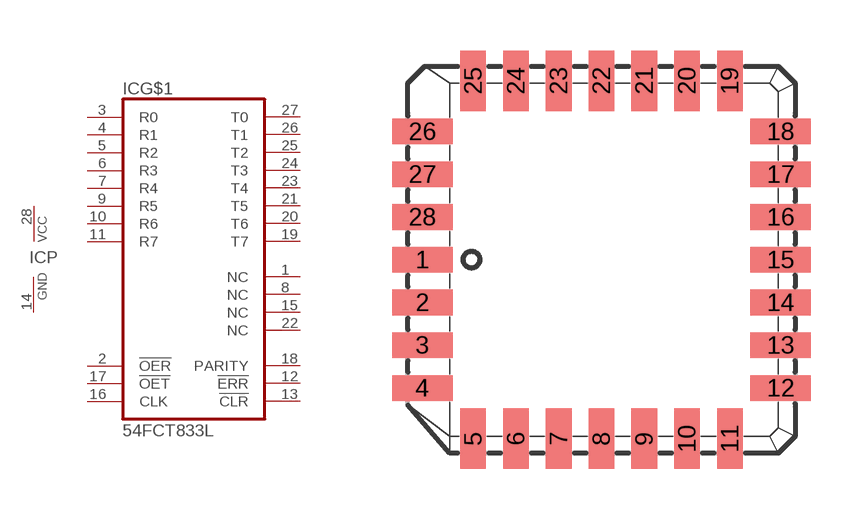
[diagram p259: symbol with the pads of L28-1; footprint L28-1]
Designator prefix IC; gates G$1=833L P=VCCGND

## 54FCT833L (OC_FARNELL: unknown; OC_NEWARK: unknown)  [L28-1]
1  G$1:NC  nc
2  G$1:!OER  in
3  G$1:R0
4  G$1:R1
5  G$1:R2
6  G$1:R3
7  G$1:R4
8  G$1:NC  nc
9  G$1:R5
10  G$1:R6
11  G$1:R7
12  G$1:!ERR  out
13  G$1:!CLR  out
14  P:GND  pwr
15  G$1:NC  nc
16  G$1:CLK  in
17  G$1:!OET  in
18  G$1:PARITY
19  G$1:T7
20  G$1:T6
21  G$1:T5
22  G$1:NC  nc
23  G$1:T4
24  G$1:T3
25  G$1:T2
26  G$1:T1
27  G$1:T0
28  P:VCC  pwr

## Footprint L28-1 (pad centres in mm)
PLASTIC LEADED CHIP CARRIER square
smd 1.8 x 0.76: 1 -5.32,0; 2 -5.32,-1.27; 3 -5.32,-2.54; 4 -5.32,-3.81; 12 5.32,-3.81; 13 5.32,-2.54; 14 5.32,-1.27; 15 5.32,0; 16 5.32,1.27; 17 5.32,2.54; 18 5.32,3.81; 26 -5.32,3.81; 27 -5.32,2.54; 28 -5.32,1.27
smd 0.76 x 1.8: 5 -3.81,-5.32; 6 -2.54,-5.32; 7 -1.27,-5.32; 8 0,-5.32; 9 1.27,-5.32; 10 2.54,-5.32; 11 3.81,-5.32; 19 3.81,5.32; 20 2.54,5.32; 21 1.27,5.32; 22 0,5.32; 23 -1.27,5.32; 24 -2.54,5.32; 25 -3.81,5.32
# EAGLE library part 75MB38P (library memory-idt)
MEMORY

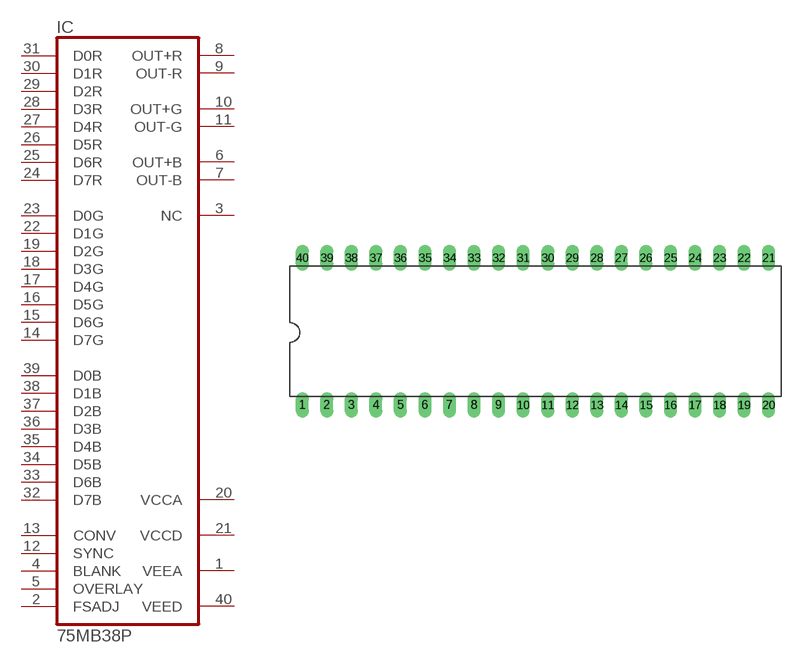
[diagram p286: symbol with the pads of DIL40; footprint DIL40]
Designator prefix IC

## 75MB38P (OC_FARNELL: unknown; OC_NEWARK: unknown)  [DIL40]
1  VEEA  pwr
2  FSADJ  in
3  NC  nc
4  BLANK  in
5  OVERLAY  in
6  OUT+B  out
7  OUT-B  out
8  OUT+R  out
9  OUT-R  out
10  OUT+G  out
11  OUT-G  out
12  SYNC  in
13  CONV  in
14  D7G  in
15  D6G  in
16  D5G  in
17  D4G  in
18  D3G  in
19  D2G  in
20  VCCA  pwr
21  VCCD  pwr
22  D1G  in
23  D0G  in
24  D7R  in
25  D6R  in
26  D5R  in
27  D4R  in
28  D3R  in
29  D2R  in
30  D1R  in
31  D0R  in
32  D7B  in
33  D6B  in
34  D5B  in
35  D4B  in
36  D3B  in
37  D2B  in
38  D1B  in
39  D0B  in
40  VEED  pwr

## Footprint DIL40 (pad centres in mm)
Dual In Line Package
drill 0.813 long: 1 -24.13,-7.62; 2 -21.59,-7.62; 3 -19.05,-7.62; 4 -16.51,-7.62; 5 -13.97,-7.62; 6 -11.43,-7.62; 7 -8.89,-7.62; 8 -6.35,-7.62; 9 -3.81,-7.62; 10 -1.27,-7.62; 11 1.27,-7.62; 12 3.81,-7.62; 13 6.35,-7.62; 14 8.89,-7.62; 15 11.43,-7.62; 16 13.97,-7.62; 17 16.51,-7.62; 18 19.05,-7.62; 19 21.59,-7.62; 20 24.13,-7.62; 21 24.13,7.62; 22 21.59,7.62; 23 19.05,7.62; 24 16.51,7.62; 25 13.97,7.62; 26 11.43,7.62; 27 8.89,7.62; 28 6.35,7.62; 29 3.81,7.62; 30 1.27,7.62; 31 -1.27,7.62; 32 -3.81,7.62; 33 -6.35,7.62; 34 -8.89,7.62; 35 -11.43,7.62; 36 -13.97,7.62; 37 -16.51,7.62; 38 -19.05,7.62; 39 -21.59,7.62; 40 -24.13,7.62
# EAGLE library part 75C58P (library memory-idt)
MEMORY

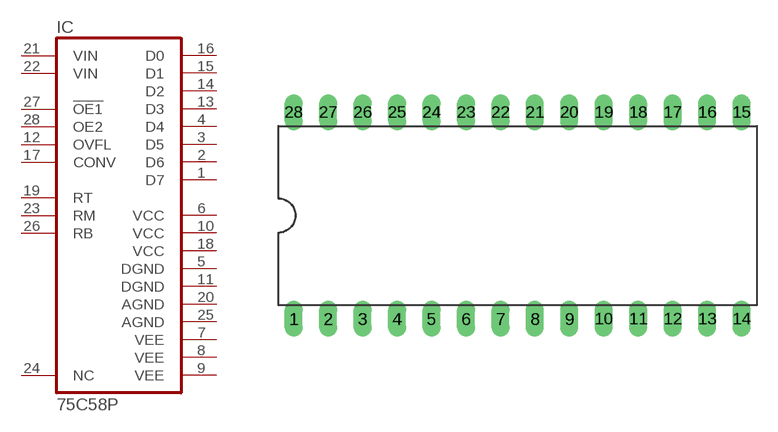
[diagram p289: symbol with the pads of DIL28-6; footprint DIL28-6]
Designator prefix IC

## 75C58P (OC_FARNELL: unknown; OC_NEWARK: unknown)  [DIL28-6]
1  D7  out
2  D6  out
3  D5  out
4  D4  out
5  DGND  pwr
6  VCC  pwr
7  VEE  pwr
8  VEE  pwr
9  VEE  pwr
10  VCC  pwr
11  DGND  pwr
12  OVFL  in
13  D3  out
14  D2  out
15  D1  out
16  D0  out
17  CONV  in
18  VCC  pwr
19  RT  in
20  AGND  pwr
21  VIN  in
22  VIN  in
23  RM  in
24  NC  nc
25  AGND  pwr
26  RB  in
27  !OE1  in
28  OE2  in

## Footprint DIL28-6 (pad centres in mm)
Dual In Line Package 0.6 inch
drill 0.813 long: 1 -16.51,-7.62; 2 -13.97,-7.62; 3 -11.43,-7.62; 4 -8.89,-7.62; 5 -6.35,-7.62; 6 -3.81,-7.62; 7 -1.27,-7.62; 8 1.27,-7.62; 9 3.81,-7.62; 10 6.35,-7.62; 11 8.89,-7.62; 12 11.43,-7.62; 13 13.97,-7.62; 14 16.51,-7.62; 15 16.51,7.62; 16 13.97,7.62; 17 11.43,7.62; 18 8.89,7.62; 19 6.35,7.62; 20 3.81,7.62; 21 1.27,7.62; 22 -1.27,7.62; 23 -3.81,7.62; 24 -6.35,7.62; 25 -8.89,7.62; 26 -11.43,7.62; 27 -13.97,7.62; 28 -16.51,7.62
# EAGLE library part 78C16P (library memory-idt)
MEMORY

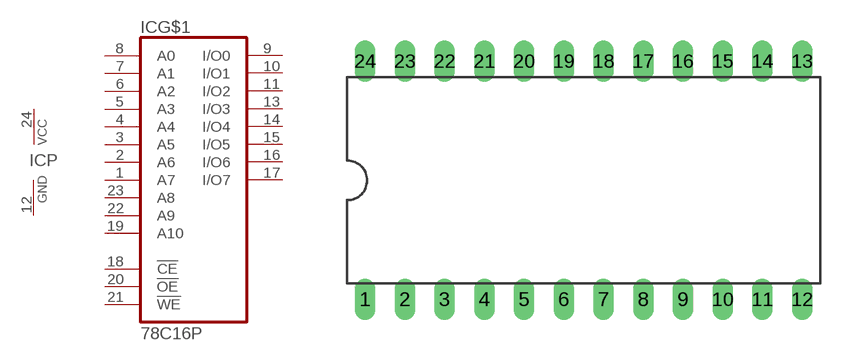
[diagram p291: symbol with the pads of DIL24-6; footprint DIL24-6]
Designator prefix IC; gates G$1=78C16 P=VCCGND

## 78C16P (OC_FARNELL: unknown; OC_NEWARK: unknown)  [DIL24-6]
1  G$1:A7  in
2  G$1:A6  in
3  G$1:A5  in
4  G$1:A4  in
5  G$1:A3  in
6  G$1:A2  in
7  G$1:A1  in
8  G$1:A0  in
9  G$1:I/O0
10  G$1:I/O1
11  G$1:I/O2
12  P:GND  pwr
13  G$1:I/O3
14  G$1:I/O4
15  G$1:I/O5
16  G$1:I/O6
17  G$1:I/O7
18  G$1:!CE  in
19  G$1:A10  in
20  G$1:!OE  in
21  G$1:!WE  in
22  G$1:A9  in
23  G$1:A8  in
24  P:VCC  pwr

## Footprint DIL24-6 (pad centres in mm)
Dual In Line Package 0.6 inch
drill 0.813 long: 1 -13.97,-7.62; 2 -11.43,-7.62; 3 -8.89,-7.62; 4 -6.35,-7.62; 5 -3.81,-7.62; 6 -1.27,-7.62; 7 1.27,-7.62; 8 3.81,-7.62; 9 6.35,-7.62; 10 8.89,-7.62; 11 11.43,-7.62; 12 13.97,-7.62; 13 13.97,7.62; 14 11.43,7.62; 15 8.89,7.62; 16 6.35,7.62; 17 3.81,7.62; 18 1.27,7.62; 19 -1.27,7.62; 20 -3.81,7.62; 21 -6.35,7.62; 22 -8.89,7.62; 23 -11.43,7.62; 24 -13.97,7.62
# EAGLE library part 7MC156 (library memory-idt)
MEMORY

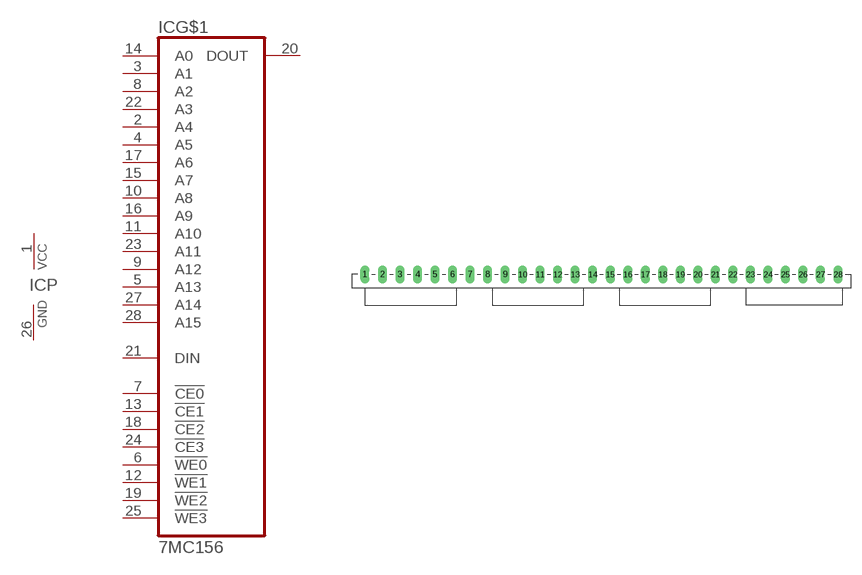
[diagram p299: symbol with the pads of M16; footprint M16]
Designator prefix IC; gates G$1=7MC156 P=VCCGND

## 7MC156 (OC_FARNELL: unknown; OC_NEWARK: unknown)  [M16]
1  P:VCC  pwr
2  G$1:A4  in
3  G$1:A1  in
4  G$1:A5  in
5  G$1:A13  in
6  G$1:!WE0  in
7  G$1:!CE0  in
8  G$1:A2  in
9  G$1:A12  in
10  G$1:A8  in
11  G$1:A10  in
12  G$1:!WE1  in
13  G$1:!CE1  in
14  G$1:A0  in
15  G$1:A7  in
16  G$1:A9  in
17  G$1:A6  in
18  G$1:!CE2  in
19  G$1:!WE2  in
20  G$1:DOUT  out
21  G$1:DIN  in
22  G$1:A3  in
23  G$1:A11  in
24  G$1:!CE3  in
25  G$1:!WE3  in
26  P:GND  pwr
27  G$1:A14  in
28  G$1:A15  in

## Footprint M16 (pad centres in mm)
Single In Line
drill 0.813 long: 1 -34.29,1.27; 2 -31.75,1.27; 3 -29.21,1.27; 4 -26.67,1.27; 5 -24.13,1.27; 6 -21.59,1.27; 7 -19.05,1.27; 8 -16.51,1.27; 9 -13.97,1.27; 10 -11.43,1.27; 11 -8.89,1.27; 12 -6.35,1.27; 13 -3.81,1.27; 14 -1.27,1.27; 15 1.27,1.27; 16 3.81,1.27; 17 6.35,1.27; 18 8.89,1.27; 19 11.43,1.27; 20 13.97,1.27; 21 16.51,1.27; 22 19.05,1.27; 23 21.59,1.27; 24 24.13,1.27; 25 26.67,1.27; 26 29.21,1.27; 27 31.75,1.27; 28 34.29,1.27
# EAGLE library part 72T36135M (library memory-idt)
2.5V 18M-BIT HIGH-SPEED TeraSyncTM FIFO 36-BIT CONFIGURATIONS 524,288 x 36 Source: http://www.idt.com/products/files/4613033/72T36135M_DS.pdf

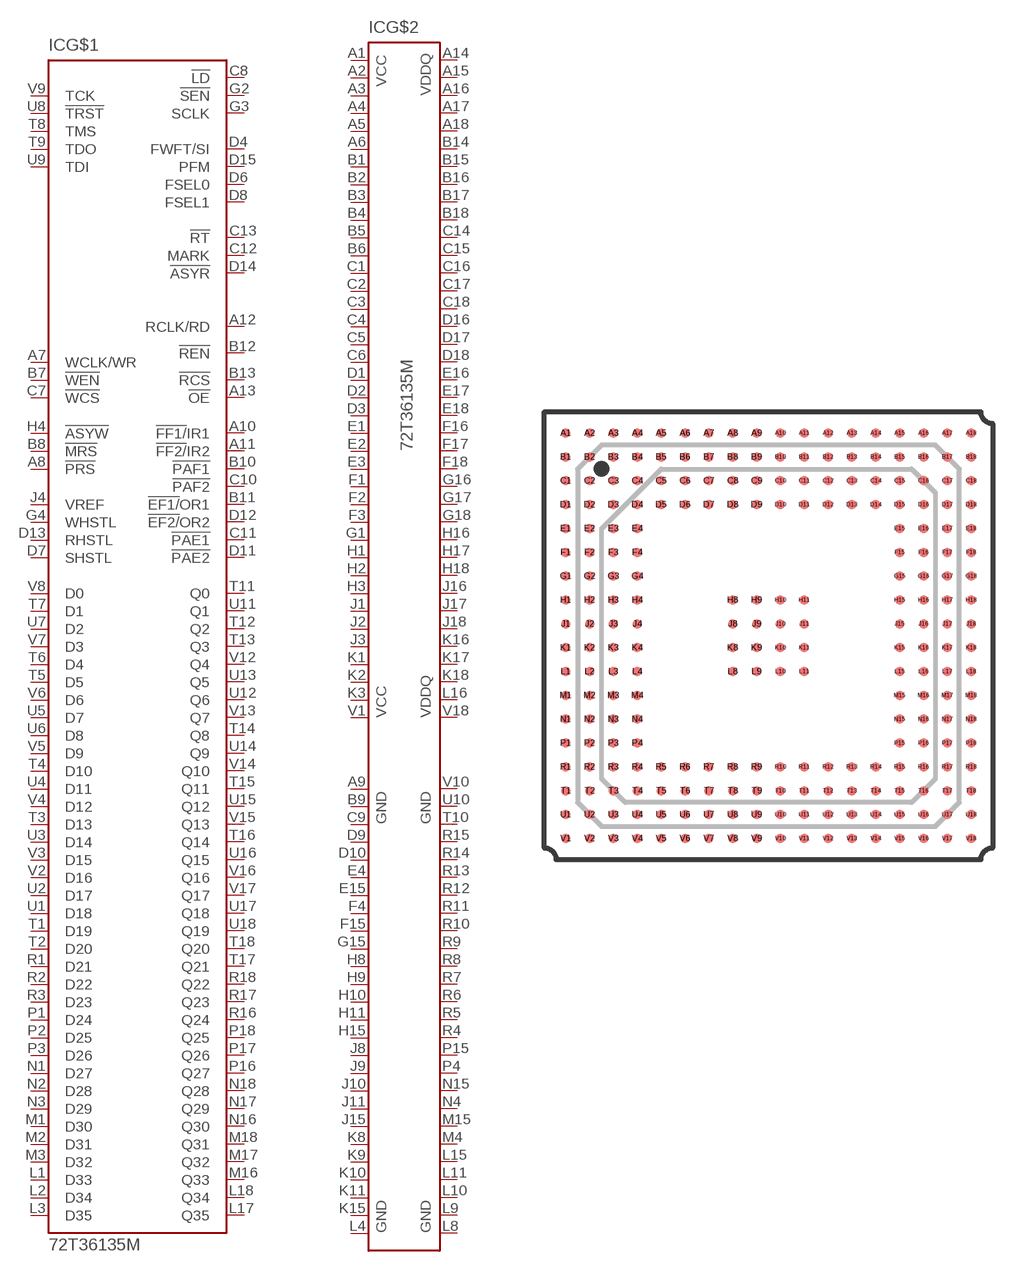
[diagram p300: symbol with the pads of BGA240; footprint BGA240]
Designator prefix IC; gates G$1=72T36135M G$2=72T36135M-P

## 72T36135M (OC_FARNELL: unknown; OC_NEWARK: unknown)  [BGA240]
A1  G$2:VCC  pwr
A2  G$2:VCC  pwr
A3  G$2:VCC  pwr
A4  G$2:VCC  pwr
A5  G$2:VCC  pwr
A6  G$2:VCC  pwr
A7  G$1:WCLK/WR  in
A8  G$1:!PRS  in
A9  G$2:GND  pwr
A10  G$1:!FF1/!IR1  out
A11  G$1:!FF2/!IR2  out
A12  G$1:RCLK/RD  in
A13  G$1:!OE  in
A14  G$2:VDDQ  pwr
A15  G$2:VDDQ  pwr
A16  G$2:VDDQ  pwr
A17  G$2:VDDQ  pwr
A18  G$2:VDDQ  pwr
B1  G$2:VCC  pwr
B2  G$2:VCC  pwr
B3  G$2:VCC  pwr
B4  G$2:VCC  pwr
B5  G$2:VCC  pwr
B6  G$2:VCC  pwr
B7  G$1:!WEN  in
B8  G$1:!MRS  in
B9  G$2:GND  pwr
B10  G$1:!PAF1  out
B11  G$1:!EF1/!OR1  out
B12  G$1:!REN  in
B13  G$1:!RCS  in
B14  G$2:VDDQ  pwr
B15  G$2:VDDQ  pwr
B16  G$2:VDDQ  pwr
B17  G$2:VDDQ  pwr
B18  G$2:VDDQ  pwr
C1  G$2:VCC  pwr
C2  G$2:VCC  pwr
C3  G$2:VCC  pwr
C4  G$2:VCC  pwr
C5  G$2:VCC  pwr
C6  G$2:VCC  pwr
C7  G$1:!WCS  in
C8  G$1:!LD  in
C9  G$2:GND  pwr
C10  G$1:!PAF2  out
C11  G$1:!PAE1  out
C12  G$1:MARK  in
C13  G$1:!RT  in
C14  G$2:VDDQ  pwr
C15  G$2:VDDQ  pwr
C16  G$2:VDDQ  pwr
C17  G$2:VDDQ  pwr
C18  G$2:VDDQ  pwr
D1  G$2:VCC  pwr
D2  G$2:VCC  pwr
D3  G$2:VCC  pwr
D4  G$1:FWFT/SI  in
D5  G$1:DNC  nc
D6  G$1:FSEL0  in
D7  G$1:SHSTL  in
D8  G$1:FSEL1  in
D9  G$2:GND  pwr
D10  G$2:GND  pwr
D11  G$1:!PAE2  out
D12  G$1:!EF2/!OR2  out
D13  G$1:RHSTL  in
D14  G$1:!ASYR  in
D15  G$1:PFM  in
D16  G$2:VDDQ  pwr
D17  G$2:VDDQ  pwr
D18  G$2:VDDQ  pwr
E1  G$2:VCC  pwr
E2  G$2:VCC  pwr
E3  G$2:VCC  pwr
E4  G$2:GND  pwr
E15  G$2:GND  pwr
E16  G$2:VDDQ  pwr
E17  G$2:VDDQ  pwr
E18  G$2:VDDQ  pwr
F1  G$2:VCC  pwr
F2  G$2:VCC  pwr
F3  G$2:VCC  pwr
F4  G$2:GND  pwr
F15  G$2:GND  pwr
F16  G$2:VDDQ  pwr
F17  G$2:VDDQ  pwr
F18  G$2:VDDQ  pwr
G1  G$2:VCC  pwr
G2  G$1:!SEN  in
G3  G$1:SCLK  in
G4  G$1:WHSTL  in
G15  G$2:GND  pwr
G16  G$2:VDDQ  pwr
G17  G$2:VDDQ  pwr
G18  G$2:VDDQ  pwr
H1  G$2:VCC  pwr
H2  G$2:VCC  pwr
H3  G$2:VCC  pwr
H4  G$1:!ASYW  in
H8  G$2:GND  pwr
H9  G$2:GND  pwr
H10  G$2:GND  pwr
H11  G$2:GND  pwr
H15  G$2:GND  pwr
H16  G$2:VDDQ  pwr
H17  G$2:VDDQ  pwr
H18  G$2:VDDQ  pwr
J1  G$2:VCC  pwr
J2  G$2:VCC  pwr
J3  G$2:VCC  pwr
J4  G$1:VREF  in
J8  G$2:GND  pwr
J9  G$2:GND  pwr
J10  G$2:GND  pwr
J11  G$2:GND  pwr
J15  G$2:GND  pwr
J16  G$2:VDDQ  pwr
J17  G$2:VDDQ  pwr
J18  G$2:VDDQ  pwr
K1  G$2:VCC  pwr
K2  G$2:VCC  pwr
K3  G$2:VCC  pwr
K4  G$1:DNC  nc
K8  G$2:GND  pwr
K9  G$2:GND  pwr
K10  G$2:GND  pwr
K11  G$2:GND  pwr
K15  G$2:GND  pwr
K16  G$2:VDDQ  pwr
K17  G$2:VDDQ  pwr
K18  G$2:VDDQ  pwr
L1  G$1:D33  in
L2  G$1:D34  in
L3  G$1:D35  in
L4  G$2:GND  pwr
L8  G$2:GND  pwr
L9  G$2:GND  pwr
L10  G$2:GND  pwr
L11  G$2:GND  pwr
L15  G$2:GND  pwr
L16  G$2:VDDQ  pwr
L17  G$1:Q35  hiz
L18  G$1:Q34  hiz
M1  G$1:D30  in
M2  G$1:D31  in
M3  G$1:D32  in
M4  G$2:GND  pwr
M15  G$2:GND  pwr
M16  G$1:Q33  hiz
M17  G$1:Q32  hiz
M18  G$1:Q31  hiz
N1  G$1:D27  in
N2  G$1:D28  in
N3  G$1:D29  in
N4  G$2:GND  pwr
N15  G$2:GND  pwr
N16  G$1:Q30  hiz
N17  G$1:Q29  hiz
N18  G$1:Q28  hiz
P1  G$1:D24  in
P2  G$1:D25  in
P3  G$1:D26  in
P4  G$2:GND  pwr
P15  G$2:GND  pwr
P16  G$1:Q27  hiz
P17  G$1:Q26  hiz
P18  G$1:Q25  hiz
R1  G$1:D21  in
R2  G$1:D22  in
R3  G$1:D23  in
R4  G$2:GND  pwr
R5  G$2:GND  pwr
R6  G$2:GND  pwr
R7  G$2:GND  pwr
R8  G$2:GND  pwr
R9  G$2:GND  pwr
R10  G$2:GND  pwr
R11  G$2:GND  pwr
R12  G$2:GND  pwr
R13  G$2:GND  pwr
R14  G$2:GND  pwr
R15  G$2:GND  pwr
R16  G$1:Q24  hiz
R17  G$1:Q23  hiz
R18  G$1:Q22  hiz
T1  G$1:D19  in
T2  G$1:D20  in
T3  G$1:D13  in
T4  G$1:D10  in
T5  G$1:D5  in
T6  G$1:D4  in
T7  G$1:D1  in
T8  G$1:TMS  in
T9  G$1:TDO  in
T10  G$2:GND  pwr
T11  G$1:Q0  hiz
T12  G$1:Q2  hiz
T13  G$1:Q3  hiz
T14  G$1:Q8  hiz
T15  G$1:Q11  hiz
T16  G$1:Q14  hiz
T17  G$1:Q21  hiz
T18  G$1:Q20  hiz
U1  G$1:D18  in
U2  G$1:D17  in
U3  G$1:D14  in
U4  G$1:D11  in
U5  G$1:D7  in
U6  G$1:D8  in
U7  G$1:D2  in
U8  G$1:!TRST  in
U9  G$1:TDI  in
U10  G$2:GND  pwr
U11  G$1:Q1  hiz
U12  G$1:Q6  hiz
U13  G$1:Q5  hiz
U14  G$1:Q9  hiz
U15  G$1:Q12  hiz
U16  G$1:Q15  hiz
U17  G$1:Q18  hiz
U18  G$1:Q19  hiz
V1  G$2:VCC  pwr
V2  G$1:D16  in
V3  G$1:D15  in
V4  G$1:D12  in
V5  G$1:D9  in
V6  G$1:D6  in
V7  G$1:D3  in
V8  G$1:D0  in
V9  G$1:TCK  in
V10  G$2:GND  pwr
V11  G$1:DNC  nc
V12  G$1:Q4  hiz
V13  G$1:Q7  hiz
V14  G$1:Q10  hiz
V15  G$1:Q13  hiz
V16  G$1:Q16  hiz
V17  G$1:Q17  hiz
V18  G$2:VDDQ  pwr

## Footprint BGA240 (pad centres in mm)
BGA 240 19 x 19 mm Source: http://www.idt.com/products/files/10222/PSC4104.pdf
smd 0.4 x 0.4: A1 -8.5,8.5; A2 -7.5,8.5; A3 -6.5,8.5; A4 -5.5,8.5; A5 -4.5,8.5; A6 -3.5,8.5; A7 -2.5,8.5; A8 -1.5,8.5; A9 -0.5,8.5; A10 0.5,8.5; A11 1.5,8.5; A12 2.5,8.5; A13 3.5,8.5; A14 4.5,8.5; A15 5.5,8.5; A16 6.5,8.5; A17 7.5,8.5; A18 8.5,8.5; B1 -8.5,7.5; B2 -7.5,7.5; B3 -6.5,7.5; B4 -5.5,7.5; B5 -4.5,7.5; B6 -3.5,7.5; B7 -2.5,7.5; B8 -1.5,7.5; B9 -0.5,7.5; B10 0.5,7.5; B11 1.5,7.5; B12 2.5,7.5; B13 3.5,7.5; B14 4.5,7.5; B15 5.5,7.5; B16 6.5,7.5; B17 7.5,7.5; B18 8.5,7.5; C1 -8.5,6.5; C2 -7.5,6.5; C3 -6.5,6.5; C4 -5.5,6.5; C5 -4.5,6.5; C6 -3.5,6.5; C7 -2.5,6.5; C8 -1.5,6.5; C9 -0.5,6.5; C10 0.5,6.5; C11 1.5,6.5; C12 2.5,6.5; C13 3.5,6.5; C14 4.5,6.5; C15 5.5,6.5; C16 6.5,6.5; C17 7.5,6.5; C18 8.5,6.5; D1 -8.5,5.5; D2 -7.5,5.5; D3 -6.5,5.5; D4 -5.5,5.5; D5 -4.5,5.5; D6 -3.5,5.5; D7 -2.5,5.5; D8 -1.5,5.5; D9 -0.5,5.5; D10 0.5,5.5; D11 1.5,5.5; D12 2.5,5.5; D13 3.5,5.5; D14 4.5,5.5; D15 5.5,5.5; D16 6.5,5.5; D17 7.5,5.5; D18 8.5,5.5; E1 -8.5,4.5; E2 -7.5,4.5; E3 -6.5,4.5; E4 -5.5,4.5; E15 5.5,4.5; E16 6.5,4.5; E17 7.5,4.5; E18 8.5,4.5; F1 -8.5,3.5; F2 -7.5,3.5; F3 -6.5,3.5; F4 -5.5,3.5; F15 5.5,3.5; F16 6.5,3.5; F17 7.5,3.5; F18 8.5,3.5; G1 -8.5,2.5; G2 -7.5,2.5; G3 -6.5,2.5; G4 -5.5,2.5; G15 5.5,2.5; G16 6.5,2.5; G17 7.5,2.5; G18 8.5,2.5; H1 -8.5,1.5; H2 -7.5,1.5; H3 -6.5,1.5; H4 -5.5,1.5; H8 -1.5,1.5; H9 -0.5,1.5; H10 0.5,1.5; H11 1.5,1.5; H15 5.5,1.5; H16 6.5,1.5; H17 7.5,1.5; H18 8.5,1.5; J1 -8.5,0.5; J2 -7.5,0.5; J3 -6.5,0.5; J4 -5.5,0.5; J8 -1.5,0.5; J9 -0.5,0.5; J10 0.5,0.5; J11 1.5,0.5; J15 5.5,0.5; J16 6.5,0.5; J17 7.5,0.5; J18 8.5,0.5; K1 -8.5,-0.5; K2 -7.5,-0.5; K3 -6.5,-0.5; K4 -5.5,-0.5; K8 -1.5,-0.5; K9 -0.5,-0.5; K10 0.5,-0.5; K11 1.5,-0.5; K15 5.5,-0.5; K16 6.5,-0.5; K17 7.5,-0.5; K18 8.5,-0.5; L1 -8.5,-1.5; L2 -7.5,-1.5; L3 -6.5,-1.5; L4 -5.5,-1.5; L8 -1.5,-1.5; L9 -0.5,-1.5; L10 0.5,-1.5; L11 1.5,-1.5; L15 5.5,-1.5; L16 6.5,-1.5; L17 7.5,-1.5; L18 8.5,-1.5; M1 -8.5,-2.5; M2 -7.5,-2.5; M3 -6.5,-2.5; M4 -5.5,-2.5; M15 5.5,-2.5; M16 6.5,-2.5; M17 7.5,-2.5; M18 8.5,-2.5; N1 -8.5,-3.5; N2 -7.5,-3.5; N3 -6.5,-3.5; N4 -5.5,-3.5; N15 5.5,-3.5; N16 6.5,-3.5; N17 7.5,-3.5; N18 8.5,-3.5; P1 -8.5,-4.5; P2 -7.5,-4.5; P3 -6.5,-4.5; P4 -5.5,-4.5; P15 5.5,-4.5; P16 6.5,-4.5; P17 7.5,-4.5; P18 8.5,-4.5; R1 -8.5,-5.5; R2 -7.5,-5.5; R3 -6.5,-5.5; R4 -5.5,-5.5; R5 -4.5,-5.5; R6 -3.5,-5.5; R7 -2.5,-5.5; R8 -1.5,-5.5; R9 -0.5,-5.5; R10 0.5,-5.5; R11 1.5,-5.5; R12 2.5,-5.5; R13 3.5,-5.5; R14 4.5,-5.5; R15 5.5,-5.5; R16 6.5,-5.5; R17 7.5,-5.5; R18 8.5,-5.5; T1 -8.5,-6.5; T2 -7.5,-6.5; T3 -6.5,-6.5; T4 -5.5,-6.5; T5 -4.5,-6.5; T6 -3.5,-6.5; T7 -2.5,-6.5; T8 -1.5,-6.5; T9 -0.5,-6.5; T10 0.5,-6.5; T11 1.5,-6.5; T12 2.5,-6.5; T13 3.5,-6.5; T14 4.5,-6.5; T15 5.5,-6.5; T16 6.5,-6.5; T17 7.5,-6.5; T18 8.5,-6.5; U1 -8.5,-7.5; U2 -7.5,-7.5; U3 -6.5,-7.5; U4 -5.5,-7.5; U5 -4.5,-7.5; U6 -3.5,-7.5; U7 -2.5,-7.5; U8 -1.5,-7.5; U9 -0.5,-7.5; U10 0.5,-7.5; U11 1.5,-7.5; U12 2.5,-7.5; U13 3.5,-7.5; U14 4.5,-7.5; U15 5.5,-7.5; U16 6.5,-7.5; U17 7.5,-7.5; U18 8.5,-7.5; V1 -8.5,-8.5; V2 -7.5,-8.5; V3 -6.5,-8.5; V4 -5.5,-8.5; V5 -4.5,-8.5; V6 -3.5,-8.5; V7 -2.5,-8.5; V8 -1.5,-8.5; V9 -0.5,-8.5; V10 0.5,-8.5; V11 1.5,-8.5; V12 2.5,-8.5; V13 3.5,-8.5; V14 4.5,-8.5; V15 5.5,-8.5; V16 6.5,-8.5; V17 7.5,-8.5; V18 8.5,-8.5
